VERSION 5.8 ;
BUSBITCHARS "[]" ;
DIVIDERCHAR "/" ;
UNITS
    DATABASE MICRONS 1000 ;
END UNITS

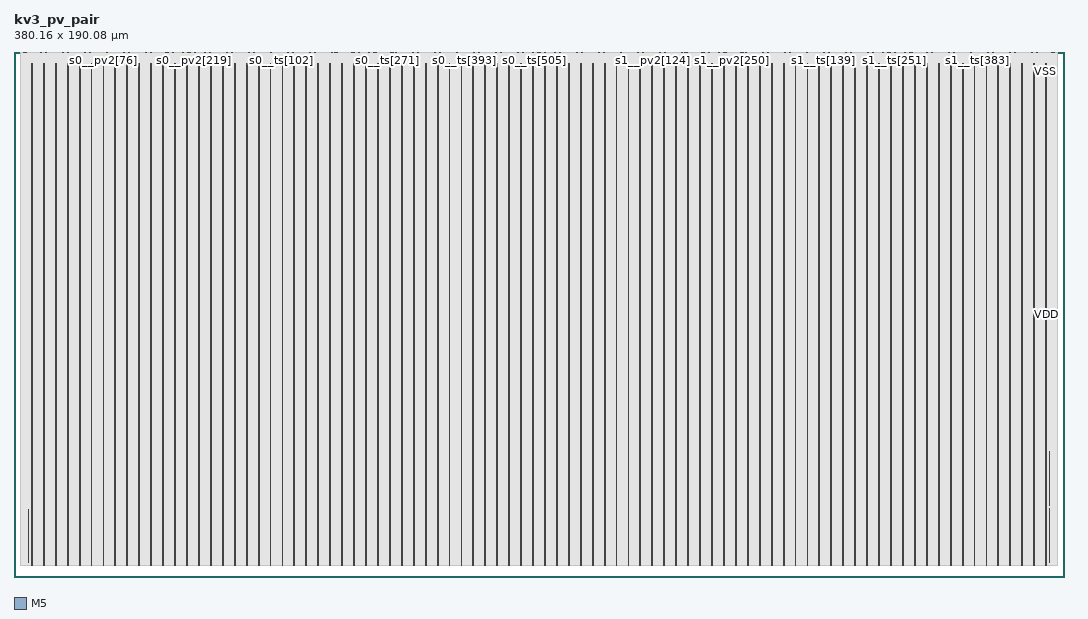
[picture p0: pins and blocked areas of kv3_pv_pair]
MACRO kv3_pv_pair
  FOREIGN kv3_pv_pair 0 0 ;
  CLASS BLOCK ;
  SIZE 380.16 BY 190.08 ;
  PIN s0__bc[0]
    DIRECTION INPUT ;
    USE SIGNAL ;
    PORT
      LAYER M5 ;
        RECT  2.268 189.888 2.292 190.08 ;
    END
  END s0__bc[0]
  PIN s0__bc[10]
    DIRECTION INPUT ;
    USE SIGNAL ;
    PORT
      LAYER M5 ;
        RECT  4.524 189.888 4.548 190.08 ;
    END
  END s0__bc[10]
  PIN s0__bc[11]
    DIRECTION INPUT ;
    USE SIGNAL ;
    PORT
      LAYER M5 ;
        RECT  4.764 189.888 4.788 190.08 ;
    END
  END s0__bc[11]
  PIN s0__bc[12]
    DIRECTION INPUT ;
    USE SIGNAL ;
    PORT
      LAYER M5 ;
        RECT  5.004 189.888 5.028 190.08 ;
    END
  END s0__bc[12]
  PIN s0__bc[13]
    DIRECTION INPUT ;
    USE SIGNAL ;
    PORT
      LAYER M5 ;
        RECT  5.196 189.888 5.22 190.08 ;
    END
  END s0__bc[13]
  PIN s0__bc[14]
    DIRECTION INPUT ;
    USE SIGNAL ;
    PORT
      LAYER M5 ;
        RECT  5.436 189.888 5.46 190.08 ;
    END
  END s0__bc[14]
  PIN s0__bc[15]
    DIRECTION INPUT ;
    USE SIGNAL ;
    PORT
      LAYER M5 ;
        RECT  5.676 189.888 5.7 190.08 ;
    END
  END s0__bc[15]
  PIN s0__bc[16]
    DIRECTION INPUT ;
    USE SIGNAL ;
    PORT
      LAYER M5 ;
        RECT  5.916 189.888 5.94 190.08 ;
    END
  END s0__bc[16]
  PIN s0__bc[17]
    DIRECTION INPUT ;
    USE SIGNAL ;
    PORT
      LAYER M5 ;
        RECT  6.108 189.888 6.132 190.08 ;
    END
  END s0__bc[17]
  PIN s0__bc[18]
    DIRECTION INPUT ;
    USE SIGNAL ;
    PORT
      LAYER M5 ;
        RECT  6.348 189.888 6.372 190.08 ;
    END
  END s0__bc[18]
  PIN s0__bc[19]
    DIRECTION INPUT ;
    USE SIGNAL ;
    PORT
      LAYER M5 ;
        RECT  6.588 189.888 6.612 190.08 ;
    END
  END s0__bc[19]
  PIN s0__bc[1]
    DIRECTION INPUT ;
    USE SIGNAL ;
    PORT
      LAYER M5 ;
        RECT  2.508 189.888 2.532 190.08 ;
    END
  END s0__bc[1]
  PIN s0__bc[20]
    DIRECTION INPUT ;
    USE SIGNAL ;
    PORT
      LAYER M5 ;
        RECT  6.828 189.888 6.852 190.08 ;
    END
  END s0__bc[20]
  PIN s0__bc[21]
    DIRECTION INPUT ;
    USE SIGNAL ;
    PORT
      LAYER M5 ;
        RECT  7.02 189.888 7.044 190.08 ;
    END
  END s0__bc[21]
  PIN s0__bc[22]
    DIRECTION INPUT ;
    USE SIGNAL ;
    PORT
      LAYER M5 ;
        RECT  7.26 189.888 7.284 190.08 ;
    END
  END s0__bc[22]
  PIN s0__bc[2]
    DIRECTION INPUT ;
    USE SIGNAL ;
    PORT
      LAYER M5 ;
        RECT  2.7 189.888 2.724 190.08 ;
    END
  END s0__bc[2]
  PIN s0__bc[3]
    DIRECTION INPUT ;
    USE SIGNAL ;
    PORT
      LAYER M5 ;
        RECT  2.94 189.888 2.964 190.08 ;
    END
  END s0__bc[3]
  PIN s0__bc[4]
    DIRECTION INPUT ;
    USE SIGNAL ;
    PORT
      LAYER M5 ;
        RECT  3.18 189.888 3.204 190.08 ;
    END
  END s0__bc[4]
  PIN s0__bc[5]
    DIRECTION INPUT ;
    USE SIGNAL ;
    PORT
      LAYER M5 ;
        RECT  3.42 189.888 3.444 190.08 ;
    END
  END s0__bc[5]
  PIN s0__bc[6]
    DIRECTION INPUT ;
    USE SIGNAL ;
    PORT
      LAYER M5 ;
        RECT  3.612 189.888 3.636 190.08 ;
    END
  END s0__bc[6]
  PIN s0__bc[7]
    DIRECTION INPUT ;
    USE SIGNAL ;
    PORT
      LAYER M5 ;
        RECT  3.852 189.888 3.876 190.08 ;
    END
  END s0__bc[7]
  PIN s0__bc[8]
    DIRECTION INPUT ;
    USE SIGNAL ;
    PORT
      LAYER M5 ;
        RECT  4.092 189.888 4.116 190.08 ;
    END
  END s0__bc[8]
  PIN s0__bc[9]
    DIRECTION INPUT ;
    USE SIGNAL ;
    PORT
      LAYER M5 ;
        RECT  4.332 189.888 4.356 190.08 ;
    END
  END s0__bc[9]
  PIN s0__clk[0]
    DIRECTION INPUT ;
    USE SIGNAL ;
    PORT
      LAYER M5 ;
        RECT  7.5 189.888 7.524 190.08 ;
    END
  END s0__clk[0]
  PIN s0__fault[0]
    DIRECTION OUTPUT ;
    USE SIGNAL ;
    PORT
      LAYER M5 ;
        RECT  7.74 189.888 7.764 190.08 ;
    END
  END s0__fault[0]
  PIN s0__pe2[0]
    DIRECTION INPUT ;
    USE SIGNAL ;
    PORT
      LAYER M5 ;
        RECT  7.932 189.888 7.956 190.08 ;
    END
  END s0__pe2[0]
  PIN s0__pe2[10]
    DIRECTION INPUT ;
    USE SIGNAL ;
    PORT
      LAYER M5 ;
        RECT  10.236 189.888 10.26 190.08 ;
    END
  END s0__pe2[10]
  PIN s0__pe2[11]
    DIRECTION INPUT ;
    USE SIGNAL ;
    PORT
      LAYER M5 ;
        RECT  10.428 189.888 10.452 190.08 ;
    END
  END s0__pe2[11]
  PIN s0__pe2[12]
    DIRECTION INPUT ;
    USE SIGNAL ;
    PORT
      LAYER M5 ;
        RECT  10.668 189.888 10.692 190.08 ;
    END
  END s0__pe2[12]
  PIN s0__pe2[13]
    DIRECTION INPUT ;
    USE SIGNAL ;
    PORT
      LAYER M5 ;
        RECT  10.908 189.888 10.932 190.08 ;
    END
  END s0__pe2[13]
  PIN s0__pe2[14]
    DIRECTION INPUT ;
    USE SIGNAL ;
    PORT
      LAYER M5 ;
        RECT  11.148 189.888 11.172 190.08 ;
    END
  END s0__pe2[14]
  PIN s0__pe2[15]
    DIRECTION INPUT ;
    USE SIGNAL ;
    PORT
      LAYER M5 ;
        RECT  11.34 189.888 11.364 190.08 ;
    END
  END s0__pe2[15]
  PIN s0__pe2[16]
    DIRECTION INPUT ;
    USE SIGNAL ;
    PORT
      LAYER M5 ;
        RECT  11.58 189.888 11.604 190.08 ;
    END
  END s0__pe2[16]
  PIN s0__pe2[17]
    DIRECTION INPUT ;
    USE SIGNAL ;
    PORT
      LAYER M5 ;
        RECT  11.82 189.888 11.844 190.08 ;
    END
  END s0__pe2[17]
  PIN s0__pe2[18]
    DIRECTION INPUT ;
    USE SIGNAL ;
    PORT
      LAYER M5 ;
        RECT  12.06 189.888 12.084 190.08 ;
    END
  END s0__pe2[18]
  PIN s0__pe2[19]
    DIRECTION INPUT ;
    USE SIGNAL ;
    PORT
      LAYER M5 ;
        RECT  12.252 189.888 12.276 190.08 ;
    END
  END s0__pe2[19]
  PIN s0__pe2[1]
    DIRECTION INPUT ;
    USE SIGNAL ;
    PORT
      LAYER M5 ;
        RECT  8.172 189.888 8.196 190.08 ;
    END
  END s0__pe2[1]
  PIN s0__pe2[20]
    DIRECTION INPUT ;
    USE SIGNAL ;
    PORT
      LAYER M5 ;
        RECT  12.492 189.888 12.516 190.08 ;
    END
  END s0__pe2[20]
  PIN s0__pe2[21]
    DIRECTION INPUT ;
    USE SIGNAL ;
    PORT
      LAYER M5 ;
        RECT  12.732 189.888 12.756 190.08 ;
    END
  END s0__pe2[21]
  PIN s0__pe2[22]
    DIRECTION INPUT ;
    USE SIGNAL ;
    PORT
      LAYER M5 ;
        RECT  12.972 189.888 12.996 190.08 ;
    END
  END s0__pe2[22]
  PIN s0__pe2[23]
    DIRECTION INPUT ;
    USE SIGNAL ;
    PORT
      LAYER M5 ;
        RECT  13.164 189.888 13.188 190.08 ;
    END
  END s0__pe2[23]
  PIN s0__pe2[24]
    DIRECTION INPUT ;
    USE SIGNAL ;
    PORT
      LAYER M5 ;
        RECT  13.404 189.888 13.428 190.08 ;
    END
  END s0__pe2[24]
  PIN s0__pe2[25]
    DIRECTION INPUT ;
    USE SIGNAL ;
    PORT
      LAYER M5 ;
        RECT  13.644 189.888 13.668 190.08 ;
    END
  END s0__pe2[25]
  PIN s0__pe2[26]
    DIRECTION INPUT ;
    USE SIGNAL ;
    PORT
      LAYER M5 ;
        RECT  13.884 189.888 13.908 190.08 ;
    END
  END s0__pe2[26]
  PIN s0__pe2[27]
    DIRECTION INPUT ;
    USE SIGNAL ;
    PORT
      LAYER M5 ;
        RECT  14.076 189.888 14.1 190.08 ;
    END
  END s0__pe2[27]
  PIN s0__pe2[28]
    DIRECTION INPUT ;
    USE SIGNAL ;
    PORT
      LAYER M5 ;
        RECT  14.316 189.888 14.34 190.08 ;
    END
  END s0__pe2[28]
  PIN s0__pe2[29]
    DIRECTION INPUT ;
    USE SIGNAL ;
    PORT
      LAYER M5 ;
        RECT  14.556 189.888 14.58 190.08 ;
    END
  END s0__pe2[29]
  PIN s0__pe2[2]
    DIRECTION INPUT ;
    USE SIGNAL ;
    PORT
      LAYER M5 ;
        RECT  8.412 189.888 8.436 190.08 ;
    END
  END s0__pe2[2]
  PIN s0__pe2[30]
    DIRECTION INPUT ;
    USE SIGNAL ;
    PORT
      LAYER M5 ;
        RECT  14.796 189.888 14.82 190.08 ;
    END
  END s0__pe2[30]
  PIN s0__pe2[31]
    DIRECTION INPUT ;
    USE SIGNAL ;
    PORT
      LAYER M5 ;
        RECT  14.988 189.888 15.012 190.08 ;
    END
  END s0__pe2[31]
  PIN s0__pe2[3]
    DIRECTION INPUT ;
    USE SIGNAL ;
    PORT
      LAYER M5 ;
        RECT  8.652 189.888 8.676 190.08 ;
    END
  END s0__pe2[3]
  PIN s0__pe2[4]
    DIRECTION INPUT ;
    USE SIGNAL ;
    PORT
      LAYER M5 ;
        RECT  8.844 189.888 8.868 190.08 ;
    END
  END s0__pe2[4]
  PIN s0__pe2[5]
    DIRECTION INPUT ;
    USE SIGNAL ;
    PORT
      LAYER M5 ;
        RECT  9.084 189.888 9.108 190.08 ;
    END
  END s0__pe2[5]
  PIN s0__pe2[6]
    DIRECTION INPUT ;
    USE SIGNAL ;
    PORT
      LAYER M5 ;
        RECT  9.324 189.888 9.348 190.08 ;
    END
  END s0__pe2[6]
  PIN s0__pe2[7]
    DIRECTION INPUT ;
    USE SIGNAL ;
    PORT
      LAYER M5 ;
        RECT  9.564 189.888 9.588 190.08 ;
    END
  END s0__pe2[7]
  PIN s0__pe2[8]
    DIRECTION INPUT ;
    USE SIGNAL ;
    PORT
      LAYER M5 ;
        RECT  9.756 189.888 9.78 190.08 ;
    END
  END s0__pe2[8]
  PIN s0__pe2[9]
    DIRECTION INPUT ;
    USE SIGNAL ;
    PORT
      LAYER M5 ;
        RECT  9.996 189.888 10.02 190.08 ;
    END
  END s0__pe2[9]
  PIN s0__pv2[0]
    DIRECTION INPUT ;
    USE SIGNAL ;
    PORT
      LAYER M5 ;
        RECT  15.228 189.888 15.252 190.08 ;
    END
  END s0__pv2[0]
  PIN s0__pv2[100]
    DIRECTION INPUT ;
    USE SIGNAL ;
    PORT
      LAYER M5 ;
        RECT  37.98 189.888 38.004 190.08 ;
    END
  END s0__pv2[100]
  PIN s0__pv2[101]
    DIRECTION INPUT ;
    USE SIGNAL ;
    PORT
      LAYER M5 ;
        RECT  38.22 189.888 38.244 190.08 ;
    END
  END s0__pv2[101]
  PIN s0__pv2[102]
    DIRECTION INPUT ;
    USE SIGNAL ;
    PORT
      LAYER M5 ;
        RECT  38.412 189.888 38.436 190.08 ;
    END
  END s0__pv2[102]
  PIN s0__pv2[103]
    DIRECTION INPUT ;
    USE SIGNAL ;
    PORT
      LAYER M5 ;
        RECT  38.652 189.888 38.676 190.08 ;
    END
  END s0__pv2[103]
  PIN s0__pv2[104]
    DIRECTION INPUT ;
    USE SIGNAL ;
    PORT
      LAYER M5 ;
        RECT  38.892 189.888 38.916 190.08 ;
    END
  END s0__pv2[104]
  PIN s0__pv2[105]
    DIRECTION INPUT ;
    USE SIGNAL ;
    PORT
      LAYER M5 ;
        RECT  39.132 189.888 39.156 190.08 ;
    END
  END s0__pv2[105]
  PIN s0__pv2[106]
    DIRECTION INPUT ;
    USE SIGNAL ;
    PORT
      LAYER M5 ;
        RECT  39.324 189.888 39.348 190.08 ;
    END
  END s0__pv2[106]
  PIN s0__pv2[107]
    DIRECTION INPUT ;
    USE SIGNAL ;
    PORT
      LAYER M5 ;
        RECT  39.564 189.888 39.588 190.08 ;
    END
  END s0__pv2[107]
  PIN s0__pv2[108]
    DIRECTION INPUT ;
    USE SIGNAL ;
    PORT
      LAYER M5 ;
        RECT  39.804 189.888 39.828 190.08 ;
    END
  END s0__pv2[108]
  PIN s0__pv2[109]
    DIRECTION INPUT ;
    USE SIGNAL ;
    PORT
      LAYER M5 ;
        RECT  40.044 189.888 40.068 190.08 ;
    END
  END s0__pv2[109]
  PIN s0__pv2[10]
    DIRECTION INPUT ;
    USE SIGNAL ;
    PORT
      LAYER M5 ;
        RECT  17.484 189.888 17.508 190.08 ;
    END
  END s0__pv2[10]
  PIN s0__pv2[110]
    DIRECTION INPUT ;
    USE SIGNAL ;
    PORT
      LAYER M5 ;
        RECT  40.236 189.888 40.26 190.08 ;
    END
  END s0__pv2[110]
  PIN s0__pv2[111]
    DIRECTION INPUT ;
    USE SIGNAL ;
    PORT
      LAYER M5 ;
        RECT  40.476 189.888 40.5 190.08 ;
    END
  END s0__pv2[111]
  PIN s0__pv2[112]
    DIRECTION INPUT ;
    USE SIGNAL ;
    PORT
      LAYER M5 ;
        RECT  40.716 189.888 40.74 190.08 ;
    END
  END s0__pv2[112]
  PIN s0__pv2[113]
    DIRECTION INPUT ;
    USE SIGNAL ;
    PORT
      LAYER M5 ;
        RECT  40.956 189.888 40.98 190.08 ;
    END
  END s0__pv2[113]
  PIN s0__pv2[114]
    DIRECTION INPUT ;
    USE SIGNAL ;
    PORT
      LAYER M5 ;
        RECT  41.148 189.888 41.172 190.08 ;
    END
  END s0__pv2[114]
  PIN s0__pv2[115]
    DIRECTION INPUT ;
    USE SIGNAL ;
    PORT
      LAYER M5 ;
        RECT  41.388 189.888 41.412 190.08 ;
    END
  END s0__pv2[115]
  PIN s0__pv2[116]
    DIRECTION INPUT ;
    USE SIGNAL ;
    PORT
      LAYER M5 ;
        RECT  41.628 189.888 41.652 190.08 ;
    END
  END s0__pv2[116]
  PIN s0__pv2[117]
    DIRECTION INPUT ;
    USE SIGNAL ;
    PORT
      LAYER M5 ;
        RECT  41.868 189.888 41.892 190.08 ;
    END
  END s0__pv2[117]
  PIN s0__pv2[118]
    DIRECTION INPUT ;
    USE SIGNAL ;
    PORT
      LAYER M5 ;
        RECT  42.06 189.888 42.084 190.08 ;
    END
  END s0__pv2[118]
  PIN s0__pv2[119]
    DIRECTION INPUT ;
    USE SIGNAL ;
    PORT
      LAYER M5 ;
        RECT  42.3 189.888 42.324 190.08 ;
    END
  END s0__pv2[119]
  PIN s0__pv2[11]
    DIRECTION INPUT ;
    USE SIGNAL ;
    PORT
      LAYER M5 ;
        RECT  17.724 189.888 17.748 190.08 ;
    END
  END s0__pv2[11]
  PIN s0__pv2[120]
    DIRECTION INPUT ;
    USE SIGNAL ;
    PORT
      LAYER M5 ;
        RECT  42.54 189.888 42.564 190.08 ;
    END
  END s0__pv2[120]
  PIN s0__pv2[121]
    DIRECTION INPUT ;
    USE SIGNAL ;
    PORT
      LAYER M5 ;
        RECT  42.78 189.888 42.804 190.08 ;
    END
  END s0__pv2[121]
  PIN s0__pv2[122]
    DIRECTION INPUT ;
    USE SIGNAL ;
    PORT
      LAYER M5 ;
        RECT  42.972 189.888 42.996 190.08 ;
    END
  END s0__pv2[122]
  PIN s0__pv2[123]
    DIRECTION INPUT ;
    USE SIGNAL ;
    PORT
      LAYER M5 ;
        RECT  43.212 189.888 43.236 190.08 ;
    END
  END s0__pv2[123]
  PIN s0__pv2[124]
    DIRECTION INPUT ;
    USE SIGNAL ;
    PORT
      LAYER M5 ;
        RECT  43.452 189.888 43.476 190.08 ;
    END
  END s0__pv2[124]
  PIN s0__pv2[125]
    DIRECTION INPUT ;
    USE SIGNAL ;
    PORT
      LAYER M5 ;
        RECT  43.644 189.888 43.668 190.08 ;
    END
  END s0__pv2[125]
  PIN s0__pv2[126]
    DIRECTION INPUT ;
    USE SIGNAL ;
    PORT
      LAYER M5 ;
        RECT  43.884 189.888 43.908 190.08 ;
    END
  END s0__pv2[126]
  PIN s0__pv2[127]
    DIRECTION INPUT ;
    USE SIGNAL ;
    PORT
      LAYER M5 ;
        RECT  44.124 189.888 44.148 190.08 ;
    END
  END s0__pv2[127]
  PIN s0__pv2[128]
    DIRECTION INPUT ;
    USE SIGNAL ;
    PORT
      LAYER M5 ;
        RECT  44.364 189.888 44.388 190.08 ;
    END
  END s0__pv2[128]
  PIN s0__pv2[129]
    DIRECTION INPUT ;
    USE SIGNAL ;
    PORT
      LAYER M5 ;
        RECT  44.556 189.888 44.58 190.08 ;
    END
  END s0__pv2[129]
  PIN s0__pv2[12]
    DIRECTION INPUT ;
    USE SIGNAL ;
    PORT
      LAYER M5 ;
        RECT  17.964 189.888 17.988 190.08 ;
    END
  END s0__pv2[12]
  PIN s0__pv2[130]
    DIRECTION INPUT ;
    USE SIGNAL ;
    PORT
      LAYER M5 ;
        RECT  44.796 189.888 44.82 190.08 ;
    END
  END s0__pv2[130]
  PIN s0__pv2[131]
    DIRECTION INPUT ;
    USE SIGNAL ;
    PORT
      LAYER M5 ;
        RECT  45.036 189.888 45.06 190.08 ;
    END
  END s0__pv2[131]
  PIN s0__pv2[132]
    DIRECTION INPUT ;
    USE SIGNAL ;
    PORT
      LAYER M5 ;
        RECT  45.276 189.888 45.3 190.08 ;
    END
  END s0__pv2[132]
  PIN s0__pv2[133]
    DIRECTION INPUT ;
    USE SIGNAL ;
    PORT
      LAYER M5 ;
        RECT  45.468 189.888 45.492 190.08 ;
    END
  END s0__pv2[133]
  PIN s0__pv2[134]
    DIRECTION INPUT ;
    USE SIGNAL ;
    PORT
      LAYER M5 ;
        RECT  45.708 189.888 45.732 190.08 ;
    END
  END s0__pv2[134]
  PIN s0__pv2[135]
    DIRECTION INPUT ;
    USE SIGNAL ;
    PORT
      LAYER M5 ;
        RECT  45.948 189.888 45.972 190.08 ;
    END
  END s0__pv2[135]
  PIN s0__pv2[136]
    DIRECTION INPUT ;
    USE SIGNAL ;
    PORT
      LAYER M5 ;
        RECT  46.188 189.888 46.212 190.08 ;
    END
  END s0__pv2[136]
  PIN s0__pv2[137]
    DIRECTION INPUT ;
    USE SIGNAL ;
    PORT
      LAYER M5 ;
        RECT  46.38 189.888 46.404 190.08 ;
    END
  END s0__pv2[137]
  PIN s0__pv2[138]
    DIRECTION INPUT ;
    USE SIGNAL ;
    PORT
      LAYER M5 ;
        RECT  46.62 189.888 46.644 190.08 ;
    END
  END s0__pv2[138]
  PIN s0__pv2[139]
    DIRECTION INPUT ;
    USE SIGNAL ;
    PORT
      LAYER M5 ;
        RECT  46.86 189.888 46.884 190.08 ;
    END
  END s0__pv2[139]
  PIN s0__pv2[13]
    DIRECTION INPUT ;
    USE SIGNAL ;
    PORT
      LAYER M5 ;
        RECT  18.204 189.888 18.228 190.08 ;
    END
  END s0__pv2[13]
  PIN s0__pv2[140]
    DIRECTION INPUT ;
    USE SIGNAL ;
    PORT
      LAYER M5 ;
        RECT  47.1 189.888 47.124 190.08 ;
    END
  END s0__pv2[140]
  PIN s0__pv2[141]
    DIRECTION INPUT ;
    USE SIGNAL ;
    PORT
      LAYER M5 ;
        RECT  47.292 189.888 47.316 190.08 ;
    END
  END s0__pv2[141]
  PIN s0__pv2[142]
    DIRECTION INPUT ;
    USE SIGNAL ;
    PORT
      LAYER M5 ;
        RECT  47.532 189.888 47.556 190.08 ;
    END
  END s0__pv2[142]
  PIN s0__pv2[143]
    DIRECTION INPUT ;
    USE SIGNAL ;
    PORT
      LAYER M5 ;
        RECT  47.772 189.888 47.796 190.08 ;
    END
  END s0__pv2[143]
  PIN s0__pv2[144]
    DIRECTION INPUT ;
    USE SIGNAL ;
    PORT
      LAYER M5 ;
        RECT  48.012 189.888 48.036 190.08 ;
    END
  END s0__pv2[144]
  PIN s0__pv2[145]
    DIRECTION INPUT ;
    USE SIGNAL ;
    PORT
      LAYER M5 ;
        RECT  48.204 189.888 48.228 190.08 ;
    END
  END s0__pv2[145]
  PIN s0__pv2[146]
    DIRECTION INPUT ;
    USE SIGNAL ;
    PORT
      LAYER M5 ;
        RECT  48.444 189.888 48.468 190.08 ;
    END
  END s0__pv2[146]
  PIN s0__pv2[147]
    DIRECTION INPUT ;
    USE SIGNAL ;
    PORT
      LAYER M5 ;
        RECT  48.684 189.888 48.708 190.08 ;
    END
  END s0__pv2[147]
  PIN s0__pv2[148]
    DIRECTION INPUT ;
    USE SIGNAL ;
    PORT
      LAYER M5 ;
        RECT  48.924 189.888 48.948 190.08 ;
    END
  END s0__pv2[148]
  PIN s0__pv2[149]
    DIRECTION INPUT ;
    USE SIGNAL ;
    PORT
      LAYER M5 ;
        RECT  49.116 189.888 49.14 190.08 ;
    END
  END s0__pv2[149]
  PIN s0__pv2[14]
    DIRECTION INPUT ;
    USE SIGNAL ;
    PORT
      LAYER M5 ;
        RECT  18.396 189.888 18.42 190.08 ;
    END
  END s0__pv2[14]
  PIN s0__pv2[150]
    DIRECTION INPUT ;
    USE SIGNAL ;
    PORT
      LAYER M5 ;
        RECT  49.356 189.888 49.38 190.08 ;
    END
  END s0__pv2[150]
  PIN s0__pv2[151]
    DIRECTION INPUT ;
    USE SIGNAL ;
    PORT
      LAYER M5 ;
        RECT  49.596 189.888 49.62 190.08 ;
    END
  END s0__pv2[151]
  PIN s0__pv2[152]
    DIRECTION INPUT ;
    USE SIGNAL ;
    PORT
      LAYER M5 ;
        RECT  49.788 189.888 49.812 190.08 ;
    END
  END s0__pv2[152]
  PIN s0__pv2[153]
    DIRECTION INPUT ;
    USE SIGNAL ;
    PORT
      LAYER M5 ;
        RECT  50.028 189.888 50.052 190.08 ;
    END
  END s0__pv2[153]
  PIN s0__pv2[154]
    DIRECTION INPUT ;
    USE SIGNAL ;
    PORT
      LAYER M5 ;
        RECT  50.268 189.888 50.292 190.08 ;
    END
  END s0__pv2[154]
  PIN s0__pv2[155]
    DIRECTION INPUT ;
    USE SIGNAL ;
    PORT
      LAYER M5 ;
        RECT  50.508 189.888 50.532 190.08 ;
    END
  END s0__pv2[155]
  PIN s0__pv2[156]
    DIRECTION INPUT ;
    USE SIGNAL ;
    PORT
      LAYER M5 ;
        RECT  50.7 189.888 50.724 190.08 ;
    END
  END s0__pv2[156]
  PIN s0__pv2[157]
    DIRECTION INPUT ;
    USE SIGNAL ;
    PORT
      LAYER M5 ;
        RECT  50.94 189.888 50.964 190.08 ;
    END
  END s0__pv2[157]
  PIN s0__pv2[158]
    DIRECTION INPUT ;
    USE SIGNAL ;
    PORT
      LAYER M5 ;
        RECT  51.18 189.888 51.204 190.08 ;
    END
  END s0__pv2[158]
  PIN s0__pv2[159]
    DIRECTION INPUT ;
    USE SIGNAL ;
    PORT
      LAYER M5 ;
        RECT  51.42 189.888 51.444 190.08 ;
    END
  END s0__pv2[159]
  PIN s0__pv2[15]
    DIRECTION INPUT ;
    USE SIGNAL ;
    PORT
      LAYER M5 ;
        RECT  18.636 189.888 18.66 190.08 ;
    END
  END s0__pv2[15]
  PIN s0__pv2[160]
    DIRECTION INPUT ;
    USE SIGNAL ;
    PORT
      LAYER M5 ;
        RECT  51.612 189.888 51.636 190.08 ;
    END
  END s0__pv2[160]
  PIN s0__pv2[161]
    DIRECTION INPUT ;
    USE SIGNAL ;
    PORT
      LAYER M5 ;
        RECT  51.852 189.888 51.876 190.08 ;
    END
  END s0__pv2[161]
  PIN s0__pv2[162]
    DIRECTION INPUT ;
    USE SIGNAL ;
    PORT
      LAYER M5 ;
        RECT  52.092 189.888 52.116 190.08 ;
    END
  END s0__pv2[162]
  PIN s0__pv2[163]
    DIRECTION INPUT ;
    USE SIGNAL ;
    PORT
      LAYER M5 ;
        RECT  52.332 189.888 52.356 190.08 ;
    END
  END s0__pv2[163]
  PIN s0__pv2[164]
    DIRECTION INPUT ;
    USE SIGNAL ;
    PORT
      LAYER M5 ;
        RECT  52.524 189.888 52.548 190.08 ;
    END
  END s0__pv2[164]
  PIN s0__pv2[165]
    DIRECTION INPUT ;
    USE SIGNAL ;
    PORT
      LAYER M5 ;
        RECT  52.764 189.888 52.788 190.08 ;
    END
  END s0__pv2[165]
  PIN s0__pv2[166]
    DIRECTION INPUT ;
    USE SIGNAL ;
    PORT
      LAYER M5 ;
        RECT  53.004 189.888 53.028 190.08 ;
    END
  END s0__pv2[166]
  PIN s0__pv2[167]
    DIRECTION INPUT ;
    USE SIGNAL ;
    PORT
      LAYER M5 ;
        RECT  53.244 189.888 53.268 190.08 ;
    END
  END s0__pv2[167]
  PIN s0__pv2[168]
    DIRECTION INPUT ;
    USE SIGNAL ;
    PORT
      LAYER M5 ;
        RECT  53.436 189.888 53.46 190.08 ;
    END
  END s0__pv2[168]
  PIN s0__pv2[169]
    DIRECTION INPUT ;
    USE SIGNAL ;
    PORT
      LAYER M5 ;
        RECT  53.676 189.888 53.7 190.08 ;
    END
  END s0__pv2[169]
  PIN s0__pv2[16]
    DIRECTION INPUT ;
    USE SIGNAL ;
    PORT
      LAYER M5 ;
        RECT  18.876 189.888 18.9 190.08 ;
    END
  END s0__pv2[16]
  PIN s0__pv2[170]
    DIRECTION INPUT ;
    USE SIGNAL ;
    PORT
      LAYER M5 ;
        RECT  53.916 189.888 53.94 190.08 ;
    END
  END s0__pv2[170]
  PIN s0__pv2[171]
    DIRECTION INPUT ;
    USE SIGNAL ;
    PORT
      LAYER M5 ;
        RECT  54.156 189.888 54.18 190.08 ;
    END
  END s0__pv2[171]
  PIN s0__pv2[172]
    DIRECTION INPUT ;
    USE SIGNAL ;
    PORT
      LAYER M5 ;
        RECT  54.348 189.888 54.372 190.08 ;
    END
  END s0__pv2[172]
  PIN s0__pv2[173]
    DIRECTION INPUT ;
    USE SIGNAL ;
    PORT
      LAYER M5 ;
        RECT  54.588 189.888 54.612 190.08 ;
    END
  END s0__pv2[173]
  PIN s0__pv2[174]
    DIRECTION INPUT ;
    USE SIGNAL ;
    PORT
      LAYER M5 ;
        RECT  54.828 189.888 54.852 190.08 ;
    END
  END s0__pv2[174]
  PIN s0__pv2[175]
    DIRECTION INPUT ;
    USE SIGNAL ;
    PORT
      LAYER M5 ;
        RECT  55.02 189.888 55.044 190.08 ;
    END
  END s0__pv2[175]
  PIN s0__pv2[176]
    DIRECTION INPUT ;
    USE SIGNAL ;
    PORT
      LAYER M5 ;
        RECT  55.26 189.888 55.284 190.08 ;
    END
  END s0__pv2[176]
  PIN s0__pv2[177]
    DIRECTION INPUT ;
    USE SIGNAL ;
    PORT
      LAYER M5 ;
        RECT  55.5 189.888 55.524 190.08 ;
    END
  END s0__pv2[177]
  PIN s0__pv2[178]
    DIRECTION INPUT ;
    USE SIGNAL ;
    PORT
      LAYER M5 ;
        RECT  55.74 189.888 55.764 190.08 ;
    END
  END s0__pv2[178]
  PIN s0__pv2[179]
    DIRECTION INPUT ;
    USE SIGNAL ;
    PORT
      LAYER M5 ;
        RECT  55.932 189.888 55.956 190.08 ;
    END
  END s0__pv2[179]
  PIN s0__pv2[17]
    DIRECTION INPUT ;
    USE SIGNAL ;
    PORT
      LAYER M5 ;
        RECT  19.116 189.888 19.14 190.08 ;
    END
  END s0__pv2[17]
  PIN s0__pv2[180]
    DIRECTION INPUT ;
    USE SIGNAL ;
    PORT
      LAYER M5 ;
        RECT  56.172 189.888 56.196 190.08 ;
    END
  END s0__pv2[180]
  PIN s0__pv2[181]
    DIRECTION INPUT ;
    USE SIGNAL ;
    PORT
      LAYER M5 ;
        RECT  56.412 189.888 56.436 190.08 ;
    END
  END s0__pv2[181]
  PIN s0__pv2[182]
    DIRECTION INPUT ;
    USE SIGNAL ;
    PORT
      LAYER M5 ;
        RECT  56.652 189.888 56.676 190.08 ;
    END
  END s0__pv2[182]
  PIN s0__pv2[183]
    DIRECTION INPUT ;
    USE SIGNAL ;
    PORT
      LAYER M5 ;
        RECT  56.844 189.888 56.868 190.08 ;
    END
  END s0__pv2[183]
  PIN s0__pv2[184]
    DIRECTION INPUT ;
    USE SIGNAL ;
    PORT
      LAYER M5 ;
        RECT  57.084 189.888 57.108 190.08 ;
    END
  END s0__pv2[184]
  PIN s0__pv2[185]
    DIRECTION INPUT ;
    USE SIGNAL ;
    PORT
      LAYER M5 ;
        RECT  57.324 189.888 57.348 190.08 ;
    END
  END s0__pv2[185]
  PIN s0__pv2[186]
    DIRECTION INPUT ;
    USE SIGNAL ;
    PORT
      LAYER M5 ;
        RECT  57.564 189.888 57.588 190.08 ;
    END
  END s0__pv2[186]
  PIN s0__pv2[187]
    DIRECTION INPUT ;
    USE SIGNAL ;
    PORT
      LAYER M5 ;
        RECT  57.756 189.888 57.78 190.08 ;
    END
  END s0__pv2[187]
  PIN s0__pv2[188]
    DIRECTION INPUT ;
    USE SIGNAL ;
    PORT
      LAYER M5 ;
        RECT  57.996 189.888 58.02 190.08 ;
    END
  END s0__pv2[188]
  PIN s0__pv2[189]
    DIRECTION INPUT ;
    USE SIGNAL ;
    PORT
      LAYER M5 ;
        RECT  58.236 189.888 58.26 190.08 ;
    END
  END s0__pv2[189]
  PIN s0__pv2[18]
    DIRECTION INPUT ;
    USE SIGNAL ;
    PORT
      LAYER M5 ;
        RECT  19.308 189.888 19.332 190.08 ;
    END
  END s0__pv2[18]
  PIN s0__pv2[190]
    DIRECTION INPUT ;
    USE SIGNAL ;
    PORT
      LAYER M5 ;
        RECT  58.476 189.888 58.5 190.08 ;
    END
  END s0__pv2[190]
  PIN s0__pv2[191]
    DIRECTION INPUT ;
    USE SIGNAL ;
    PORT
      LAYER M5 ;
        RECT  58.668 189.888 58.692 190.08 ;
    END
  END s0__pv2[191]
  PIN s0__pv2[192]
    DIRECTION INPUT ;
    USE SIGNAL ;
    PORT
      LAYER M5 ;
        RECT  58.908 189.888 58.932 190.08 ;
    END
  END s0__pv2[192]
  PIN s0__pv2[193]
    DIRECTION INPUT ;
    USE SIGNAL ;
    PORT
      LAYER M5 ;
        RECT  59.148 189.888 59.172 190.08 ;
    END
  END s0__pv2[193]
  PIN s0__pv2[194]
    DIRECTION INPUT ;
    USE SIGNAL ;
    PORT
      LAYER M5 ;
        RECT  59.388 189.888 59.412 190.08 ;
    END
  END s0__pv2[194]
  PIN s0__pv2[195]
    DIRECTION INPUT ;
    USE SIGNAL ;
    PORT
      LAYER M5 ;
        RECT  59.58 189.888 59.604 190.08 ;
    END
  END s0__pv2[195]
  PIN s0__pv2[196]
    DIRECTION INPUT ;
    USE SIGNAL ;
    PORT
      LAYER M5 ;
        RECT  59.82 189.888 59.844 190.08 ;
    END
  END s0__pv2[196]
  PIN s0__pv2[197]
    DIRECTION INPUT ;
    USE SIGNAL ;
    PORT
      LAYER M5 ;
        RECT  60.06 189.888 60.084 190.08 ;
    END
  END s0__pv2[197]
  PIN s0__pv2[198]
    DIRECTION INPUT ;
    USE SIGNAL ;
    PORT
      LAYER M5 ;
        RECT  60.252 189.888 60.276 190.08 ;
    END
  END s0__pv2[198]
  PIN s0__pv2[199]
    DIRECTION INPUT ;
    USE SIGNAL ;
    PORT
      LAYER M5 ;
        RECT  60.492 189.888 60.516 190.08 ;
    END
  END s0__pv2[199]
  PIN s0__pv2[19]
    DIRECTION INPUT ;
    USE SIGNAL ;
    PORT
      LAYER M5 ;
        RECT  19.548 189.888 19.572 190.08 ;
    END
  END s0__pv2[19]
  PIN s0__pv2[1]
    DIRECTION INPUT ;
    USE SIGNAL ;
    PORT
      LAYER M5 ;
        RECT  15.468 189.888 15.492 190.08 ;
    END
  END s0__pv2[1]
  PIN s0__pv2[200]
    DIRECTION INPUT ;
    USE SIGNAL ;
    PORT
      LAYER M5 ;
        RECT  60.732 189.888 60.756 190.08 ;
    END
  END s0__pv2[200]
  PIN s0__pv2[201]
    DIRECTION INPUT ;
    USE SIGNAL ;
    PORT
      LAYER M5 ;
        RECT  60.972 189.888 60.996 190.08 ;
    END
  END s0__pv2[201]
  PIN s0__pv2[202]
    DIRECTION INPUT ;
    USE SIGNAL ;
    PORT
      LAYER M5 ;
        RECT  61.164 189.888 61.188 190.08 ;
    END
  END s0__pv2[202]
  PIN s0__pv2[203]
    DIRECTION INPUT ;
    USE SIGNAL ;
    PORT
      LAYER M5 ;
        RECT  61.404 189.888 61.428 190.08 ;
    END
  END s0__pv2[203]
  PIN s0__pv2[204]
    DIRECTION INPUT ;
    USE SIGNAL ;
    PORT
      LAYER M5 ;
        RECT  61.644 189.888 61.668 190.08 ;
    END
  END s0__pv2[204]
  PIN s0__pv2[205]
    DIRECTION INPUT ;
    USE SIGNAL ;
    PORT
      LAYER M5 ;
        RECT  61.884 189.888 61.908 190.08 ;
    END
  END s0__pv2[205]
  PIN s0__pv2[206]
    DIRECTION INPUT ;
    USE SIGNAL ;
    PORT
      LAYER M5 ;
        RECT  62.076 189.888 62.1 190.08 ;
    END
  END s0__pv2[206]
  PIN s0__pv2[207]
    DIRECTION INPUT ;
    USE SIGNAL ;
    PORT
      LAYER M5 ;
        RECT  62.316 189.888 62.34 190.08 ;
    END
  END s0__pv2[207]
  PIN s0__pv2[208]
    DIRECTION INPUT ;
    USE SIGNAL ;
    PORT
      LAYER M5 ;
        RECT  62.556 189.888 62.58 190.08 ;
    END
  END s0__pv2[208]
  PIN s0__pv2[209]
    DIRECTION INPUT ;
    USE SIGNAL ;
    PORT
      LAYER M5 ;
        RECT  62.796 189.888 62.82 190.08 ;
    END
  END s0__pv2[209]
  PIN s0__pv2[20]
    DIRECTION INPUT ;
    USE SIGNAL ;
    PORT
      LAYER M5 ;
        RECT  19.788 189.888 19.812 190.08 ;
    END
  END s0__pv2[20]
  PIN s0__pv2[210]
    DIRECTION INPUT ;
    USE SIGNAL ;
    PORT
      LAYER M5 ;
        RECT  62.988 189.888 63.012 190.08 ;
    END
  END s0__pv2[210]
  PIN s0__pv2[211]
    DIRECTION INPUT ;
    USE SIGNAL ;
    PORT
      LAYER M5 ;
        RECT  63.228 189.888 63.252 190.08 ;
    END
  END s0__pv2[211]
  PIN s0__pv2[212]
    DIRECTION INPUT ;
    USE SIGNAL ;
    PORT
      LAYER M5 ;
        RECT  63.468 189.888 63.492 190.08 ;
    END
  END s0__pv2[212]
  PIN s0__pv2[213]
    DIRECTION INPUT ;
    USE SIGNAL ;
    PORT
      LAYER M5 ;
        RECT  63.708 189.888 63.732 190.08 ;
    END
  END s0__pv2[213]
  PIN s0__pv2[214]
    DIRECTION INPUT ;
    USE SIGNAL ;
    PORT
      LAYER M5 ;
        RECT  63.9 189.888 63.924 190.08 ;
    END
  END s0__pv2[214]
  PIN s0__pv2[215]
    DIRECTION INPUT ;
    USE SIGNAL ;
    PORT
      LAYER M5 ;
        RECT  64.14 189.888 64.164 190.08 ;
    END
  END s0__pv2[215]
  PIN s0__pv2[216]
    DIRECTION INPUT ;
    USE SIGNAL ;
    PORT
      LAYER M5 ;
        RECT  64.38 189.888 64.404 190.08 ;
    END
  END s0__pv2[216]
  PIN s0__pv2[217]
    DIRECTION INPUT ;
    USE SIGNAL ;
    PORT
      LAYER M5 ;
        RECT  64.62 189.888 64.644 190.08 ;
    END
  END s0__pv2[217]
  PIN s0__pv2[218]
    DIRECTION INPUT ;
    USE SIGNAL ;
    PORT
      LAYER M5 ;
        RECT  64.812 189.888 64.836 190.08 ;
    END
  END s0__pv2[218]
  PIN s0__pv2[219]
    DIRECTION INPUT ;
    USE SIGNAL ;
    PORT
      LAYER M5 ;
        RECT  65.052 189.888 65.076 190.08 ;
    END
  END s0__pv2[219]
  PIN s0__pv2[21]
    DIRECTION INPUT ;
    USE SIGNAL ;
    PORT
      LAYER M5 ;
        RECT  20.028 189.888 20.052 190.08 ;
    END
  END s0__pv2[21]
  PIN s0__pv2[220]
    DIRECTION INPUT ;
    USE SIGNAL ;
    PORT
      LAYER M5 ;
        RECT  65.292 189.888 65.316 190.08 ;
    END
  END s0__pv2[220]
  PIN s0__pv2[221]
    DIRECTION INPUT ;
    USE SIGNAL ;
    PORT
      LAYER M5 ;
        RECT  65.532 189.888 65.556 190.08 ;
    END
  END s0__pv2[221]
  PIN s0__pv2[222]
    DIRECTION INPUT ;
    USE SIGNAL ;
    PORT
      LAYER M5 ;
        RECT  65.724 189.888 65.748 190.08 ;
    END
  END s0__pv2[222]
  PIN s0__pv2[223]
    DIRECTION INPUT ;
    USE SIGNAL ;
    PORT
      LAYER M5 ;
        RECT  65.964 189.888 65.988 190.08 ;
    END
  END s0__pv2[223]
  PIN s0__pv2[224]
    DIRECTION INPUT ;
    USE SIGNAL ;
    PORT
      LAYER M5 ;
        RECT  66.204 189.888 66.228 190.08 ;
    END
  END s0__pv2[224]
  PIN s0__pv2[225]
    DIRECTION INPUT ;
    USE SIGNAL ;
    PORT
      LAYER M5 ;
        RECT  66.396 189.888 66.42 190.08 ;
    END
  END s0__pv2[225]
  PIN s0__pv2[226]
    DIRECTION INPUT ;
    USE SIGNAL ;
    PORT
      LAYER M5 ;
        RECT  66.636 189.888 66.66 190.08 ;
    END
  END s0__pv2[226]
  PIN s0__pv2[227]
    DIRECTION INPUT ;
    USE SIGNAL ;
    PORT
      LAYER M5 ;
        RECT  66.876 189.888 66.9 190.08 ;
    END
  END s0__pv2[227]
  PIN s0__pv2[228]
    DIRECTION INPUT ;
    USE SIGNAL ;
    PORT
      LAYER M5 ;
        RECT  67.116 189.888 67.14 190.08 ;
    END
  END s0__pv2[228]
  PIN s0__pv2[229]
    DIRECTION INPUT ;
    USE SIGNAL ;
    PORT
      LAYER M5 ;
        RECT  67.308 189.888 67.332 190.08 ;
    END
  END s0__pv2[229]
  PIN s0__pv2[22]
    DIRECTION INPUT ;
    USE SIGNAL ;
    PORT
      LAYER M5 ;
        RECT  20.22 189.888 20.244 190.08 ;
    END
  END s0__pv2[22]
  PIN s0__pv2[230]
    DIRECTION INPUT ;
    USE SIGNAL ;
    PORT
      LAYER M5 ;
        RECT  67.548 189.888 67.572 190.08 ;
    END
  END s0__pv2[230]
  PIN s0__pv2[231]
    DIRECTION INPUT ;
    USE SIGNAL ;
    PORT
      LAYER M5 ;
        RECT  67.788 189.888 67.812 190.08 ;
    END
  END s0__pv2[231]
  PIN s0__pv2[232]
    DIRECTION INPUT ;
    USE SIGNAL ;
    PORT
      LAYER M5 ;
        RECT  68.028 189.888 68.052 190.08 ;
    END
  END s0__pv2[232]
  PIN s0__pv2[233]
    DIRECTION INPUT ;
    USE SIGNAL ;
    PORT
      LAYER M5 ;
        RECT  68.22 189.888 68.244 190.08 ;
    END
  END s0__pv2[233]
  PIN s0__pv2[234]
    DIRECTION INPUT ;
    USE SIGNAL ;
    PORT
      LAYER M5 ;
        RECT  68.46 189.888 68.484 190.08 ;
    END
  END s0__pv2[234]
  PIN s0__pv2[235]
    DIRECTION INPUT ;
    USE SIGNAL ;
    PORT
      LAYER M5 ;
        RECT  68.7 189.888 68.724 190.08 ;
    END
  END s0__pv2[235]
  PIN s0__pv2[236]
    DIRECTION INPUT ;
    USE SIGNAL ;
    PORT
      LAYER M5 ;
        RECT  68.94 189.888 68.964 190.08 ;
    END
  END s0__pv2[236]
  PIN s0__pv2[237]
    DIRECTION INPUT ;
    USE SIGNAL ;
    PORT
      LAYER M5 ;
        RECT  69.132 189.888 69.156 190.08 ;
    END
  END s0__pv2[237]
  PIN s0__pv2[238]
    DIRECTION INPUT ;
    USE SIGNAL ;
    PORT
      LAYER M5 ;
        RECT  69.372 189.888 69.396 190.08 ;
    END
  END s0__pv2[238]
  PIN s0__pv2[239]
    DIRECTION INPUT ;
    USE SIGNAL ;
    PORT
      LAYER M5 ;
        RECT  69.612 189.888 69.636 190.08 ;
    END
  END s0__pv2[239]
  PIN s0__pv2[23]
    DIRECTION INPUT ;
    USE SIGNAL ;
    PORT
      LAYER M5 ;
        RECT  20.46 189.888 20.484 190.08 ;
    END
  END s0__pv2[23]
  PIN s0__pv2[240]
    DIRECTION INPUT ;
    USE SIGNAL ;
    PORT
      LAYER M5 ;
        RECT  69.852 189.888 69.876 190.08 ;
    END
  END s0__pv2[240]
  PIN s0__pv2[241]
    DIRECTION INPUT ;
    USE SIGNAL ;
    PORT
      LAYER M5 ;
        RECT  70.044 189.888 70.068 190.08 ;
    END
  END s0__pv2[241]
  PIN s0__pv2[242]
    DIRECTION INPUT ;
    USE SIGNAL ;
    PORT
      LAYER M5 ;
        RECT  70.284 189.888 70.308 190.08 ;
    END
  END s0__pv2[242]
  PIN s0__pv2[243]
    DIRECTION INPUT ;
    USE SIGNAL ;
    PORT
      LAYER M5 ;
        RECT  70.524 189.888 70.548 190.08 ;
    END
  END s0__pv2[243]
  PIN s0__pv2[244]
    DIRECTION INPUT ;
    USE SIGNAL ;
    PORT
      LAYER M5 ;
        RECT  70.764 189.888 70.788 190.08 ;
    END
  END s0__pv2[244]
  PIN s0__pv2[245]
    DIRECTION INPUT ;
    USE SIGNAL ;
    PORT
      LAYER M5 ;
        RECT  70.956 189.888 70.98 190.08 ;
    END
  END s0__pv2[245]
  PIN s0__pv2[246]
    DIRECTION INPUT ;
    USE SIGNAL ;
    PORT
      LAYER M5 ;
        RECT  71.196 189.888 71.22 190.08 ;
    END
  END s0__pv2[246]
  PIN s0__pv2[247]
    DIRECTION INPUT ;
    USE SIGNAL ;
    PORT
      LAYER M5 ;
        RECT  71.436 189.888 71.46 190.08 ;
    END
  END s0__pv2[247]
  PIN s0__pv2[248]
    DIRECTION INPUT ;
    USE SIGNAL ;
    PORT
      LAYER M5 ;
        RECT  71.628 189.888 71.652 190.08 ;
    END
  END s0__pv2[248]
  PIN s0__pv2[249]
    DIRECTION INPUT ;
    USE SIGNAL ;
    PORT
      LAYER M5 ;
        RECT  71.868 189.888 71.892 190.08 ;
    END
  END s0__pv2[249]
  PIN s0__pv2[24]
    DIRECTION INPUT ;
    USE SIGNAL ;
    PORT
      LAYER M5 ;
        RECT  20.7 189.888 20.724 190.08 ;
    END
  END s0__pv2[24]
  PIN s0__pv2[250]
    DIRECTION INPUT ;
    USE SIGNAL ;
    PORT
      LAYER M5 ;
        RECT  72.108 189.888 72.132 190.08 ;
    END
  END s0__pv2[250]
  PIN s0__pv2[251]
    DIRECTION INPUT ;
    USE SIGNAL ;
    PORT
      LAYER M5 ;
        RECT  72.348 189.888 72.372 190.08 ;
    END
  END s0__pv2[251]
  PIN s0__pv2[252]
    DIRECTION INPUT ;
    USE SIGNAL ;
    PORT
      LAYER M5 ;
        RECT  72.54 189.888 72.564 190.08 ;
    END
  END s0__pv2[252]
  PIN s0__pv2[253]
    DIRECTION INPUT ;
    USE SIGNAL ;
    PORT
      LAYER M5 ;
        RECT  72.78 189.888 72.804 190.08 ;
    END
  END s0__pv2[253]
  PIN s0__pv2[254]
    DIRECTION INPUT ;
    USE SIGNAL ;
    PORT
      LAYER M5 ;
        RECT  73.02 189.888 73.044 190.08 ;
    END
  END s0__pv2[254]
  PIN s0__pv2[255]
    DIRECTION INPUT ;
    USE SIGNAL ;
    PORT
      LAYER M5 ;
        RECT  73.26 189.888 73.284 190.08 ;
    END
  END s0__pv2[255]
  PIN s0__pv2[25]
    DIRECTION INPUT ;
    USE SIGNAL ;
    PORT
      LAYER M5 ;
        RECT  20.94 189.888 20.964 190.08 ;
    END
  END s0__pv2[25]
  PIN s0__pv2[26]
    DIRECTION INPUT ;
    USE SIGNAL ;
    PORT
      LAYER M5 ;
        RECT  21.132 189.888 21.156 190.08 ;
    END
  END s0__pv2[26]
  PIN s0__pv2[27]
    DIRECTION INPUT ;
    USE SIGNAL ;
    PORT
      LAYER M5 ;
        RECT  21.372 189.888 21.396 190.08 ;
    END
  END s0__pv2[27]
  PIN s0__pv2[28]
    DIRECTION INPUT ;
    USE SIGNAL ;
    PORT
      LAYER M5 ;
        RECT  21.612 189.888 21.636 190.08 ;
    END
  END s0__pv2[28]
  PIN s0__pv2[29]
    DIRECTION INPUT ;
    USE SIGNAL ;
    PORT
      LAYER M5 ;
        RECT  21.804 189.888 21.828 190.08 ;
    END
  END s0__pv2[29]
  PIN s0__pv2[2]
    DIRECTION INPUT ;
    USE SIGNAL ;
    PORT
      LAYER M5 ;
        RECT  15.708 189.888 15.732 190.08 ;
    END
  END s0__pv2[2]
  PIN s0__pv2[30]
    DIRECTION INPUT ;
    USE SIGNAL ;
    PORT
      LAYER M5 ;
        RECT  22.044 189.888 22.068 190.08 ;
    END
  END s0__pv2[30]
  PIN s0__pv2[31]
    DIRECTION INPUT ;
    USE SIGNAL ;
    PORT
      LAYER M5 ;
        RECT  22.284 189.888 22.308 190.08 ;
    END
  END s0__pv2[31]
  PIN s0__pv2[32]
    DIRECTION INPUT ;
    USE SIGNAL ;
    PORT
      LAYER M5 ;
        RECT  22.524 189.888 22.548 190.08 ;
    END
  END s0__pv2[32]
  PIN s0__pv2[33]
    DIRECTION INPUT ;
    USE SIGNAL ;
    PORT
      LAYER M5 ;
        RECT  22.716 189.888 22.74 190.08 ;
    END
  END s0__pv2[33]
  PIN s0__pv2[34]
    DIRECTION INPUT ;
    USE SIGNAL ;
    PORT
      LAYER M5 ;
        RECT  22.956 189.888 22.98 190.08 ;
    END
  END s0__pv2[34]
  PIN s0__pv2[35]
    DIRECTION INPUT ;
    USE SIGNAL ;
    PORT
      LAYER M5 ;
        RECT  23.196 189.888 23.22 190.08 ;
    END
  END s0__pv2[35]
  PIN s0__pv2[36]
    DIRECTION INPUT ;
    USE SIGNAL ;
    PORT
      LAYER M5 ;
        RECT  23.436 189.888 23.46 190.08 ;
    END
  END s0__pv2[36]
  PIN s0__pv2[37]
    DIRECTION INPUT ;
    USE SIGNAL ;
    PORT
      LAYER M5 ;
        RECT  23.628 189.888 23.652 190.08 ;
    END
  END s0__pv2[37]
  PIN s0__pv2[38]
    DIRECTION INPUT ;
    USE SIGNAL ;
    PORT
      LAYER M5 ;
        RECT  23.868 189.888 23.892 190.08 ;
    END
  END s0__pv2[38]
  PIN s0__pv2[39]
    DIRECTION INPUT ;
    USE SIGNAL ;
    PORT
      LAYER M5 ;
        RECT  24.108 189.888 24.132 190.08 ;
    END
  END s0__pv2[39]
  PIN s0__pv2[3]
    DIRECTION INPUT ;
    USE SIGNAL ;
    PORT
      LAYER M5 ;
        RECT  15.9 189.888 15.924 190.08 ;
    END
  END s0__pv2[3]
  PIN s0__pv2[40]
    DIRECTION INPUT ;
    USE SIGNAL ;
    PORT
      LAYER M5 ;
        RECT  24.348 189.888 24.372 190.08 ;
    END
  END s0__pv2[40]
  PIN s0__pv2[41]
    DIRECTION INPUT ;
    USE SIGNAL ;
    PORT
      LAYER M5 ;
        RECT  24.54 189.888 24.564 190.08 ;
    END
  END s0__pv2[41]
  PIN s0__pv2[42]
    DIRECTION INPUT ;
    USE SIGNAL ;
    PORT
      LAYER M5 ;
        RECT  24.78 189.888 24.804 190.08 ;
    END
  END s0__pv2[42]
  PIN s0__pv2[43]
    DIRECTION INPUT ;
    USE SIGNAL ;
    PORT
      LAYER M5 ;
        RECT  25.02 189.888 25.044 190.08 ;
    END
  END s0__pv2[43]
  PIN s0__pv2[44]
    DIRECTION INPUT ;
    USE SIGNAL ;
    PORT
      LAYER M5 ;
        RECT  25.26 189.888 25.284 190.08 ;
    END
  END s0__pv2[44]
  PIN s0__pv2[45]
    DIRECTION INPUT ;
    USE SIGNAL ;
    PORT
      LAYER M5 ;
        RECT  25.452 189.888 25.476 190.08 ;
    END
  END s0__pv2[45]
  PIN s0__pv2[46]
    DIRECTION INPUT ;
    USE SIGNAL ;
    PORT
      LAYER M5 ;
        RECT  25.692 189.888 25.716 190.08 ;
    END
  END s0__pv2[46]
  PIN s0__pv2[47]
    DIRECTION INPUT ;
    USE SIGNAL ;
    PORT
      LAYER M5 ;
        RECT  25.932 189.888 25.956 190.08 ;
    END
  END s0__pv2[47]
  PIN s0__pv2[48]
    DIRECTION INPUT ;
    USE SIGNAL ;
    PORT
      LAYER M5 ;
        RECT  26.172 189.888 26.196 190.08 ;
    END
  END s0__pv2[48]
  PIN s0__pv2[49]
    DIRECTION INPUT ;
    USE SIGNAL ;
    PORT
      LAYER M5 ;
        RECT  26.364 189.888 26.388 190.08 ;
    END
  END s0__pv2[49]
  PIN s0__pv2[4]
    DIRECTION INPUT ;
    USE SIGNAL ;
    PORT
      LAYER M5 ;
        RECT  16.14 189.888 16.164 190.08 ;
    END
  END s0__pv2[4]
  PIN s0__pv2[50]
    DIRECTION INPUT ;
    USE SIGNAL ;
    PORT
      LAYER M5 ;
        RECT  26.604 189.888 26.628 190.08 ;
    END
  END s0__pv2[50]
  PIN s0__pv2[51]
    DIRECTION INPUT ;
    USE SIGNAL ;
    PORT
      LAYER M5 ;
        RECT  26.844 189.888 26.868 190.08 ;
    END
  END s0__pv2[51]
  PIN s0__pv2[52]
    DIRECTION INPUT ;
    USE SIGNAL ;
    PORT
      LAYER M5 ;
        RECT  27.036 189.888 27.06 190.08 ;
    END
  END s0__pv2[52]
  PIN s0__pv2[53]
    DIRECTION INPUT ;
    USE SIGNAL ;
    PORT
      LAYER M5 ;
        RECT  27.276 189.888 27.3 190.08 ;
    END
  END s0__pv2[53]
  PIN s0__pv2[54]
    DIRECTION INPUT ;
    USE SIGNAL ;
    PORT
      LAYER M5 ;
        RECT  27.516 189.888 27.54 190.08 ;
    END
  END s0__pv2[54]
  PIN s0__pv2[55]
    DIRECTION INPUT ;
    USE SIGNAL ;
    PORT
      LAYER M5 ;
        RECT  27.756 189.888 27.78 190.08 ;
    END
  END s0__pv2[55]
  PIN s0__pv2[56]
    DIRECTION INPUT ;
    USE SIGNAL ;
    PORT
      LAYER M5 ;
        RECT  27.948 189.888 27.972 190.08 ;
    END
  END s0__pv2[56]
  PIN s0__pv2[57]
    DIRECTION INPUT ;
    USE SIGNAL ;
    PORT
      LAYER M5 ;
        RECT  28.188 189.888 28.212 190.08 ;
    END
  END s0__pv2[57]
  PIN s0__pv2[58]
    DIRECTION INPUT ;
    USE SIGNAL ;
    PORT
      LAYER M5 ;
        RECT  28.428 189.888 28.452 190.08 ;
    END
  END s0__pv2[58]
  PIN s0__pv2[59]
    DIRECTION INPUT ;
    USE SIGNAL ;
    PORT
      LAYER M5 ;
        RECT  28.668 189.888 28.692 190.08 ;
    END
  END s0__pv2[59]
  PIN s0__pv2[5]
    DIRECTION INPUT ;
    USE SIGNAL ;
    PORT
      LAYER M5 ;
        RECT  16.38 189.888 16.404 190.08 ;
    END
  END s0__pv2[5]
  PIN s0__pv2[60]
    DIRECTION INPUT ;
    USE SIGNAL ;
    PORT
      LAYER M5 ;
        RECT  28.86 189.888 28.884 190.08 ;
    END
  END s0__pv2[60]
  PIN s0__pv2[61]
    DIRECTION INPUT ;
    USE SIGNAL ;
    PORT
      LAYER M5 ;
        RECT  29.1 189.888 29.124 190.08 ;
    END
  END s0__pv2[61]
  PIN s0__pv2[62]
    DIRECTION INPUT ;
    USE SIGNAL ;
    PORT
      LAYER M5 ;
        RECT  29.34 189.888 29.364 190.08 ;
    END
  END s0__pv2[62]
  PIN s0__pv2[63]
    DIRECTION INPUT ;
    USE SIGNAL ;
    PORT
      LAYER M5 ;
        RECT  29.58 189.888 29.604 190.08 ;
    END
  END s0__pv2[63]
  PIN s0__pv2[64]
    DIRECTION INPUT ;
    USE SIGNAL ;
    PORT
      LAYER M5 ;
        RECT  29.772 189.888 29.796 190.08 ;
    END
  END s0__pv2[64]
  PIN s0__pv2[65]
    DIRECTION INPUT ;
    USE SIGNAL ;
    PORT
      LAYER M5 ;
        RECT  30.012 189.888 30.036 190.08 ;
    END
  END s0__pv2[65]
  PIN s0__pv2[66]
    DIRECTION INPUT ;
    USE SIGNAL ;
    PORT
      LAYER M5 ;
        RECT  30.252 189.888 30.276 190.08 ;
    END
  END s0__pv2[66]
  PIN s0__pv2[67]
    DIRECTION INPUT ;
    USE SIGNAL ;
    PORT
      LAYER M5 ;
        RECT  30.492 189.888 30.516 190.08 ;
    END
  END s0__pv2[67]
  PIN s0__pv2[68]
    DIRECTION INPUT ;
    USE SIGNAL ;
    PORT
      LAYER M5 ;
        RECT  30.684 189.888 30.708 190.08 ;
    END
  END s0__pv2[68]
  PIN s0__pv2[69]
    DIRECTION INPUT ;
    USE SIGNAL ;
    PORT
      LAYER M5 ;
        RECT  30.924 189.888 30.948 190.08 ;
    END
  END s0__pv2[69]
  PIN s0__pv2[6]
    DIRECTION INPUT ;
    USE SIGNAL ;
    PORT
      LAYER M5 ;
        RECT  16.572 189.888 16.596 190.08 ;
    END
  END s0__pv2[6]
  PIN s0__pv2[70]
    DIRECTION INPUT ;
    USE SIGNAL ;
    PORT
      LAYER M5 ;
        RECT  31.164 189.888 31.188 190.08 ;
    END
  END s0__pv2[70]
  PIN s0__pv2[71]
    DIRECTION INPUT ;
    USE SIGNAL ;
    PORT
      LAYER M5 ;
        RECT  31.404 189.888 31.428 190.08 ;
    END
  END s0__pv2[71]
  PIN s0__pv2[72]
    DIRECTION INPUT ;
    USE SIGNAL ;
    PORT
      LAYER M5 ;
        RECT  31.596 189.888 31.62 190.08 ;
    END
  END s0__pv2[72]
  PIN s0__pv2[73]
    DIRECTION INPUT ;
    USE SIGNAL ;
    PORT
      LAYER M5 ;
        RECT  31.836 189.888 31.86 190.08 ;
    END
  END s0__pv2[73]
  PIN s0__pv2[74]
    DIRECTION INPUT ;
    USE SIGNAL ;
    PORT
      LAYER M5 ;
        RECT  32.076 189.888 32.1 190.08 ;
    END
  END s0__pv2[74]
  PIN s0__pv2[75]
    DIRECTION INPUT ;
    USE SIGNAL ;
    PORT
      LAYER M5 ;
        RECT  32.316 189.888 32.34 190.08 ;
    END
  END s0__pv2[75]
  PIN s0__pv2[76]
    DIRECTION INPUT ;
    USE SIGNAL ;
    PORT
      LAYER M5 ;
        RECT  32.508 189.888 32.532 190.08 ;
    END
  END s0__pv2[76]
  PIN s0__pv2[77]
    DIRECTION INPUT ;
    USE SIGNAL ;
    PORT
      LAYER M5 ;
        RECT  32.748 189.888 32.772 190.08 ;
    END
  END s0__pv2[77]
  PIN s0__pv2[78]
    DIRECTION INPUT ;
    USE SIGNAL ;
    PORT
      LAYER M5 ;
        RECT  32.988 189.888 33.012 190.08 ;
    END
  END s0__pv2[78]
  PIN s0__pv2[79]
    DIRECTION INPUT ;
    USE SIGNAL ;
    PORT
      LAYER M5 ;
        RECT  33.18 189.888 33.204 190.08 ;
    END
  END s0__pv2[79]
  PIN s0__pv2[7]
    DIRECTION INPUT ;
    USE SIGNAL ;
    PORT
      LAYER M5 ;
        RECT  16.812 189.888 16.836 190.08 ;
    END
  END s0__pv2[7]
  PIN s0__pv2[80]
    DIRECTION INPUT ;
    USE SIGNAL ;
    PORT
      LAYER M5 ;
        RECT  33.42 189.888 33.444 190.08 ;
    END
  END s0__pv2[80]
  PIN s0__pv2[81]
    DIRECTION INPUT ;
    USE SIGNAL ;
    PORT
      LAYER M5 ;
        RECT  33.66 189.888 33.684 190.08 ;
    END
  END s0__pv2[81]
  PIN s0__pv2[82]
    DIRECTION INPUT ;
    USE SIGNAL ;
    PORT
      LAYER M5 ;
        RECT  33.9 189.888 33.924 190.08 ;
    END
  END s0__pv2[82]
  PIN s0__pv2[83]
    DIRECTION INPUT ;
    USE SIGNAL ;
    PORT
      LAYER M5 ;
        RECT  34.092 189.888 34.116 190.08 ;
    END
  END s0__pv2[83]
  PIN s0__pv2[84]
    DIRECTION INPUT ;
    USE SIGNAL ;
    PORT
      LAYER M5 ;
        RECT  34.332 189.888 34.356 190.08 ;
    END
  END s0__pv2[84]
  PIN s0__pv2[85]
    DIRECTION INPUT ;
    USE SIGNAL ;
    PORT
      LAYER M5 ;
        RECT  34.572 189.888 34.596 190.08 ;
    END
  END s0__pv2[85]
  PIN s0__pv2[86]
    DIRECTION INPUT ;
    USE SIGNAL ;
    PORT
      LAYER M5 ;
        RECT  34.812 189.888 34.836 190.08 ;
    END
  END s0__pv2[86]
  PIN s0__pv2[87]
    DIRECTION INPUT ;
    USE SIGNAL ;
    PORT
      LAYER M5 ;
        RECT  35.004 189.888 35.028 190.08 ;
    END
  END s0__pv2[87]
  PIN s0__pv2[88]
    DIRECTION INPUT ;
    USE SIGNAL ;
    PORT
      LAYER M5 ;
        RECT  35.244 189.888 35.268 190.08 ;
    END
  END s0__pv2[88]
  PIN s0__pv2[89]
    DIRECTION INPUT ;
    USE SIGNAL ;
    PORT
      LAYER M5 ;
        RECT  35.484 189.888 35.508 190.08 ;
    END
  END s0__pv2[89]
  PIN s0__pv2[8]
    DIRECTION INPUT ;
    USE SIGNAL ;
    PORT
      LAYER M5 ;
        RECT  17.052 189.888 17.076 190.08 ;
    END
  END s0__pv2[8]
  PIN s0__pv2[90]
    DIRECTION INPUT ;
    USE SIGNAL ;
    PORT
      LAYER M5 ;
        RECT  35.724 189.888 35.748 190.08 ;
    END
  END s0__pv2[90]
  PIN s0__pv2[91]
    DIRECTION INPUT ;
    USE SIGNAL ;
    PORT
      LAYER M5 ;
        RECT  35.916 189.888 35.94 190.08 ;
    END
  END s0__pv2[91]
  PIN s0__pv2[92]
    DIRECTION INPUT ;
    USE SIGNAL ;
    PORT
      LAYER M5 ;
        RECT  36.156 189.888 36.18 190.08 ;
    END
  END s0__pv2[92]
  PIN s0__pv2[93]
    DIRECTION INPUT ;
    USE SIGNAL ;
    PORT
      LAYER M5 ;
        RECT  36.396 189.888 36.42 190.08 ;
    END
  END s0__pv2[93]
  PIN s0__pv2[94]
    DIRECTION INPUT ;
    USE SIGNAL ;
    PORT
      LAYER M5 ;
        RECT  36.636 189.888 36.66 190.08 ;
    END
  END s0__pv2[94]
  PIN s0__pv2[95]
    DIRECTION INPUT ;
    USE SIGNAL ;
    PORT
      LAYER M5 ;
        RECT  36.828 189.888 36.852 190.08 ;
    END
  END s0__pv2[95]
  PIN s0__pv2[96]
    DIRECTION INPUT ;
    USE SIGNAL ;
    PORT
      LAYER M5 ;
        RECT  37.068 189.888 37.092 190.08 ;
    END
  END s0__pv2[96]
  PIN s0__pv2[97]
    DIRECTION INPUT ;
    USE SIGNAL ;
    PORT
      LAYER M5 ;
        RECT  37.308 189.888 37.332 190.08 ;
    END
  END s0__pv2[97]
  PIN s0__pv2[98]
    DIRECTION INPUT ;
    USE SIGNAL ;
    PORT
      LAYER M5 ;
        RECT  37.548 189.888 37.572 190.08 ;
    END
  END s0__pv2[98]
  PIN s0__pv2[99]
    DIRECTION INPUT ;
    USE SIGNAL ;
    PORT
      LAYER M5 ;
        RECT  37.74 189.888 37.764 190.08 ;
    END
  END s0__pv2[99]
  PIN s0__pv2[9]
    DIRECTION INPUT ;
    USE SIGNAL ;
    PORT
      LAYER M5 ;
        RECT  17.292 189.888 17.316 190.08 ;
    END
  END s0__pv2[9]
  PIN s0__rst_n[0]
    DIRECTION INPUT ;
    USE SIGNAL ;
    PORT
      LAYER M5 ;
        RECT  73.452 189.888 73.476 190.08 ;
    END
  END s0__rst_n[0]
  PIN s0__ts[0]
    DIRECTION OUTPUT ;
    USE SIGNAL ;
    PORT
      LAYER M5 ;
        RECT  73.692 189.888 73.716 190.08 ;
    END
  END s0__ts[0]
  PIN s0__ts[100]
    DIRECTION OUTPUT ;
    USE SIGNAL ;
    PORT
      LAYER M5 ;
        RECT  96.444 189.888 96.468 190.08 ;
    END
  END s0__ts[100]
  PIN s0__ts[101]
    DIRECTION OUTPUT ;
    USE SIGNAL ;
    PORT
      LAYER M5 ;
        RECT  96.684 189.888 96.708 190.08 ;
    END
  END s0__ts[101]
  PIN s0__ts[102]
    DIRECTION OUTPUT ;
    USE SIGNAL ;
    PORT
      LAYER M5 ;
        RECT  96.924 189.888 96.948 190.08 ;
    END
  END s0__ts[102]
  PIN s0__ts[103]
    DIRECTION OUTPUT ;
    USE SIGNAL ;
    PORT
      LAYER M5 ;
        RECT  97.116 189.888 97.14 190.08 ;
    END
  END s0__ts[103]
  PIN s0__ts[104]
    DIRECTION OUTPUT ;
    USE SIGNAL ;
    PORT
      LAYER M5 ;
        RECT  97.356 189.888 97.38 190.08 ;
    END
  END s0__ts[104]
  PIN s0__ts[105]
    DIRECTION OUTPUT ;
    USE SIGNAL ;
    PORT
      LAYER M5 ;
        RECT  97.596 189.888 97.62 190.08 ;
    END
  END s0__ts[105]
  PIN s0__ts[106]
    DIRECTION OUTPUT ;
    USE SIGNAL ;
    PORT
      LAYER M5 ;
        RECT  97.836 189.888 97.86 190.08 ;
    END
  END s0__ts[106]
  PIN s0__ts[107]
    DIRECTION OUTPUT ;
    USE SIGNAL ;
    PORT
      LAYER M5 ;
        RECT  98.028 189.888 98.052 190.08 ;
    END
  END s0__ts[107]
  PIN s0__ts[108]
    DIRECTION OUTPUT ;
    USE SIGNAL ;
    PORT
      LAYER M5 ;
        RECT  98.268 189.888 98.292 190.08 ;
    END
  END s0__ts[108]
  PIN s0__ts[109]
    DIRECTION OUTPUT ;
    USE SIGNAL ;
    PORT
      LAYER M5 ;
        RECT  98.508 189.888 98.532 190.08 ;
    END
  END s0__ts[109]
  PIN s0__ts[10]
    DIRECTION OUTPUT ;
    USE SIGNAL ;
    PORT
      LAYER M5 ;
        RECT  75.996 189.888 76.02 190.08 ;
    END
  END s0__ts[10]
  PIN s0__ts[110]
    DIRECTION OUTPUT ;
    USE SIGNAL ;
    PORT
      LAYER M5 ;
        RECT  98.748 189.888 98.772 190.08 ;
    END
  END s0__ts[110]
  PIN s0__ts[111]
    DIRECTION OUTPUT ;
    USE SIGNAL ;
    PORT
      LAYER M5 ;
        RECT  98.94 189.888 98.964 190.08 ;
    END
  END s0__ts[111]
  PIN s0__ts[112]
    DIRECTION OUTPUT ;
    USE SIGNAL ;
    PORT
      LAYER M5 ;
        RECT  99.18 189.888 99.204 190.08 ;
    END
  END s0__ts[112]
  PIN s0__ts[113]
    DIRECTION OUTPUT ;
    USE SIGNAL ;
    PORT
      LAYER M5 ;
        RECT  99.42 189.888 99.444 190.08 ;
    END
  END s0__ts[113]
  PIN s0__ts[114]
    DIRECTION OUTPUT ;
    USE SIGNAL ;
    PORT
      LAYER M5 ;
        RECT  99.612 189.888 99.636 190.08 ;
    END
  END s0__ts[114]
  PIN s0__ts[115]
    DIRECTION OUTPUT ;
    USE SIGNAL ;
    PORT
      LAYER M5 ;
        RECT  99.852 189.888 99.876 190.08 ;
    END
  END s0__ts[115]
  PIN s0__ts[116]
    DIRECTION OUTPUT ;
    USE SIGNAL ;
    PORT
      LAYER M5 ;
        RECT  100.092 189.888 100.116 190.08 ;
    END
  END s0__ts[116]
  PIN s0__ts[117]
    DIRECTION OUTPUT ;
    USE SIGNAL ;
    PORT
      LAYER M5 ;
        RECT  100.332 189.888 100.356 190.08 ;
    END
  END s0__ts[117]
  PIN s0__ts[118]
    DIRECTION OUTPUT ;
    USE SIGNAL ;
    PORT
      LAYER M5 ;
        RECT  100.524 189.888 100.548 190.08 ;
    END
  END s0__ts[118]
  PIN s0__ts[119]
    DIRECTION OUTPUT ;
    USE SIGNAL ;
    PORT
      LAYER M5 ;
        RECT  100.764 189.888 100.788 190.08 ;
    END
  END s0__ts[119]
  PIN s0__ts[11]
    DIRECTION OUTPUT ;
    USE SIGNAL ;
    PORT
      LAYER M5 ;
        RECT  76.188 189.888 76.212 190.08 ;
    END
  END s0__ts[11]
  PIN s0__ts[120]
    DIRECTION OUTPUT ;
    USE SIGNAL ;
    PORT
      LAYER M5 ;
        RECT  101.004 189.888 101.028 190.08 ;
    END
  END s0__ts[120]
  PIN s0__ts[121]
    DIRECTION OUTPUT ;
    USE SIGNAL ;
    PORT
      LAYER M5 ;
        RECT  101.244 189.888 101.268 190.08 ;
    END
  END s0__ts[121]
  PIN s0__ts[122]
    DIRECTION OUTPUT ;
    USE SIGNAL ;
    PORT
      LAYER M5 ;
        RECT  101.436 189.888 101.46 190.08 ;
    END
  END s0__ts[122]
  PIN s0__ts[123]
    DIRECTION OUTPUT ;
    USE SIGNAL ;
    PORT
      LAYER M5 ;
        RECT  101.676 189.888 101.7 190.08 ;
    END
  END s0__ts[123]
  PIN s0__ts[124]
    DIRECTION OUTPUT ;
    USE SIGNAL ;
    PORT
      LAYER M5 ;
        RECT  101.916 189.888 101.94 190.08 ;
    END
  END s0__ts[124]
  PIN s0__ts[125]
    DIRECTION OUTPUT ;
    USE SIGNAL ;
    PORT
      LAYER M5 ;
        RECT  102.156 189.888 102.18 190.08 ;
    END
  END s0__ts[125]
  PIN s0__ts[126]
    DIRECTION OUTPUT ;
    USE SIGNAL ;
    PORT
      LAYER M5 ;
        RECT  102.348 189.888 102.372 190.08 ;
    END
  END s0__ts[126]
  PIN s0__ts[127]
    DIRECTION OUTPUT ;
    USE SIGNAL ;
    PORT
      LAYER M5 ;
        RECT  102.588 189.888 102.612 190.08 ;
    END
  END s0__ts[127]
  PIN s0__ts[128]
    DIRECTION OUTPUT ;
    USE SIGNAL ;
    PORT
      LAYER M5 ;
        RECT  102.828 189.888 102.852 190.08 ;
    END
  END s0__ts[128]
  PIN s0__ts[129]
    DIRECTION OUTPUT ;
    USE SIGNAL ;
    PORT
      LAYER M5 ;
        RECT  103.068 189.888 103.092 190.08 ;
    END
  END s0__ts[129]
  PIN s0__ts[12]
    DIRECTION OUTPUT ;
    USE SIGNAL ;
    PORT
      LAYER M5 ;
        RECT  76.428 189.888 76.452 190.08 ;
    END
  END s0__ts[12]
  PIN s0__ts[130]
    DIRECTION OUTPUT ;
    USE SIGNAL ;
    PORT
      LAYER M5 ;
        RECT  103.26 189.888 103.284 190.08 ;
    END
  END s0__ts[130]
  PIN s0__ts[131]
    DIRECTION OUTPUT ;
    USE SIGNAL ;
    PORT
      LAYER M5 ;
        RECT  103.5 189.888 103.524 190.08 ;
    END
  END s0__ts[131]
  PIN s0__ts[132]
    DIRECTION OUTPUT ;
    USE SIGNAL ;
    PORT
      LAYER M5 ;
        RECT  103.74 189.888 103.764 190.08 ;
    END
  END s0__ts[132]
  PIN s0__ts[133]
    DIRECTION OUTPUT ;
    USE SIGNAL ;
    PORT
      LAYER M5 ;
        RECT  103.98 189.888 104.004 190.08 ;
    END
  END s0__ts[133]
  PIN s0__ts[134]
    DIRECTION OUTPUT ;
    USE SIGNAL ;
    PORT
      LAYER M5 ;
        RECT  104.172 189.888 104.196 190.08 ;
    END
  END s0__ts[134]
  PIN s0__ts[135]
    DIRECTION OUTPUT ;
    USE SIGNAL ;
    PORT
      LAYER M5 ;
        RECT  104.412 189.888 104.436 190.08 ;
    END
  END s0__ts[135]
  PIN s0__ts[136]
    DIRECTION OUTPUT ;
    USE SIGNAL ;
    PORT
      LAYER M5 ;
        RECT  104.652 189.888 104.676 190.08 ;
    END
  END s0__ts[136]
  PIN s0__ts[137]
    DIRECTION OUTPUT ;
    USE SIGNAL ;
    PORT
      LAYER M5 ;
        RECT  104.844 189.888 104.868 190.08 ;
    END
  END s0__ts[137]
  PIN s0__ts[138]
    DIRECTION OUTPUT ;
    USE SIGNAL ;
    PORT
      LAYER M5 ;
        RECT  105.084 189.888 105.108 190.08 ;
    END
  END s0__ts[138]
  PIN s0__ts[139]
    DIRECTION OUTPUT ;
    USE SIGNAL ;
    PORT
      LAYER M5 ;
        RECT  105.324 189.888 105.348 190.08 ;
    END
  END s0__ts[139]
  PIN s0__ts[13]
    DIRECTION OUTPUT ;
    USE SIGNAL ;
    PORT
      LAYER M5 ;
        RECT  76.668 189.888 76.692 190.08 ;
    END
  END s0__ts[13]
  PIN s0__ts[140]
    DIRECTION OUTPUT ;
    USE SIGNAL ;
    PORT
      LAYER M5 ;
        RECT  105.564 189.888 105.588 190.08 ;
    END
  END s0__ts[140]
  PIN s0__ts[141]
    DIRECTION OUTPUT ;
    USE SIGNAL ;
    PORT
      LAYER M5 ;
        RECT  105.756 189.888 105.78 190.08 ;
    END
  END s0__ts[141]
  PIN s0__ts[142]
    DIRECTION OUTPUT ;
    USE SIGNAL ;
    PORT
      LAYER M5 ;
        RECT  105.996 189.888 106.02 190.08 ;
    END
  END s0__ts[142]
  PIN s0__ts[143]
    DIRECTION OUTPUT ;
    USE SIGNAL ;
    PORT
      LAYER M5 ;
        RECT  106.236 189.888 106.26 190.08 ;
    END
  END s0__ts[143]
  PIN s0__ts[144]
    DIRECTION OUTPUT ;
    USE SIGNAL ;
    PORT
      LAYER M5 ;
        RECT  106.476 189.888 106.5 190.08 ;
    END
  END s0__ts[144]
  PIN s0__ts[145]
    DIRECTION OUTPUT ;
    USE SIGNAL ;
    PORT
      LAYER M5 ;
        RECT  106.668 189.888 106.692 190.08 ;
    END
  END s0__ts[145]
  PIN s0__ts[146]
    DIRECTION OUTPUT ;
    USE SIGNAL ;
    PORT
      LAYER M5 ;
        RECT  106.908 189.888 106.932 190.08 ;
    END
  END s0__ts[146]
  PIN s0__ts[147]
    DIRECTION OUTPUT ;
    USE SIGNAL ;
    PORT
      LAYER M5 ;
        RECT  107.148 189.888 107.172 190.08 ;
    END
  END s0__ts[147]
  PIN s0__ts[148]
    DIRECTION OUTPUT ;
    USE SIGNAL ;
    PORT
      LAYER M5 ;
        RECT  107.388 189.888 107.412 190.08 ;
    END
  END s0__ts[148]
  PIN s0__ts[149]
    DIRECTION OUTPUT ;
    USE SIGNAL ;
    PORT
      LAYER M5 ;
        RECT  107.58 189.888 107.604 190.08 ;
    END
  END s0__ts[149]
  PIN s0__ts[14]
    DIRECTION OUTPUT ;
    USE SIGNAL ;
    PORT
      LAYER M5 ;
        RECT  76.86 189.888 76.884 190.08 ;
    END
  END s0__ts[14]
  PIN s0__ts[150]
    DIRECTION OUTPUT ;
    USE SIGNAL ;
    PORT
      LAYER M5 ;
        RECT  107.82 189.888 107.844 190.08 ;
    END
  END s0__ts[150]
  PIN s0__ts[151]
    DIRECTION OUTPUT ;
    USE SIGNAL ;
    PORT
      LAYER M5 ;
        RECT  108.06 189.888 108.084 190.08 ;
    END
  END s0__ts[151]
  PIN s0__ts[152]
    DIRECTION OUTPUT ;
    USE SIGNAL ;
    PORT
      LAYER M5 ;
        RECT  108.3 189.888 108.324 190.08 ;
    END
  END s0__ts[152]
  PIN s0__ts[153]
    DIRECTION OUTPUT ;
    USE SIGNAL ;
    PORT
      LAYER M5 ;
        RECT  108.492 189.888 108.516 190.08 ;
    END
  END s0__ts[153]
  PIN s0__ts[154]
    DIRECTION OUTPUT ;
    USE SIGNAL ;
    PORT
      LAYER M5 ;
        RECT  108.732 189.888 108.756 190.08 ;
    END
  END s0__ts[154]
  PIN s0__ts[155]
    DIRECTION OUTPUT ;
    USE SIGNAL ;
    PORT
      LAYER M5 ;
        RECT  108.972 189.888 108.996 190.08 ;
    END
  END s0__ts[155]
  PIN s0__ts[156]
    DIRECTION OUTPUT ;
    USE SIGNAL ;
    PORT
      LAYER M5 ;
        RECT  109.212 189.888 109.236 190.08 ;
    END
  END s0__ts[156]
  PIN s0__ts[157]
    DIRECTION OUTPUT ;
    USE SIGNAL ;
    PORT
      LAYER M5 ;
        RECT  109.404 189.888 109.428 190.08 ;
    END
  END s0__ts[157]
  PIN s0__ts[158]
    DIRECTION OUTPUT ;
    USE SIGNAL ;
    PORT
      LAYER M5 ;
        RECT  109.644 189.888 109.668 190.08 ;
    END
  END s0__ts[158]
  PIN s0__ts[159]
    DIRECTION OUTPUT ;
    USE SIGNAL ;
    PORT
      LAYER M5 ;
        RECT  109.884 189.888 109.908 190.08 ;
    END
  END s0__ts[159]
  PIN s0__ts[15]
    DIRECTION OUTPUT ;
    USE SIGNAL ;
    PORT
      LAYER M5 ;
        RECT  77.1 189.888 77.124 190.08 ;
    END
  END s0__ts[15]
  PIN s0__ts[160]
    DIRECTION OUTPUT ;
    USE SIGNAL ;
    PORT
      LAYER M5 ;
        RECT  110.076 189.888 110.1 190.08 ;
    END
  END s0__ts[160]
  PIN s0__ts[161]
    DIRECTION OUTPUT ;
    USE SIGNAL ;
    PORT
      LAYER M5 ;
        RECT  110.316 189.888 110.34 190.08 ;
    END
  END s0__ts[161]
  PIN s0__ts[162]
    DIRECTION OUTPUT ;
    USE SIGNAL ;
    PORT
      LAYER M5 ;
        RECT  110.556 189.888 110.58 190.08 ;
    END
  END s0__ts[162]
  PIN s0__ts[163]
    DIRECTION OUTPUT ;
    USE SIGNAL ;
    PORT
      LAYER M5 ;
        RECT  110.796 189.888 110.82 190.08 ;
    END
  END s0__ts[163]
  PIN s0__ts[164]
    DIRECTION OUTPUT ;
    USE SIGNAL ;
    PORT
      LAYER M5 ;
        RECT  110.988 189.888 111.012 190.08 ;
    END
  END s0__ts[164]
  PIN s0__ts[165]
    DIRECTION OUTPUT ;
    USE SIGNAL ;
    PORT
      LAYER M5 ;
        RECT  111.228 189.888 111.252 190.08 ;
    END
  END s0__ts[165]
  PIN s0__ts[166]
    DIRECTION OUTPUT ;
    USE SIGNAL ;
    PORT
      LAYER M5 ;
        RECT  111.468 189.888 111.492 190.08 ;
    END
  END s0__ts[166]
  PIN s0__ts[167]
    DIRECTION OUTPUT ;
    USE SIGNAL ;
    PORT
      LAYER M5 ;
        RECT  111.708 189.888 111.732 190.08 ;
    END
  END s0__ts[167]
  PIN s0__ts[168]
    DIRECTION OUTPUT ;
    USE SIGNAL ;
    PORT
      LAYER M5 ;
        RECT  111.9 189.888 111.924 190.08 ;
    END
  END s0__ts[168]
  PIN s0__ts[169]
    DIRECTION OUTPUT ;
    USE SIGNAL ;
    PORT
      LAYER M5 ;
        RECT  112.14 189.888 112.164 190.08 ;
    END
  END s0__ts[169]
  PIN s0__ts[16]
    DIRECTION OUTPUT ;
    USE SIGNAL ;
    PORT
      LAYER M5 ;
        RECT  77.34 189.888 77.364 190.08 ;
    END
  END s0__ts[16]
  PIN s0__ts[170]
    DIRECTION OUTPUT ;
    USE SIGNAL ;
    PORT
      LAYER M5 ;
        RECT  112.38 189.888 112.404 190.08 ;
    END
  END s0__ts[170]
  PIN s0__ts[171]
    DIRECTION OUTPUT ;
    USE SIGNAL ;
    PORT
      LAYER M5 ;
        RECT  112.62 189.888 112.644 190.08 ;
    END
  END s0__ts[171]
  PIN s0__ts[172]
    DIRECTION OUTPUT ;
    USE SIGNAL ;
    PORT
      LAYER M5 ;
        RECT  112.812 189.888 112.836 190.08 ;
    END
  END s0__ts[172]
  PIN s0__ts[173]
    DIRECTION OUTPUT ;
    USE SIGNAL ;
    PORT
      LAYER M5 ;
        RECT  113.052 189.888 113.076 190.08 ;
    END
  END s0__ts[173]
  PIN s0__ts[174]
    DIRECTION OUTPUT ;
    USE SIGNAL ;
    PORT
      LAYER M5 ;
        RECT  113.292 189.888 113.316 190.08 ;
    END
  END s0__ts[174]
  PIN s0__ts[175]
    DIRECTION OUTPUT ;
    USE SIGNAL ;
    PORT
      LAYER M5 ;
        RECT  113.532 189.888 113.556 190.08 ;
    END
  END s0__ts[175]
  PIN s0__ts[176]
    DIRECTION OUTPUT ;
    USE SIGNAL ;
    PORT
      LAYER M5 ;
        RECT  113.724 189.888 113.748 190.08 ;
    END
  END s0__ts[176]
  PIN s0__ts[177]
    DIRECTION OUTPUT ;
    USE SIGNAL ;
    PORT
      LAYER M5 ;
        RECT  113.964 189.888 113.988 190.08 ;
    END
  END s0__ts[177]
  PIN s0__ts[178]
    DIRECTION OUTPUT ;
    USE SIGNAL ;
    PORT
      LAYER M5 ;
        RECT  114.204 189.888 114.228 190.08 ;
    END
  END s0__ts[178]
  PIN s0__ts[179]
    DIRECTION OUTPUT ;
    USE SIGNAL ;
    PORT
      LAYER M5 ;
        RECT  114.444 189.888 114.468 190.08 ;
    END
  END s0__ts[179]
  PIN s0__ts[17]
    DIRECTION OUTPUT ;
    USE SIGNAL ;
    PORT
      LAYER M5 ;
        RECT  77.58 189.888 77.604 190.08 ;
    END
  END s0__ts[17]
  PIN s0__ts[180]
    DIRECTION OUTPUT ;
    USE SIGNAL ;
    PORT
      LAYER M5 ;
        RECT  114.636 189.888 114.66 190.08 ;
    END
  END s0__ts[180]
  PIN s0__ts[181]
    DIRECTION OUTPUT ;
    USE SIGNAL ;
    PORT
      LAYER M5 ;
        RECT  114.876 189.888 114.9 190.08 ;
    END
  END s0__ts[181]
  PIN s0__ts[182]
    DIRECTION OUTPUT ;
    USE SIGNAL ;
    PORT
      LAYER M5 ;
        RECT  115.116 189.888 115.14 190.08 ;
    END
  END s0__ts[182]
  PIN s0__ts[183]
    DIRECTION OUTPUT ;
    USE SIGNAL ;
    PORT
      LAYER M5 ;
        RECT  115.356 189.888 115.38 190.08 ;
    END
  END s0__ts[183]
  PIN s0__ts[184]
    DIRECTION OUTPUT ;
    USE SIGNAL ;
    PORT
      LAYER M5 ;
        RECT  115.548 189.888 115.572 190.08 ;
    END
  END s0__ts[184]
  PIN s0__ts[185]
    DIRECTION OUTPUT ;
    USE SIGNAL ;
    PORT
      LAYER M5 ;
        RECT  115.788 189.888 115.812 190.08 ;
    END
  END s0__ts[185]
  PIN s0__ts[186]
    DIRECTION OUTPUT ;
    USE SIGNAL ;
    PORT
      LAYER M5 ;
        RECT  116.028 189.888 116.052 190.08 ;
    END
  END s0__ts[186]
  PIN s0__ts[187]
    DIRECTION OUTPUT ;
    USE SIGNAL ;
    PORT
      LAYER M5 ;
        RECT  116.22 189.888 116.244 190.08 ;
    END
  END s0__ts[187]
  PIN s0__ts[188]
    DIRECTION OUTPUT ;
    USE SIGNAL ;
    PORT
      LAYER M5 ;
        RECT  116.46 189.888 116.484 190.08 ;
    END
  END s0__ts[188]
  PIN s0__ts[189]
    DIRECTION OUTPUT ;
    USE SIGNAL ;
    PORT
      LAYER M5 ;
        RECT  116.7 189.888 116.724 190.08 ;
    END
  END s0__ts[189]
  PIN s0__ts[18]
    DIRECTION OUTPUT ;
    USE SIGNAL ;
    PORT
      LAYER M5 ;
        RECT  77.772 189.888 77.796 190.08 ;
    END
  END s0__ts[18]
  PIN s0__ts[190]
    DIRECTION OUTPUT ;
    USE SIGNAL ;
    PORT
      LAYER M5 ;
        RECT  116.94 189.888 116.964 190.08 ;
    END
  END s0__ts[190]
  PIN s0__ts[191]
    DIRECTION OUTPUT ;
    USE SIGNAL ;
    PORT
      LAYER M5 ;
        RECT  117.132 189.888 117.156 190.08 ;
    END
  END s0__ts[191]
  PIN s0__ts[192]
    DIRECTION OUTPUT ;
    USE SIGNAL ;
    PORT
      LAYER M5 ;
        RECT  117.372 189.888 117.396 190.08 ;
    END
  END s0__ts[192]
  PIN s0__ts[193]
    DIRECTION OUTPUT ;
    USE SIGNAL ;
    PORT
      LAYER M5 ;
        RECT  117.612 189.888 117.636 190.08 ;
    END
  END s0__ts[193]
  PIN s0__ts[194]
    DIRECTION OUTPUT ;
    USE SIGNAL ;
    PORT
      LAYER M5 ;
        RECT  117.852 189.888 117.876 190.08 ;
    END
  END s0__ts[194]
  PIN s0__ts[195]
    DIRECTION OUTPUT ;
    USE SIGNAL ;
    PORT
      LAYER M5 ;
        RECT  118.044 189.888 118.068 190.08 ;
    END
  END s0__ts[195]
  PIN s0__ts[196]
    DIRECTION OUTPUT ;
    USE SIGNAL ;
    PORT
      LAYER M5 ;
        RECT  118.284 189.888 118.308 190.08 ;
    END
  END s0__ts[196]
  PIN s0__ts[197]
    DIRECTION OUTPUT ;
    USE SIGNAL ;
    PORT
      LAYER M5 ;
        RECT  118.524 189.888 118.548 190.08 ;
    END
  END s0__ts[197]
  PIN s0__ts[198]
    DIRECTION OUTPUT ;
    USE SIGNAL ;
    PORT
      LAYER M5 ;
        RECT  118.764 189.888 118.788 190.08 ;
    END
  END s0__ts[198]
  PIN s0__ts[199]
    DIRECTION OUTPUT ;
    USE SIGNAL ;
    PORT
      LAYER M5 ;
        RECT  118.956 189.888 118.98 190.08 ;
    END
  END s0__ts[199]
  PIN s0__ts[19]
    DIRECTION OUTPUT ;
    USE SIGNAL ;
    PORT
      LAYER M5 ;
        RECT  78.012 189.888 78.036 190.08 ;
    END
  END s0__ts[19]
  PIN s0__ts[1]
    DIRECTION OUTPUT ;
    USE SIGNAL ;
    PORT
      LAYER M5 ;
        RECT  73.932 189.888 73.956 190.08 ;
    END
  END s0__ts[1]
  PIN s0__ts[200]
    DIRECTION OUTPUT ;
    USE SIGNAL ;
    PORT
      LAYER M5 ;
        RECT  119.196 189.888 119.22 190.08 ;
    END
  END s0__ts[200]
  PIN s0__ts[201]
    DIRECTION OUTPUT ;
    USE SIGNAL ;
    PORT
      LAYER M5 ;
        RECT  119.436 189.888 119.46 190.08 ;
    END
  END s0__ts[201]
  PIN s0__ts[202]
    DIRECTION OUTPUT ;
    USE SIGNAL ;
    PORT
      LAYER M5 ;
        RECT  119.676 189.888 119.7 190.08 ;
    END
  END s0__ts[202]
  PIN s0__ts[203]
    DIRECTION OUTPUT ;
    USE SIGNAL ;
    PORT
      LAYER M5 ;
        RECT  119.868 189.888 119.892 190.08 ;
    END
  END s0__ts[203]
  PIN s0__ts[204]
    DIRECTION OUTPUT ;
    USE SIGNAL ;
    PORT
      LAYER M5 ;
        RECT  120.108 189.888 120.132 190.08 ;
    END
  END s0__ts[204]
  PIN s0__ts[205]
    DIRECTION OUTPUT ;
    USE SIGNAL ;
    PORT
      LAYER M5 ;
        RECT  120.348 189.888 120.372 190.08 ;
    END
  END s0__ts[205]
  PIN s0__ts[206]
    DIRECTION OUTPUT ;
    USE SIGNAL ;
    PORT
      LAYER M5 ;
        RECT  120.588 189.888 120.612 190.08 ;
    END
  END s0__ts[206]
  PIN s0__ts[207]
    DIRECTION OUTPUT ;
    USE SIGNAL ;
    PORT
      LAYER M5 ;
        RECT  120.78 189.888 120.804 190.08 ;
    END
  END s0__ts[207]
  PIN s0__ts[208]
    DIRECTION OUTPUT ;
    USE SIGNAL ;
    PORT
      LAYER M5 ;
        RECT  121.02 189.888 121.044 190.08 ;
    END
  END s0__ts[208]
  PIN s0__ts[209]
    DIRECTION OUTPUT ;
    USE SIGNAL ;
    PORT
      LAYER M5 ;
        RECT  121.26 189.888 121.284 190.08 ;
    END
  END s0__ts[209]
  PIN s0__ts[20]
    DIRECTION OUTPUT ;
    USE SIGNAL ;
    PORT
      LAYER M5 ;
        RECT  78.252 189.888 78.276 190.08 ;
    END
  END s0__ts[20]
  PIN s0__ts[210]
    DIRECTION OUTPUT ;
    USE SIGNAL ;
    PORT
      LAYER M5 ;
        RECT  121.452 189.888 121.476 190.08 ;
    END
  END s0__ts[210]
  PIN s0__ts[211]
    DIRECTION OUTPUT ;
    USE SIGNAL ;
    PORT
      LAYER M5 ;
        RECT  121.692 189.888 121.716 190.08 ;
    END
  END s0__ts[211]
  PIN s0__ts[212]
    DIRECTION OUTPUT ;
    USE SIGNAL ;
    PORT
      LAYER M5 ;
        RECT  121.932 189.888 121.956 190.08 ;
    END
  END s0__ts[212]
  PIN s0__ts[213]
    DIRECTION OUTPUT ;
    USE SIGNAL ;
    PORT
      LAYER M5 ;
        RECT  122.172 189.888 122.196 190.08 ;
    END
  END s0__ts[213]
  PIN s0__ts[214]
    DIRECTION OUTPUT ;
    USE SIGNAL ;
    PORT
      LAYER M5 ;
        RECT  122.364 189.888 122.388 190.08 ;
    END
  END s0__ts[214]
  PIN s0__ts[215]
    DIRECTION OUTPUT ;
    USE SIGNAL ;
    PORT
      LAYER M5 ;
        RECT  122.604 189.888 122.628 190.08 ;
    END
  END s0__ts[215]
  PIN s0__ts[216]
    DIRECTION OUTPUT ;
    USE SIGNAL ;
    PORT
      LAYER M5 ;
        RECT  122.844 189.888 122.868 190.08 ;
    END
  END s0__ts[216]
  PIN s0__ts[217]
    DIRECTION OUTPUT ;
    USE SIGNAL ;
    PORT
      LAYER M5 ;
        RECT  123.084 189.888 123.108 190.08 ;
    END
  END s0__ts[217]
  PIN s0__ts[218]
    DIRECTION OUTPUT ;
    USE SIGNAL ;
    PORT
      LAYER M5 ;
        RECT  123.276 189.888 123.3 190.08 ;
    END
  END s0__ts[218]
  PIN s0__ts[219]
    DIRECTION OUTPUT ;
    USE SIGNAL ;
    PORT
      LAYER M5 ;
        RECT  123.516 189.888 123.54 190.08 ;
    END
  END s0__ts[219]
  PIN s0__ts[21]
    DIRECTION OUTPUT ;
    USE SIGNAL ;
    PORT
      LAYER M5 ;
        RECT  78.492 189.888 78.516 190.08 ;
    END
  END s0__ts[21]
  PIN s0__ts[220]
    DIRECTION OUTPUT ;
    USE SIGNAL ;
    PORT
      LAYER M5 ;
        RECT  123.756 189.888 123.78 190.08 ;
    END
  END s0__ts[220]
  PIN s0__ts[221]
    DIRECTION OUTPUT ;
    USE SIGNAL ;
    PORT
      LAYER M5 ;
        RECT  123.996 189.888 124.02 190.08 ;
    END
  END s0__ts[221]
  PIN s0__ts[222]
    DIRECTION OUTPUT ;
    USE SIGNAL ;
    PORT
      LAYER M5 ;
        RECT  124.188 189.888 124.212 190.08 ;
    END
  END s0__ts[222]
  PIN s0__ts[223]
    DIRECTION OUTPUT ;
    USE SIGNAL ;
    PORT
      LAYER M5 ;
        RECT  124.428 189.888 124.452 190.08 ;
    END
  END s0__ts[223]
  PIN s0__ts[224]
    DIRECTION OUTPUT ;
    USE SIGNAL ;
    PORT
      LAYER M5 ;
        RECT  124.668 189.888 124.692 190.08 ;
    END
  END s0__ts[224]
  PIN s0__ts[225]
    DIRECTION OUTPUT ;
    USE SIGNAL ;
    PORT
      LAYER M5 ;
        RECT  124.908 189.888 124.932 190.08 ;
    END
  END s0__ts[225]
  PIN s0__ts[226]
    DIRECTION OUTPUT ;
    USE SIGNAL ;
    PORT
      LAYER M5 ;
        RECT  125.1 189.888 125.124 190.08 ;
    END
  END s0__ts[226]
  PIN s0__ts[227]
    DIRECTION OUTPUT ;
    USE SIGNAL ;
    PORT
      LAYER M5 ;
        RECT  125.34 189.888 125.364 190.08 ;
    END
  END s0__ts[227]
  PIN s0__ts[228]
    DIRECTION OUTPUT ;
    USE SIGNAL ;
    PORT
      LAYER M5 ;
        RECT  125.58 189.888 125.604 190.08 ;
    END
  END s0__ts[228]
  PIN s0__ts[229]
    DIRECTION OUTPUT ;
    USE SIGNAL ;
    PORT
      LAYER M5 ;
        RECT  125.82 189.888 125.844 190.08 ;
    END
  END s0__ts[229]
  PIN s0__ts[22]
    DIRECTION OUTPUT ;
    USE SIGNAL ;
    PORT
      LAYER M5 ;
        RECT  78.684 189.888 78.708 190.08 ;
    END
  END s0__ts[22]
  PIN s0__ts[230]
    DIRECTION OUTPUT ;
    USE SIGNAL ;
    PORT
      LAYER M5 ;
        RECT  126.012 189.888 126.036 190.08 ;
    END
  END s0__ts[230]
  PIN s0__ts[231]
    DIRECTION OUTPUT ;
    USE SIGNAL ;
    PORT
      LAYER M5 ;
        RECT  126.252 189.888 126.276 190.08 ;
    END
  END s0__ts[231]
  PIN s0__ts[232]
    DIRECTION OUTPUT ;
    USE SIGNAL ;
    PORT
      LAYER M5 ;
        RECT  126.492 189.888 126.516 190.08 ;
    END
  END s0__ts[232]
  PIN s0__ts[233]
    DIRECTION OUTPUT ;
    USE SIGNAL ;
    PORT
      LAYER M5 ;
        RECT  126.684 189.888 126.708 190.08 ;
    END
  END s0__ts[233]
  PIN s0__ts[234]
    DIRECTION OUTPUT ;
    USE SIGNAL ;
    PORT
      LAYER M5 ;
        RECT  126.924 189.888 126.948 190.08 ;
    END
  END s0__ts[234]
  PIN s0__ts[235]
    DIRECTION OUTPUT ;
    USE SIGNAL ;
    PORT
      LAYER M5 ;
        RECT  127.164 189.888 127.188 190.08 ;
    END
  END s0__ts[235]
  PIN s0__ts[236]
    DIRECTION OUTPUT ;
    USE SIGNAL ;
    PORT
      LAYER M5 ;
        RECT  127.404 189.888 127.428 190.08 ;
    END
  END s0__ts[236]
  PIN s0__ts[237]
    DIRECTION OUTPUT ;
    USE SIGNAL ;
    PORT
      LAYER M5 ;
        RECT  127.596 189.888 127.62 190.08 ;
    END
  END s0__ts[237]
  PIN s0__ts[238]
    DIRECTION OUTPUT ;
    USE SIGNAL ;
    PORT
      LAYER M5 ;
        RECT  127.836 189.888 127.86 190.08 ;
    END
  END s0__ts[238]
  PIN s0__ts[239]
    DIRECTION OUTPUT ;
    USE SIGNAL ;
    PORT
      LAYER M5 ;
        RECT  128.076 189.888 128.1 190.08 ;
    END
  END s0__ts[239]
  PIN s0__ts[23]
    DIRECTION OUTPUT ;
    USE SIGNAL ;
    PORT
      LAYER M5 ;
        RECT  78.924 189.888 78.948 190.08 ;
    END
  END s0__ts[23]
  PIN s0__ts[240]
    DIRECTION OUTPUT ;
    USE SIGNAL ;
    PORT
      LAYER M5 ;
        RECT  128.316 189.888 128.34 190.08 ;
    END
  END s0__ts[240]
  PIN s0__ts[241]
    DIRECTION OUTPUT ;
    USE SIGNAL ;
    PORT
      LAYER M5 ;
        RECT  128.508 189.888 128.532 190.08 ;
    END
  END s0__ts[241]
  PIN s0__ts[242]
    DIRECTION OUTPUT ;
    USE SIGNAL ;
    PORT
      LAYER M5 ;
        RECT  128.748 189.888 128.772 190.08 ;
    END
  END s0__ts[242]
  PIN s0__ts[243]
    DIRECTION OUTPUT ;
    USE SIGNAL ;
    PORT
      LAYER M5 ;
        RECT  128.988 189.888 129.012 190.08 ;
    END
  END s0__ts[243]
  PIN s0__ts[244]
    DIRECTION OUTPUT ;
    USE SIGNAL ;
    PORT
      LAYER M5 ;
        RECT  129.228 189.888 129.252 190.08 ;
    END
  END s0__ts[244]
  PIN s0__ts[245]
    DIRECTION OUTPUT ;
    USE SIGNAL ;
    PORT
      LAYER M5 ;
        RECT  129.42 189.888 129.444 190.08 ;
    END
  END s0__ts[245]
  PIN s0__ts[246]
    DIRECTION OUTPUT ;
    USE SIGNAL ;
    PORT
      LAYER M5 ;
        RECT  129.66 189.888 129.684 190.08 ;
    END
  END s0__ts[246]
  PIN s0__ts[247]
    DIRECTION OUTPUT ;
    USE SIGNAL ;
    PORT
      LAYER M5 ;
        RECT  129.9 189.888 129.924 190.08 ;
    END
  END s0__ts[247]
  PIN s0__ts[248]
    DIRECTION OUTPUT ;
    USE SIGNAL ;
    PORT
      LAYER M5 ;
        RECT  130.14 189.888 130.164 190.08 ;
    END
  END s0__ts[248]
  PIN s0__ts[249]
    DIRECTION OUTPUT ;
    USE SIGNAL ;
    PORT
      LAYER M5 ;
        RECT  130.332 189.888 130.356 190.08 ;
    END
  END s0__ts[249]
  PIN s0__ts[24]
    DIRECTION OUTPUT ;
    USE SIGNAL ;
    PORT
      LAYER M5 ;
        RECT  79.164 189.888 79.188 190.08 ;
    END
  END s0__ts[24]
  PIN s0__ts[250]
    DIRECTION OUTPUT ;
    USE SIGNAL ;
    PORT
      LAYER M5 ;
        RECT  130.572 189.888 130.596 190.08 ;
    END
  END s0__ts[250]
  PIN s0__ts[251]
    DIRECTION OUTPUT ;
    USE SIGNAL ;
    PORT
      LAYER M5 ;
        RECT  130.812 189.888 130.836 190.08 ;
    END
  END s0__ts[251]
  PIN s0__ts[252]
    DIRECTION OUTPUT ;
    USE SIGNAL ;
    PORT
      LAYER M5 ;
        RECT  131.052 189.888 131.076 190.08 ;
    END
  END s0__ts[252]
  PIN s0__ts[253]
    DIRECTION OUTPUT ;
    USE SIGNAL ;
    PORT
      LAYER M5 ;
        RECT  131.244 189.888 131.268 190.08 ;
    END
  END s0__ts[253]
  PIN s0__ts[254]
    DIRECTION OUTPUT ;
    USE SIGNAL ;
    PORT
      LAYER M5 ;
        RECT  131.484 189.888 131.508 190.08 ;
    END
  END s0__ts[254]
  PIN s0__ts[255]
    DIRECTION OUTPUT ;
    USE SIGNAL ;
    PORT
      LAYER M5 ;
        RECT  131.724 189.888 131.748 190.08 ;
    END
  END s0__ts[255]
  PIN s0__ts[256]
    DIRECTION OUTPUT ;
    USE SIGNAL ;
    PORT
      LAYER M5 ;
        RECT  131.964 189.888 131.988 190.08 ;
    END
  END s0__ts[256]
  PIN s0__ts[257]
    DIRECTION OUTPUT ;
    USE SIGNAL ;
    PORT
      LAYER M5 ;
        RECT  132.156 189.888 132.18 190.08 ;
    END
  END s0__ts[257]
  PIN s0__ts[258]
    DIRECTION OUTPUT ;
    USE SIGNAL ;
    PORT
      LAYER M5 ;
        RECT  132.396 189.888 132.42 190.08 ;
    END
  END s0__ts[258]
  PIN s0__ts[259]
    DIRECTION OUTPUT ;
    USE SIGNAL ;
    PORT
      LAYER M5 ;
        RECT  132.636 189.888 132.66 190.08 ;
    END
  END s0__ts[259]
  PIN s0__ts[25]
    DIRECTION OUTPUT ;
    USE SIGNAL ;
    PORT
      LAYER M5 ;
        RECT  79.404 189.888 79.428 190.08 ;
    END
  END s0__ts[25]
  PIN s0__ts[260]
    DIRECTION OUTPUT ;
    USE SIGNAL ;
    PORT
      LAYER M5 ;
        RECT  132.828 189.888 132.852 190.08 ;
    END
  END s0__ts[260]
  PIN s0__ts[261]
    DIRECTION OUTPUT ;
    USE SIGNAL ;
    PORT
      LAYER M5 ;
        RECT  133.068 189.888 133.092 190.08 ;
    END
  END s0__ts[261]
  PIN s0__ts[262]
    DIRECTION OUTPUT ;
    USE SIGNAL ;
    PORT
      LAYER M5 ;
        RECT  133.308 189.888 133.332 190.08 ;
    END
  END s0__ts[262]
  PIN s0__ts[263]
    DIRECTION OUTPUT ;
    USE SIGNAL ;
    PORT
      LAYER M5 ;
        RECT  133.548 189.888 133.572 190.08 ;
    END
  END s0__ts[263]
  PIN s0__ts[264]
    DIRECTION OUTPUT ;
    USE SIGNAL ;
    PORT
      LAYER M5 ;
        RECT  133.74 189.888 133.764 190.08 ;
    END
  END s0__ts[264]
  PIN s0__ts[265]
    DIRECTION OUTPUT ;
    USE SIGNAL ;
    PORT
      LAYER M5 ;
        RECT  133.98 189.888 134.004 190.08 ;
    END
  END s0__ts[265]
  PIN s0__ts[266]
    DIRECTION OUTPUT ;
    USE SIGNAL ;
    PORT
      LAYER M5 ;
        RECT  134.22 189.888 134.244 190.08 ;
    END
  END s0__ts[266]
  PIN s0__ts[267]
    DIRECTION OUTPUT ;
    USE SIGNAL ;
    PORT
      LAYER M5 ;
        RECT  134.46 189.888 134.484 190.08 ;
    END
  END s0__ts[267]
  PIN s0__ts[268]
    DIRECTION OUTPUT ;
    USE SIGNAL ;
    PORT
      LAYER M5 ;
        RECT  134.652 189.888 134.676 190.08 ;
    END
  END s0__ts[268]
  PIN s0__ts[269]
    DIRECTION OUTPUT ;
    USE SIGNAL ;
    PORT
      LAYER M5 ;
        RECT  134.892 189.888 134.916 190.08 ;
    END
  END s0__ts[269]
  PIN s0__ts[26]
    DIRECTION OUTPUT ;
    USE SIGNAL ;
    PORT
      LAYER M5 ;
        RECT  79.596 189.888 79.62 190.08 ;
    END
  END s0__ts[26]
  PIN s0__ts[270]
    DIRECTION OUTPUT ;
    USE SIGNAL ;
    PORT
      LAYER M5 ;
        RECT  135.132 189.888 135.156 190.08 ;
    END
  END s0__ts[270]
  PIN s0__ts[271]
    DIRECTION OUTPUT ;
    USE SIGNAL ;
    PORT
      LAYER M5 ;
        RECT  135.372 189.888 135.396 190.08 ;
    END
  END s0__ts[271]
  PIN s0__ts[272]
    DIRECTION OUTPUT ;
    USE SIGNAL ;
    PORT
      LAYER M5 ;
        RECT  135.564 189.888 135.588 190.08 ;
    END
  END s0__ts[272]
  PIN s0__ts[273]
    DIRECTION OUTPUT ;
    USE SIGNAL ;
    PORT
      LAYER M5 ;
        RECT  135.804 189.888 135.828 190.08 ;
    END
  END s0__ts[273]
  PIN s0__ts[274]
    DIRECTION OUTPUT ;
    USE SIGNAL ;
    PORT
      LAYER M5 ;
        RECT  136.044 189.888 136.068 190.08 ;
    END
  END s0__ts[274]
  PIN s0__ts[275]
    DIRECTION OUTPUT ;
    USE SIGNAL ;
    PORT
      LAYER M5 ;
        RECT  136.284 189.888 136.308 190.08 ;
    END
  END s0__ts[275]
  PIN s0__ts[276]
    DIRECTION OUTPUT ;
    USE SIGNAL ;
    PORT
      LAYER M5 ;
        RECT  136.476 189.888 136.5 190.08 ;
    END
  END s0__ts[276]
  PIN s0__ts[277]
    DIRECTION OUTPUT ;
    USE SIGNAL ;
    PORT
      LAYER M5 ;
        RECT  136.716 189.888 136.74 190.08 ;
    END
  END s0__ts[277]
  PIN s0__ts[278]
    DIRECTION OUTPUT ;
    USE SIGNAL ;
    PORT
      LAYER M5 ;
        RECT  136.956 189.888 136.98 190.08 ;
    END
  END s0__ts[278]
  PIN s0__ts[279]
    DIRECTION OUTPUT ;
    USE SIGNAL ;
    PORT
      LAYER M5 ;
        RECT  137.196 189.888 137.22 190.08 ;
    END
  END s0__ts[279]
  PIN s0__ts[27]
    DIRECTION OUTPUT ;
    USE SIGNAL ;
    PORT
      LAYER M5 ;
        RECT  79.836 189.888 79.86 190.08 ;
    END
  END s0__ts[27]
  PIN s0__ts[280]
    DIRECTION OUTPUT ;
    USE SIGNAL ;
    PORT
      LAYER M5 ;
        RECT  137.388 189.888 137.412 190.08 ;
    END
  END s0__ts[280]
  PIN s0__ts[281]
    DIRECTION OUTPUT ;
    USE SIGNAL ;
    PORT
      LAYER M5 ;
        RECT  137.628 189.888 137.652 190.08 ;
    END
  END s0__ts[281]
  PIN s0__ts[282]
    DIRECTION OUTPUT ;
    USE SIGNAL ;
    PORT
      LAYER M5 ;
        RECT  137.868 189.888 137.892 190.08 ;
    END
  END s0__ts[282]
  PIN s0__ts[283]
    DIRECTION OUTPUT ;
    USE SIGNAL ;
    PORT
      LAYER M5 ;
        RECT  138.06 189.888 138.084 190.08 ;
    END
  END s0__ts[283]
  PIN s0__ts[284]
    DIRECTION OUTPUT ;
    USE SIGNAL ;
    PORT
      LAYER M5 ;
        RECT  138.3 189.888 138.324 190.08 ;
    END
  END s0__ts[284]
  PIN s0__ts[285]
    DIRECTION OUTPUT ;
    USE SIGNAL ;
    PORT
      LAYER M5 ;
        RECT  138.54 189.888 138.564 190.08 ;
    END
  END s0__ts[285]
  PIN s0__ts[286]
    DIRECTION OUTPUT ;
    USE SIGNAL ;
    PORT
      LAYER M5 ;
        RECT  138.78 189.888 138.804 190.08 ;
    END
  END s0__ts[286]
  PIN s0__ts[287]
    DIRECTION OUTPUT ;
    USE SIGNAL ;
    PORT
      LAYER M5 ;
        RECT  138.972 189.888 138.996 190.08 ;
    END
  END s0__ts[287]
  PIN s0__ts[288]
    DIRECTION OUTPUT ;
    USE SIGNAL ;
    PORT
      LAYER M5 ;
        RECT  139.212 189.888 139.236 190.08 ;
    END
  END s0__ts[288]
  PIN s0__ts[289]
    DIRECTION OUTPUT ;
    USE SIGNAL ;
    PORT
      LAYER M5 ;
        RECT  139.452 189.888 139.476 190.08 ;
    END
  END s0__ts[289]
  PIN s0__ts[28]
    DIRECTION OUTPUT ;
    USE SIGNAL ;
    PORT
      LAYER M5 ;
        RECT  80.076 189.888 80.1 190.08 ;
    END
  END s0__ts[28]
  PIN s0__ts[290]
    DIRECTION OUTPUT ;
    USE SIGNAL ;
    PORT
      LAYER M5 ;
        RECT  139.692 189.888 139.716 190.08 ;
    END
  END s0__ts[290]
  PIN s0__ts[291]
    DIRECTION OUTPUT ;
    USE SIGNAL ;
    PORT
      LAYER M5 ;
        RECT  139.884 189.888 139.908 190.08 ;
    END
  END s0__ts[291]
  PIN s0__ts[292]
    DIRECTION OUTPUT ;
    USE SIGNAL ;
    PORT
      LAYER M5 ;
        RECT  140.124 189.888 140.148 190.08 ;
    END
  END s0__ts[292]
  PIN s0__ts[293]
    DIRECTION OUTPUT ;
    USE SIGNAL ;
    PORT
      LAYER M5 ;
        RECT  140.364 189.888 140.388 190.08 ;
    END
  END s0__ts[293]
  PIN s0__ts[294]
    DIRECTION OUTPUT ;
    USE SIGNAL ;
    PORT
      LAYER M5 ;
        RECT  140.604 189.888 140.628 190.08 ;
    END
  END s0__ts[294]
  PIN s0__ts[295]
    DIRECTION OUTPUT ;
    USE SIGNAL ;
    PORT
      LAYER M5 ;
        RECT  140.796 189.888 140.82 190.08 ;
    END
  END s0__ts[295]
  PIN s0__ts[296]
    DIRECTION OUTPUT ;
    USE SIGNAL ;
    PORT
      LAYER M5 ;
        RECT  141.036 189.888 141.06 190.08 ;
    END
  END s0__ts[296]
  PIN s0__ts[297]
    DIRECTION OUTPUT ;
    USE SIGNAL ;
    PORT
      LAYER M5 ;
        RECT  141.276 189.888 141.3 190.08 ;
    END
  END s0__ts[297]
  PIN s0__ts[298]
    DIRECTION OUTPUT ;
    USE SIGNAL ;
    PORT
      LAYER M5 ;
        RECT  141.516 189.888 141.54 190.08 ;
    END
  END s0__ts[298]
  PIN s0__ts[299]
    DIRECTION OUTPUT ;
    USE SIGNAL ;
    PORT
      LAYER M5 ;
        RECT  141.708 189.888 141.732 190.08 ;
    END
  END s0__ts[299]
  PIN s0__ts[29]
    DIRECTION OUTPUT ;
    USE SIGNAL ;
    PORT
      LAYER M5 ;
        RECT  80.316 189.888 80.34 190.08 ;
    END
  END s0__ts[29]
  PIN s0__ts[2]
    DIRECTION OUTPUT ;
    USE SIGNAL ;
    PORT
      LAYER M5 ;
        RECT  74.172 189.888 74.196 190.08 ;
    END
  END s0__ts[2]
  PIN s0__ts[300]
    DIRECTION OUTPUT ;
    USE SIGNAL ;
    PORT
      LAYER M5 ;
        RECT  141.948 189.888 141.972 190.08 ;
    END
  END s0__ts[300]
  PIN s0__ts[301]
    DIRECTION OUTPUT ;
    USE SIGNAL ;
    PORT
      LAYER M5 ;
        RECT  142.188 189.888 142.212 190.08 ;
    END
  END s0__ts[301]
  PIN s0__ts[302]
    DIRECTION OUTPUT ;
    USE SIGNAL ;
    PORT
      LAYER M5 ;
        RECT  142.428 189.888 142.452 190.08 ;
    END
  END s0__ts[302]
  PIN s0__ts[303]
    DIRECTION OUTPUT ;
    USE SIGNAL ;
    PORT
      LAYER M5 ;
        RECT  142.62 189.888 142.644 190.08 ;
    END
  END s0__ts[303]
  PIN s0__ts[304]
    DIRECTION OUTPUT ;
    USE SIGNAL ;
    PORT
      LAYER M5 ;
        RECT  142.86 189.888 142.884 190.08 ;
    END
  END s0__ts[304]
  PIN s0__ts[305]
    DIRECTION OUTPUT ;
    USE SIGNAL ;
    PORT
      LAYER M5 ;
        RECT  143.1 189.888 143.124 190.08 ;
    END
  END s0__ts[305]
  PIN s0__ts[306]
    DIRECTION OUTPUT ;
    USE SIGNAL ;
    PORT
      LAYER M5 ;
        RECT  143.292 189.888 143.316 190.08 ;
    END
  END s0__ts[306]
  PIN s0__ts[307]
    DIRECTION OUTPUT ;
    USE SIGNAL ;
    PORT
      LAYER M5 ;
        RECT  143.532 189.888 143.556 190.08 ;
    END
  END s0__ts[307]
  PIN s0__ts[308]
    DIRECTION OUTPUT ;
    USE SIGNAL ;
    PORT
      LAYER M5 ;
        RECT  143.772 189.888 143.796 190.08 ;
    END
  END s0__ts[308]
  PIN s0__ts[309]
    DIRECTION OUTPUT ;
    USE SIGNAL ;
    PORT
      LAYER M5 ;
        RECT  144.012 189.888 144.036 190.08 ;
    END
  END s0__ts[309]
  PIN s0__ts[30]
    DIRECTION OUTPUT ;
    USE SIGNAL ;
    PORT
      LAYER M5 ;
        RECT  80.508 189.888 80.532 190.08 ;
    END
  END s0__ts[30]
  PIN s0__ts[310]
    DIRECTION OUTPUT ;
    USE SIGNAL ;
    PORT
      LAYER M5 ;
        RECT  144.204 189.888 144.228 190.08 ;
    END
  END s0__ts[310]
  PIN s0__ts[311]
    DIRECTION OUTPUT ;
    USE SIGNAL ;
    PORT
      LAYER M5 ;
        RECT  144.444 189.888 144.468 190.08 ;
    END
  END s0__ts[311]
  PIN s0__ts[312]
    DIRECTION OUTPUT ;
    USE SIGNAL ;
    PORT
      LAYER M5 ;
        RECT  144.684 189.888 144.708 190.08 ;
    END
  END s0__ts[312]
  PIN s0__ts[313]
    DIRECTION OUTPUT ;
    USE SIGNAL ;
    PORT
      LAYER M5 ;
        RECT  144.924 189.888 144.948 190.08 ;
    END
  END s0__ts[313]
  PIN s0__ts[314]
    DIRECTION OUTPUT ;
    USE SIGNAL ;
    PORT
      LAYER M5 ;
        RECT  145.116 189.888 145.14 190.08 ;
    END
  END s0__ts[314]
  PIN s0__ts[315]
    DIRECTION OUTPUT ;
    USE SIGNAL ;
    PORT
      LAYER M5 ;
        RECT  145.356 189.888 145.38 190.08 ;
    END
  END s0__ts[315]
  PIN s0__ts[316]
    DIRECTION OUTPUT ;
    USE SIGNAL ;
    PORT
      LAYER M5 ;
        RECT  145.596 189.888 145.62 190.08 ;
    END
  END s0__ts[316]
  PIN s0__ts[317]
    DIRECTION OUTPUT ;
    USE SIGNAL ;
    PORT
      LAYER M5 ;
        RECT  145.836 189.888 145.86 190.08 ;
    END
  END s0__ts[317]
  PIN s0__ts[318]
    DIRECTION OUTPUT ;
    USE SIGNAL ;
    PORT
      LAYER M5 ;
        RECT  146.028 189.888 146.052 190.08 ;
    END
  END s0__ts[318]
  PIN s0__ts[319]
    DIRECTION OUTPUT ;
    USE SIGNAL ;
    PORT
      LAYER M5 ;
        RECT  146.268 189.888 146.292 190.08 ;
    END
  END s0__ts[319]
  PIN s0__ts[31]
    DIRECTION OUTPUT ;
    USE SIGNAL ;
    PORT
      LAYER M5 ;
        RECT  80.748 189.888 80.772 190.08 ;
    END
  END s0__ts[31]
  PIN s0__ts[320]
    DIRECTION OUTPUT ;
    USE SIGNAL ;
    PORT
      LAYER M5 ;
        RECT  146.508 189.888 146.532 190.08 ;
    END
  END s0__ts[320]
  PIN s0__ts[321]
    DIRECTION OUTPUT ;
    USE SIGNAL ;
    PORT
      LAYER M5 ;
        RECT  146.748 189.888 146.772 190.08 ;
    END
  END s0__ts[321]
  PIN s0__ts[322]
    DIRECTION OUTPUT ;
    USE SIGNAL ;
    PORT
      LAYER M5 ;
        RECT  146.94 189.888 146.964 190.08 ;
    END
  END s0__ts[322]
  PIN s0__ts[323]
    DIRECTION OUTPUT ;
    USE SIGNAL ;
    PORT
      LAYER M5 ;
        RECT  147.18 189.888 147.204 190.08 ;
    END
  END s0__ts[323]
  PIN s0__ts[324]
    DIRECTION OUTPUT ;
    USE SIGNAL ;
    PORT
      LAYER M5 ;
        RECT  147.42 189.888 147.444 190.08 ;
    END
  END s0__ts[324]
  PIN s0__ts[325]
    DIRECTION OUTPUT ;
    USE SIGNAL ;
    PORT
      LAYER M5 ;
        RECT  147.66 189.888 147.684 190.08 ;
    END
  END s0__ts[325]
  PIN s0__ts[326]
    DIRECTION OUTPUT ;
    USE SIGNAL ;
    PORT
      LAYER M5 ;
        RECT  147.852 189.888 147.876 190.08 ;
    END
  END s0__ts[326]
  PIN s0__ts[327]
    DIRECTION OUTPUT ;
    USE SIGNAL ;
    PORT
      LAYER M5 ;
        RECT  148.092 189.888 148.116 190.08 ;
    END
  END s0__ts[327]
  PIN s0__ts[328]
    DIRECTION OUTPUT ;
    USE SIGNAL ;
    PORT
      LAYER M5 ;
        RECT  148.332 189.888 148.356 190.08 ;
    END
  END s0__ts[328]
  PIN s0__ts[329]
    DIRECTION OUTPUT ;
    USE SIGNAL ;
    PORT
      LAYER M5 ;
        RECT  148.572 189.888 148.596 190.08 ;
    END
  END s0__ts[329]
  PIN s0__ts[32]
    DIRECTION OUTPUT ;
    USE SIGNAL ;
    PORT
      LAYER M5 ;
        RECT  80.988 189.888 81.012 190.08 ;
    END
  END s0__ts[32]
  PIN s0__ts[330]
    DIRECTION OUTPUT ;
    USE SIGNAL ;
    PORT
      LAYER M5 ;
        RECT  148.764 189.888 148.788 190.08 ;
    END
  END s0__ts[330]
  PIN s0__ts[331]
    DIRECTION OUTPUT ;
    USE SIGNAL ;
    PORT
      LAYER M5 ;
        RECT  149.004 189.888 149.028 190.08 ;
    END
  END s0__ts[331]
  PIN s0__ts[332]
    DIRECTION OUTPUT ;
    USE SIGNAL ;
    PORT
      LAYER M5 ;
        RECT  149.244 189.888 149.268 190.08 ;
    END
  END s0__ts[332]
  PIN s0__ts[333]
    DIRECTION OUTPUT ;
    USE SIGNAL ;
    PORT
      LAYER M5 ;
        RECT  149.436 189.888 149.46 190.08 ;
    END
  END s0__ts[333]
  PIN s0__ts[334]
    DIRECTION OUTPUT ;
    USE SIGNAL ;
    PORT
      LAYER M5 ;
        RECT  149.676 189.888 149.7 190.08 ;
    END
  END s0__ts[334]
  PIN s0__ts[335]
    DIRECTION OUTPUT ;
    USE SIGNAL ;
    PORT
      LAYER M5 ;
        RECT  149.916 189.888 149.94 190.08 ;
    END
  END s0__ts[335]
  PIN s0__ts[336]
    DIRECTION OUTPUT ;
    USE SIGNAL ;
    PORT
      LAYER M5 ;
        RECT  150.156 189.888 150.18 190.08 ;
    END
  END s0__ts[336]
  PIN s0__ts[337]
    DIRECTION OUTPUT ;
    USE SIGNAL ;
    PORT
      LAYER M5 ;
        RECT  150.348 189.888 150.372 190.08 ;
    END
  END s0__ts[337]
  PIN s0__ts[338]
    DIRECTION OUTPUT ;
    USE SIGNAL ;
    PORT
      LAYER M5 ;
        RECT  150.588 189.888 150.612 190.08 ;
    END
  END s0__ts[338]
  PIN s0__ts[339]
    DIRECTION OUTPUT ;
    USE SIGNAL ;
    PORT
      LAYER M5 ;
        RECT  150.828 189.888 150.852 190.08 ;
    END
  END s0__ts[339]
  PIN s0__ts[33]
    DIRECTION OUTPUT ;
    USE SIGNAL ;
    PORT
      LAYER M5 ;
        RECT  81.228 189.888 81.252 190.08 ;
    END
  END s0__ts[33]
  PIN s0__ts[340]
    DIRECTION OUTPUT ;
    USE SIGNAL ;
    PORT
      LAYER M5 ;
        RECT  151.068 189.888 151.092 190.08 ;
    END
  END s0__ts[340]
  PIN s0__ts[341]
    DIRECTION OUTPUT ;
    USE SIGNAL ;
    PORT
      LAYER M5 ;
        RECT  151.26 189.888 151.284 190.08 ;
    END
  END s0__ts[341]
  PIN s0__ts[342]
    DIRECTION OUTPUT ;
    USE SIGNAL ;
    PORT
      LAYER M5 ;
        RECT  151.5 189.888 151.524 190.08 ;
    END
  END s0__ts[342]
  PIN s0__ts[343]
    DIRECTION OUTPUT ;
    USE SIGNAL ;
    PORT
      LAYER M5 ;
        RECT  151.74 189.888 151.764 190.08 ;
    END
  END s0__ts[343]
  PIN s0__ts[344]
    DIRECTION OUTPUT ;
    USE SIGNAL ;
    PORT
      LAYER M5 ;
        RECT  151.98 189.888 152.004 190.08 ;
    END
  END s0__ts[344]
  PIN s0__ts[345]
    DIRECTION OUTPUT ;
    USE SIGNAL ;
    PORT
      LAYER M5 ;
        RECT  152.172 189.888 152.196 190.08 ;
    END
  END s0__ts[345]
  PIN s0__ts[346]
    DIRECTION OUTPUT ;
    USE SIGNAL ;
    PORT
      LAYER M5 ;
        RECT  152.412 189.888 152.436 190.08 ;
    END
  END s0__ts[346]
  PIN s0__ts[347]
    DIRECTION OUTPUT ;
    USE SIGNAL ;
    PORT
      LAYER M5 ;
        RECT  152.652 189.888 152.676 190.08 ;
    END
  END s0__ts[347]
  PIN s0__ts[348]
    DIRECTION OUTPUT ;
    USE SIGNAL ;
    PORT
      LAYER M5 ;
        RECT  152.892 189.888 152.916 190.08 ;
    END
  END s0__ts[348]
  PIN s0__ts[349]
    DIRECTION OUTPUT ;
    USE SIGNAL ;
    PORT
      LAYER M5 ;
        RECT  153.084 189.888 153.108 190.08 ;
    END
  END s0__ts[349]
  PIN s0__ts[34]
    DIRECTION OUTPUT ;
    USE SIGNAL ;
    PORT
      LAYER M5 ;
        RECT  81.42 189.888 81.444 190.08 ;
    END
  END s0__ts[34]
  PIN s0__ts[350]
    DIRECTION OUTPUT ;
    USE SIGNAL ;
    PORT
      LAYER M5 ;
        RECT  153.324 189.888 153.348 190.08 ;
    END
  END s0__ts[350]
  PIN s0__ts[351]
    DIRECTION OUTPUT ;
    USE SIGNAL ;
    PORT
      LAYER M5 ;
        RECT  153.564 189.888 153.588 190.08 ;
    END
  END s0__ts[351]
  PIN s0__ts[352]
    DIRECTION OUTPUT ;
    USE SIGNAL ;
    PORT
      LAYER M5 ;
        RECT  153.804 189.888 153.828 190.08 ;
    END
  END s0__ts[352]
  PIN s0__ts[353]
    DIRECTION OUTPUT ;
    USE SIGNAL ;
    PORT
      LAYER M5 ;
        RECT  153.996 189.888 154.02 190.08 ;
    END
  END s0__ts[353]
  PIN s0__ts[354]
    DIRECTION OUTPUT ;
    USE SIGNAL ;
    PORT
      LAYER M5 ;
        RECT  154.236 189.888 154.26 190.08 ;
    END
  END s0__ts[354]
  PIN s0__ts[355]
    DIRECTION OUTPUT ;
    USE SIGNAL ;
    PORT
      LAYER M5 ;
        RECT  154.476 189.888 154.5 190.08 ;
    END
  END s0__ts[355]
  PIN s0__ts[356]
    DIRECTION OUTPUT ;
    USE SIGNAL ;
    PORT
      LAYER M5 ;
        RECT  154.668 189.888 154.692 190.08 ;
    END
  END s0__ts[356]
  PIN s0__ts[357]
    DIRECTION OUTPUT ;
    USE SIGNAL ;
    PORT
      LAYER M5 ;
        RECT  154.908 189.888 154.932 190.08 ;
    END
  END s0__ts[357]
  PIN s0__ts[358]
    DIRECTION OUTPUT ;
    USE SIGNAL ;
    PORT
      LAYER M5 ;
        RECT  155.148 189.888 155.172 190.08 ;
    END
  END s0__ts[358]
  PIN s0__ts[359]
    DIRECTION OUTPUT ;
    USE SIGNAL ;
    PORT
      LAYER M5 ;
        RECT  155.388 189.888 155.412 190.08 ;
    END
  END s0__ts[359]
  PIN s0__ts[35]
    DIRECTION OUTPUT ;
    USE SIGNAL ;
    PORT
      LAYER M5 ;
        RECT  81.66 189.888 81.684 190.08 ;
    END
  END s0__ts[35]
  PIN s0__ts[360]
    DIRECTION OUTPUT ;
    USE SIGNAL ;
    PORT
      LAYER M5 ;
        RECT  155.58 189.888 155.604 190.08 ;
    END
  END s0__ts[360]
  PIN s0__ts[361]
    DIRECTION OUTPUT ;
    USE SIGNAL ;
    PORT
      LAYER M5 ;
        RECT  155.82 189.888 155.844 190.08 ;
    END
  END s0__ts[361]
  PIN s0__ts[362]
    DIRECTION OUTPUT ;
    USE SIGNAL ;
    PORT
      LAYER M5 ;
        RECT  156.06 189.888 156.084 190.08 ;
    END
  END s0__ts[362]
  PIN s0__ts[363]
    DIRECTION OUTPUT ;
    USE SIGNAL ;
    PORT
      LAYER M5 ;
        RECT  156.3 189.888 156.324 190.08 ;
    END
  END s0__ts[363]
  PIN s0__ts[364]
    DIRECTION OUTPUT ;
    USE SIGNAL ;
    PORT
      LAYER M5 ;
        RECT  156.492 189.888 156.516 190.08 ;
    END
  END s0__ts[364]
  PIN s0__ts[365]
    DIRECTION OUTPUT ;
    USE SIGNAL ;
    PORT
      LAYER M5 ;
        RECT  156.732 189.888 156.756 190.08 ;
    END
  END s0__ts[365]
  PIN s0__ts[366]
    DIRECTION OUTPUT ;
    USE SIGNAL ;
    PORT
      LAYER M5 ;
        RECT  156.972 189.888 156.996 190.08 ;
    END
  END s0__ts[366]
  PIN s0__ts[367]
    DIRECTION OUTPUT ;
    USE SIGNAL ;
    PORT
      LAYER M5 ;
        RECT  157.212 189.888 157.236 190.08 ;
    END
  END s0__ts[367]
  PIN s0__ts[368]
    DIRECTION OUTPUT ;
    USE SIGNAL ;
    PORT
      LAYER M5 ;
        RECT  157.404 189.888 157.428 190.08 ;
    END
  END s0__ts[368]
  PIN s0__ts[369]
    DIRECTION OUTPUT ;
    USE SIGNAL ;
    PORT
      LAYER M5 ;
        RECT  157.644 189.888 157.668 190.08 ;
    END
  END s0__ts[369]
  PIN s0__ts[36]
    DIRECTION OUTPUT ;
    USE SIGNAL ;
    PORT
      LAYER M5 ;
        RECT  81.9 189.888 81.924 190.08 ;
    END
  END s0__ts[36]
  PIN s0__ts[370]
    DIRECTION OUTPUT ;
    USE SIGNAL ;
    PORT
      LAYER M5 ;
        RECT  157.884 189.888 157.908 190.08 ;
    END
  END s0__ts[370]
  PIN s0__ts[371]
    DIRECTION OUTPUT ;
    USE SIGNAL ;
    PORT
      LAYER M5 ;
        RECT  158.124 189.888 158.148 190.08 ;
    END
  END s0__ts[371]
  PIN s0__ts[372]
    DIRECTION OUTPUT ;
    USE SIGNAL ;
    PORT
      LAYER M5 ;
        RECT  158.316 189.888 158.34 190.08 ;
    END
  END s0__ts[372]
  PIN s0__ts[373]
    DIRECTION OUTPUT ;
    USE SIGNAL ;
    PORT
      LAYER M5 ;
        RECT  158.556 189.888 158.58 190.08 ;
    END
  END s0__ts[373]
  PIN s0__ts[374]
    DIRECTION OUTPUT ;
    USE SIGNAL ;
    PORT
      LAYER M5 ;
        RECT  158.796 189.888 158.82 190.08 ;
    END
  END s0__ts[374]
  PIN s0__ts[375]
    DIRECTION OUTPUT ;
    USE SIGNAL ;
    PORT
      LAYER M5 ;
        RECT  159.036 189.888 159.06 190.08 ;
    END
  END s0__ts[375]
  PIN s0__ts[376]
    DIRECTION OUTPUT ;
    USE SIGNAL ;
    PORT
      LAYER M5 ;
        RECT  159.228 189.888 159.252 190.08 ;
    END
  END s0__ts[376]
  PIN s0__ts[377]
    DIRECTION OUTPUT ;
    USE SIGNAL ;
    PORT
      LAYER M5 ;
        RECT  159.468 189.888 159.492 190.08 ;
    END
  END s0__ts[377]
  PIN s0__ts[378]
    DIRECTION OUTPUT ;
    USE SIGNAL ;
    PORT
      LAYER M5 ;
        RECT  159.708 189.888 159.732 190.08 ;
    END
  END s0__ts[378]
  PIN s0__ts[379]
    DIRECTION OUTPUT ;
    USE SIGNAL ;
    PORT
      LAYER M5 ;
        RECT  159.9 189.888 159.924 190.08 ;
    END
  END s0__ts[379]
  PIN s0__ts[37]
    DIRECTION OUTPUT ;
    USE SIGNAL ;
    PORT
      LAYER M5 ;
        RECT  82.14 189.888 82.164 190.08 ;
    END
  END s0__ts[37]
  PIN s0__ts[380]
    DIRECTION OUTPUT ;
    USE SIGNAL ;
    PORT
      LAYER M5 ;
        RECT  160.14 189.888 160.164 190.08 ;
    END
  END s0__ts[380]
  PIN s0__ts[381]
    DIRECTION OUTPUT ;
    USE SIGNAL ;
    PORT
      LAYER M5 ;
        RECT  160.38 189.888 160.404 190.08 ;
    END
  END s0__ts[381]
  PIN s0__ts[382]
    DIRECTION OUTPUT ;
    USE SIGNAL ;
    PORT
      LAYER M5 ;
        RECT  160.62 189.888 160.644 190.08 ;
    END
  END s0__ts[382]
  PIN s0__ts[383]
    DIRECTION OUTPUT ;
    USE SIGNAL ;
    PORT
      LAYER M5 ;
        RECT  160.812 189.888 160.836 190.08 ;
    END
  END s0__ts[383]
  PIN s0__ts[384]
    DIRECTION OUTPUT ;
    USE SIGNAL ;
    PORT
      LAYER M5 ;
        RECT  161.052 189.888 161.076 190.08 ;
    END
  END s0__ts[384]
  PIN s0__ts[385]
    DIRECTION OUTPUT ;
    USE SIGNAL ;
    PORT
      LAYER M5 ;
        RECT  161.292 189.888 161.316 190.08 ;
    END
  END s0__ts[385]
  PIN s0__ts[386]
    DIRECTION OUTPUT ;
    USE SIGNAL ;
    PORT
      LAYER M5 ;
        RECT  161.532 189.888 161.556 190.08 ;
    END
  END s0__ts[386]
  PIN s0__ts[387]
    DIRECTION OUTPUT ;
    USE SIGNAL ;
    PORT
      LAYER M5 ;
        RECT  161.724 189.888 161.748 190.08 ;
    END
  END s0__ts[387]
  PIN s0__ts[388]
    DIRECTION OUTPUT ;
    USE SIGNAL ;
    PORT
      LAYER M5 ;
        RECT  161.964 189.888 161.988 190.08 ;
    END
  END s0__ts[388]
  PIN s0__ts[389]
    DIRECTION OUTPUT ;
    USE SIGNAL ;
    PORT
      LAYER M5 ;
        RECT  162.204 189.888 162.228 190.08 ;
    END
  END s0__ts[389]
  PIN s0__ts[38]
    DIRECTION OUTPUT ;
    USE SIGNAL ;
    PORT
      LAYER M5 ;
        RECT  82.332 189.888 82.356 190.08 ;
    END
  END s0__ts[38]
  PIN s0__ts[390]
    DIRECTION OUTPUT ;
    USE SIGNAL ;
    PORT
      LAYER M5 ;
        RECT  162.444 189.888 162.468 190.08 ;
    END
  END s0__ts[390]
  PIN s0__ts[391]
    DIRECTION OUTPUT ;
    USE SIGNAL ;
    PORT
      LAYER M5 ;
        RECT  162.636 189.888 162.66 190.08 ;
    END
  END s0__ts[391]
  PIN s0__ts[392]
    DIRECTION OUTPUT ;
    USE SIGNAL ;
    PORT
      LAYER M5 ;
        RECT  162.876 189.888 162.9 190.08 ;
    END
  END s0__ts[392]
  PIN s0__ts[393]
    DIRECTION OUTPUT ;
    USE SIGNAL ;
    PORT
      LAYER M5 ;
        RECT  163.116 189.888 163.14 190.08 ;
    END
  END s0__ts[393]
  PIN s0__ts[394]
    DIRECTION OUTPUT ;
    USE SIGNAL ;
    PORT
      LAYER M5 ;
        RECT  163.356 189.888 163.38 190.08 ;
    END
  END s0__ts[394]
  PIN s0__ts[395]
    DIRECTION OUTPUT ;
    USE SIGNAL ;
    PORT
      LAYER M5 ;
        RECT  163.548 189.888 163.572 190.08 ;
    END
  END s0__ts[395]
  PIN s0__ts[396]
    DIRECTION OUTPUT ;
    USE SIGNAL ;
    PORT
      LAYER M5 ;
        RECT  163.788 189.888 163.812 190.08 ;
    END
  END s0__ts[396]
  PIN s0__ts[397]
    DIRECTION OUTPUT ;
    USE SIGNAL ;
    PORT
      LAYER M5 ;
        RECT  164.028 189.888 164.052 190.08 ;
    END
  END s0__ts[397]
  PIN s0__ts[398]
    DIRECTION OUTPUT ;
    USE SIGNAL ;
    PORT
      LAYER M5 ;
        RECT  164.268 189.888 164.292 190.08 ;
    END
  END s0__ts[398]
  PIN s0__ts[399]
    DIRECTION OUTPUT ;
    USE SIGNAL ;
    PORT
      LAYER M5 ;
        RECT  164.46 189.888 164.484 190.08 ;
    END
  END s0__ts[399]
  PIN s0__ts[39]
    DIRECTION OUTPUT ;
    USE SIGNAL ;
    PORT
      LAYER M5 ;
        RECT  82.572 189.888 82.596 190.08 ;
    END
  END s0__ts[39]
  PIN s0__ts[3]
    DIRECTION OUTPUT ;
    USE SIGNAL ;
    PORT
      LAYER M5 ;
        RECT  74.364 189.888 74.388 190.08 ;
    END
  END s0__ts[3]
  PIN s0__ts[400]
    DIRECTION OUTPUT ;
    USE SIGNAL ;
    PORT
      LAYER M5 ;
        RECT  164.7 189.888 164.724 190.08 ;
    END
  END s0__ts[400]
  PIN s0__ts[401]
    DIRECTION OUTPUT ;
    USE SIGNAL ;
    PORT
      LAYER M5 ;
        RECT  164.94 189.888 164.964 190.08 ;
    END
  END s0__ts[401]
  PIN s0__ts[402]
    DIRECTION OUTPUT ;
    USE SIGNAL ;
    PORT
      LAYER M5 ;
        RECT  165.18 189.888 165.204 190.08 ;
    END
  END s0__ts[402]
  PIN s0__ts[403]
    DIRECTION OUTPUT ;
    USE SIGNAL ;
    PORT
      LAYER M5 ;
        RECT  165.372 189.888 165.396 190.08 ;
    END
  END s0__ts[403]
  PIN s0__ts[404]
    DIRECTION OUTPUT ;
    USE SIGNAL ;
    PORT
      LAYER M5 ;
        RECT  165.612 189.888 165.636 190.08 ;
    END
  END s0__ts[404]
  PIN s0__ts[405]
    DIRECTION OUTPUT ;
    USE SIGNAL ;
    PORT
      LAYER M5 ;
        RECT  165.852 189.888 165.876 190.08 ;
    END
  END s0__ts[405]
  PIN s0__ts[406]
    DIRECTION OUTPUT ;
    USE SIGNAL ;
    PORT
      LAYER M5 ;
        RECT  166.044 189.888 166.068 190.08 ;
    END
  END s0__ts[406]
  PIN s0__ts[407]
    DIRECTION OUTPUT ;
    USE SIGNAL ;
    PORT
      LAYER M5 ;
        RECT  166.284 189.888 166.308 190.08 ;
    END
  END s0__ts[407]
  PIN s0__ts[408]
    DIRECTION OUTPUT ;
    USE SIGNAL ;
    PORT
      LAYER M5 ;
        RECT  166.524 189.888 166.548 190.08 ;
    END
  END s0__ts[408]
  PIN s0__ts[409]
    DIRECTION OUTPUT ;
    USE SIGNAL ;
    PORT
      LAYER M5 ;
        RECT  166.764 189.888 166.788 190.08 ;
    END
  END s0__ts[409]
  PIN s0__ts[40]
    DIRECTION OUTPUT ;
    USE SIGNAL ;
    PORT
      LAYER M5 ;
        RECT  82.812 189.888 82.836 190.08 ;
    END
  END s0__ts[40]
  PIN s0__ts[410]
    DIRECTION OUTPUT ;
    USE SIGNAL ;
    PORT
      LAYER M5 ;
        RECT  166.956 189.888 166.98 190.08 ;
    END
  END s0__ts[410]
  PIN s0__ts[411]
    DIRECTION OUTPUT ;
    USE SIGNAL ;
    PORT
      LAYER M5 ;
        RECT  167.196 189.888 167.22 190.08 ;
    END
  END s0__ts[411]
  PIN s0__ts[412]
    DIRECTION OUTPUT ;
    USE SIGNAL ;
    PORT
      LAYER M5 ;
        RECT  167.436 189.888 167.46 190.08 ;
    END
  END s0__ts[412]
  PIN s0__ts[413]
    DIRECTION OUTPUT ;
    USE SIGNAL ;
    PORT
      LAYER M5 ;
        RECT  167.676 189.888 167.7 190.08 ;
    END
  END s0__ts[413]
  PIN s0__ts[414]
    DIRECTION OUTPUT ;
    USE SIGNAL ;
    PORT
      LAYER M5 ;
        RECT  167.868 189.888 167.892 190.08 ;
    END
  END s0__ts[414]
  PIN s0__ts[415]
    DIRECTION OUTPUT ;
    USE SIGNAL ;
    PORT
      LAYER M5 ;
        RECT  168.108 189.888 168.132 190.08 ;
    END
  END s0__ts[415]
  PIN s0__ts[416]
    DIRECTION OUTPUT ;
    USE SIGNAL ;
    PORT
      LAYER M5 ;
        RECT  168.348 189.888 168.372 190.08 ;
    END
  END s0__ts[416]
  PIN s0__ts[417]
    DIRECTION OUTPUT ;
    USE SIGNAL ;
    PORT
      LAYER M5 ;
        RECT  168.588 189.888 168.612 190.08 ;
    END
  END s0__ts[417]
  PIN s0__ts[418]
    DIRECTION OUTPUT ;
    USE SIGNAL ;
    PORT
      LAYER M5 ;
        RECT  168.78 189.888 168.804 190.08 ;
    END
  END s0__ts[418]
  PIN s0__ts[419]
    DIRECTION OUTPUT ;
    USE SIGNAL ;
    PORT
      LAYER M5 ;
        RECT  169.02 189.888 169.044 190.08 ;
    END
  END s0__ts[419]
  PIN s0__ts[41]
    DIRECTION OUTPUT ;
    USE SIGNAL ;
    PORT
      LAYER M5 ;
        RECT  83.004 189.888 83.028 190.08 ;
    END
  END s0__ts[41]
  PIN s0__ts[420]
    DIRECTION OUTPUT ;
    USE SIGNAL ;
    PORT
      LAYER M5 ;
        RECT  169.26 189.888 169.284 190.08 ;
    END
  END s0__ts[420]
  PIN s0__ts[421]
    DIRECTION OUTPUT ;
    USE SIGNAL ;
    PORT
      LAYER M5 ;
        RECT  169.5 189.888 169.524 190.08 ;
    END
  END s0__ts[421]
  PIN s0__ts[422]
    DIRECTION OUTPUT ;
    USE SIGNAL ;
    PORT
      LAYER M5 ;
        RECT  169.692 189.888 169.716 190.08 ;
    END
  END s0__ts[422]
  PIN s0__ts[423]
    DIRECTION OUTPUT ;
    USE SIGNAL ;
    PORT
      LAYER M5 ;
        RECT  169.932 189.888 169.956 190.08 ;
    END
  END s0__ts[423]
  PIN s0__ts[424]
    DIRECTION OUTPUT ;
    USE SIGNAL ;
    PORT
      LAYER M5 ;
        RECT  170.172 189.888 170.196 190.08 ;
    END
  END s0__ts[424]
  PIN s0__ts[425]
    DIRECTION OUTPUT ;
    USE SIGNAL ;
    PORT
      LAYER M5 ;
        RECT  170.412 189.888 170.436 190.08 ;
    END
  END s0__ts[425]
  PIN s0__ts[426]
    DIRECTION OUTPUT ;
    USE SIGNAL ;
    PORT
      LAYER M5 ;
        RECT  170.604 189.888 170.628 190.08 ;
    END
  END s0__ts[426]
  PIN s0__ts[427]
    DIRECTION OUTPUT ;
    USE SIGNAL ;
    PORT
      LAYER M5 ;
        RECT  170.844 189.888 170.868 190.08 ;
    END
  END s0__ts[427]
  PIN s0__ts[428]
    DIRECTION OUTPUT ;
    USE SIGNAL ;
    PORT
      LAYER M5 ;
        RECT  171.084 189.888 171.108 190.08 ;
    END
  END s0__ts[428]
  PIN s0__ts[429]
    DIRECTION OUTPUT ;
    USE SIGNAL ;
    PORT
      LAYER M5 ;
        RECT  171.276 189.888 171.3 190.08 ;
    END
  END s0__ts[429]
  PIN s0__ts[42]
    DIRECTION OUTPUT ;
    USE SIGNAL ;
    PORT
      LAYER M5 ;
        RECT  83.244 189.888 83.268 190.08 ;
    END
  END s0__ts[42]
  PIN s0__ts[430]
    DIRECTION OUTPUT ;
    USE SIGNAL ;
    PORT
      LAYER M5 ;
        RECT  171.516 189.888 171.54 190.08 ;
    END
  END s0__ts[430]
  PIN s0__ts[431]
    DIRECTION OUTPUT ;
    USE SIGNAL ;
    PORT
      LAYER M5 ;
        RECT  171.756 189.888 171.78 190.08 ;
    END
  END s0__ts[431]
  PIN s0__ts[432]
    DIRECTION OUTPUT ;
    USE SIGNAL ;
    PORT
      LAYER M5 ;
        RECT  171.996 189.888 172.02 190.08 ;
    END
  END s0__ts[432]
  PIN s0__ts[433]
    DIRECTION OUTPUT ;
    USE SIGNAL ;
    PORT
      LAYER M5 ;
        RECT  172.188 189.888 172.212 190.08 ;
    END
  END s0__ts[433]
  PIN s0__ts[434]
    DIRECTION OUTPUT ;
    USE SIGNAL ;
    PORT
      LAYER M5 ;
        RECT  172.428 189.888 172.452 190.08 ;
    END
  END s0__ts[434]
  PIN s0__ts[435]
    DIRECTION OUTPUT ;
    USE SIGNAL ;
    PORT
      LAYER M5 ;
        RECT  172.668 189.888 172.692 190.08 ;
    END
  END s0__ts[435]
  PIN s0__ts[436]
    DIRECTION OUTPUT ;
    USE SIGNAL ;
    PORT
      LAYER M5 ;
        RECT  172.908 189.888 172.932 190.08 ;
    END
  END s0__ts[436]
  PIN s0__ts[437]
    DIRECTION OUTPUT ;
    USE SIGNAL ;
    PORT
      LAYER M5 ;
        RECT  173.1 189.888 173.124 190.08 ;
    END
  END s0__ts[437]
  PIN s0__ts[438]
    DIRECTION OUTPUT ;
    USE SIGNAL ;
    PORT
      LAYER M5 ;
        RECT  173.34 189.888 173.364 190.08 ;
    END
  END s0__ts[438]
  PIN s0__ts[439]
    DIRECTION OUTPUT ;
    USE SIGNAL ;
    PORT
      LAYER M5 ;
        RECT  173.58 189.888 173.604 190.08 ;
    END
  END s0__ts[439]
  PIN s0__ts[43]
    DIRECTION OUTPUT ;
    USE SIGNAL ;
    PORT
      LAYER M5 ;
        RECT  83.484 189.888 83.508 190.08 ;
    END
  END s0__ts[43]
  PIN s0__ts[440]
    DIRECTION OUTPUT ;
    USE SIGNAL ;
    PORT
      LAYER M5 ;
        RECT  173.82 189.888 173.844 190.08 ;
    END
  END s0__ts[440]
  PIN s0__ts[441]
    DIRECTION OUTPUT ;
    USE SIGNAL ;
    PORT
      LAYER M5 ;
        RECT  174.012 189.888 174.036 190.08 ;
    END
  END s0__ts[441]
  PIN s0__ts[442]
    DIRECTION OUTPUT ;
    USE SIGNAL ;
    PORT
      LAYER M5 ;
        RECT  174.252 189.888 174.276 190.08 ;
    END
  END s0__ts[442]
  PIN s0__ts[443]
    DIRECTION OUTPUT ;
    USE SIGNAL ;
    PORT
      LAYER M5 ;
        RECT  174.492 189.888 174.516 190.08 ;
    END
  END s0__ts[443]
  PIN s0__ts[444]
    DIRECTION OUTPUT ;
    USE SIGNAL ;
    PORT
      LAYER M5 ;
        RECT  174.732 189.888 174.756 190.08 ;
    END
  END s0__ts[444]
  PIN s0__ts[445]
    DIRECTION OUTPUT ;
    USE SIGNAL ;
    PORT
      LAYER M5 ;
        RECT  174.924 189.888 174.948 190.08 ;
    END
  END s0__ts[445]
  PIN s0__ts[446]
    DIRECTION OUTPUT ;
    USE SIGNAL ;
    PORT
      LAYER M5 ;
        RECT  175.164 189.888 175.188 190.08 ;
    END
  END s0__ts[446]
  PIN s0__ts[447]
    DIRECTION OUTPUT ;
    USE SIGNAL ;
    PORT
      LAYER M5 ;
        RECT  175.404 189.888 175.428 190.08 ;
    END
  END s0__ts[447]
  PIN s0__ts[448]
    DIRECTION OUTPUT ;
    USE SIGNAL ;
    PORT
      LAYER M5 ;
        RECT  175.644 189.888 175.668 190.08 ;
    END
  END s0__ts[448]
  PIN s0__ts[449]
    DIRECTION OUTPUT ;
    USE SIGNAL ;
    PORT
      LAYER M5 ;
        RECT  175.836 189.888 175.86 190.08 ;
    END
  END s0__ts[449]
  PIN s0__ts[44]
    DIRECTION OUTPUT ;
    USE SIGNAL ;
    PORT
      LAYER M5 ;
        RECT  83.724 189.888 83.748 190.08 ;
    END
  END s0__ts[44]
  PIN s0__ts[450]
    DIRECTION OUTPUT ;
    USE SIGNAL ;
    PORT
      LAYER M5 ;
        RECT  176.076 189.888 176.1 190.08 ;
    END
  END s0__ts[450]
  PIN s0__ts[451]
    DIRECTION OUTPUT ;
    USE SIGNAL ;
    PORT
      LAYER M5 ;
        RECT  176.316 189.888 176.34 190.08 ;
    END
  END s0__ts[451]
  PIN s0__ts[452]
    DIRECTION OUTPUT ;
    USE SIGNAL ;
    PORT
      LAYER M5 ;
        RECT  176.508 189.888 176.532 190.08 ;
    END
  END s0__ts[452]
  PIN s0__ts[453]
    DIRECTION OUTPUT ;
    USE SIGNAL ;
    PORT
      LAYER M5 ;
        RECT  176.748 189.888 176.772 190.08 ;
    END
  END s0__ts[453]
  PIN s0__ts[454]
    DIRECTION OUTPUT ;
    USE SIGNAL ;
    PORT
      LAYER M5 ;
        RECT  176.988 189.888 177.012 190.08 ;
    END
  END s0__ts[454]
  PIN s0__ts[455]
    DIRECTION OUTPUT ;
    USE SIGNAL ;
    PORT
      LAYER M5 ;
        RECT  177.228 189.888 177.252 190.08 ;
    END
  END s0__ts[455]
  PIN s0__ts[456]
    DIRECTION OUTPUT ;
    USE SIGNAL ;
    PORT
      LAYER M5 ;
        RECT  177.42 189.888 177.444 190.08 ;
    END
  END s0__ts[456]
  PIN s0__ts[457]
    DIRECTION OUTPUT ;
    USE SIGNAL ;
    PORT
      LAYER M5 ;
        RECT  177.66 189.888 177.684 190.08 ;
    END
  END s0__ts[457]
  PIN s0__ts[458]
    DIRECTION OUTPUT ;
    USE SIGNAL ;
    PORT
      LAYER M5 ;
        RECT  177.9 189.888 177.924 190.08 ;
    END
  END s0__ts[458]
  PIN s0__ts[459]
    DIRECTION OUTPUT ;
    USE SIGNAL ;
    PORT
      LAYER M5 ;
        RECT  178.14 189.888 178.164 190.08 ;
    END
  END s0__ts[459]
  PIN s0__ts[45]
    DIRECTION OUTPUT ;
    USE SIGNAL ;
    PORT
      LAYER M5 ;
        RECT  83.916 189.888 83.94 190.08 ;
    END
  END s0__ts[45]
  PIN s0__ts[460]
    DIRECTION OUTPUT ;
    USE SIGNAL ;
    PORT
      LAYER M5 ;
        RECT  178.332 189.888 178.356 190.08 ;
    END
  END s0__ts[460]
  PIN s0__ts[461]
    DIRECTION OUTPUT ;
    USE SIGNAL ;
    PORT
      LAYER M5 ;
        RECT  178.572 189.888 178.596 190.08 ;
    END
  END s0__ts[461]
  PIN s0__ts[462]
    DIRECTION OUTPUT ;
    USE SIGNAL ;
    PORT
      LAYER M5 ;
        RECT  178.812 189.888 178.836 190.08 ;
    END
  END s0__ts[462]
  PIN s0__ts[463]
    DIRECTION OUTPUT ;
    USE SIGNAL ;
    PORT
      LAYER M5 ;
        RECT  179.052 189.888 179.076 190.08 ;
    END
  END s0__ts[463]
  PIN s0__ts[464]
    DIRECTION OUTPUT ;
    USE SIGNAL ;
    PORT
      LAYER M5 ;
        RECT  179.244 189.888 179.268 190.08 ;
    END
  END s0__ts[464]
  PIN s0__ts[465]
    DIRECTION OUTPUT ;
    USE SIGNAL ;
    PORT
      LAYER M5 ;
        RECT  179.484 189.888 179.508 190.08 ;
    END
  END s0__ts[465]
  PIN s0__ts[466]
    DIRECTION OUTPUT ;
    USE SIGNAL ;
    PORT
      LAYER M5 ;
        RECT  179.724 189.888 179.748 190.08 ;
    END
  END s0__ts[466]
  PIN s0__ts[467]
    DIRECTION OUTPUT ;
    USE SIGNAL ;
    PORT
      LAYER M5 ;
        RECT  179.964 189.888 179.988 190.08 ;
    END
  END s0__ts[467]
  PIN s0__ts[468]
    DIRECTION OUTPUT ;
    USE SIGNAL ;
    PORT
      LAYER M5 ;
        RECT  180.156 189.888 180.18 190.08 ;
    END
  END s0__ts[468]
  PIN s0__ts[469]
    DIRECTION OUTPUT ;
    USE SIGNAL ;
    PORT
      LAYER M5 ;
        RECT  180.396 189.888 180.42 190.08 ;
    END
  END s0__ts[469]
  PIN s0__ts[46]
    DIRECTION OUTPUT ;
    USE SIGNAL ;
    PORT
      LAYER M5 ;
        RECT  84.156 189.888 84.18 190.08 ;
    END
  END s0__ts[46]
  PIN s0__ts[470]
    DIRECTION OUTPUT ;
    USE SIGNAL ;
    PORT
      LAYER M5 ;
        RECT  180.636 189.888 180.66 190.08 ;
    END
  END s0__ts[470]
  PIN s0__ts[471]
    DIRECTION OUTPUT ;
    USE SIGNAL ;
    PORT
      LAYER M5 ;
        RECT  180.876 189.888 180.9 190.08 ;
    END
  END s0__ts[471]
  PIN s0__ts[472]
    DIRECTION OUTPUT ;
    USE SIGNAL ;
    PORT
      LAYER M5 ;
        RECT  181.068 189.888 181.092 190.08 ;
    END
  END s0__ts[472]
  PIN s0__ts[473]
    DIRECTION OUTPUT ;
    USE SIGNAL ;
    PORT
      LAYER M5 ;
        RECT  181.308 189.888 181.332 190.08 ;
    END
  END s0__ts[473]
  PIN s0__ts[474]
    DIRECTION OUTPUT ;
    USE SIGNAL ;
    PORT
      LAYER M5 ;
        RECT  181.548 189.888 181.572 190.08 ;
    END
  END s0__ts[474]
  PIN s0__ts[475]
    DIRECTION OUTPUT ;
    USE SIGNAL ;
    PORT
      LAYER M5 ;
        RECT  181.788 189.888 181.812 190.08 ;
    END
  END s0__ts[475]
  PIN s0__ts[476]
    DIRECTION OUTPUT ;
    USE SIGNAL ;
    PORT
      LAYER M5 ;
        RECT  181.98 189.888 182.004 190.08 ;
    END
  END s0__ts[476]
  PIN s0__ts[477]
    DIRECTION OUTPUT ;
    USE SIGNAL ;
    PORT
      LAYER M5 ;
        RECT  182.22 189.888 182.244 190.08 ;
    END
  END s0__ts[477]
  PIN s0__ts[478]
    DIRECTION OUTPUT ;
    USE SIGNAL ;
    PORT
      LAYER M5 ;
        RECT  182.46 189.888 182.484 190.08 ;
    END
  END s0__ts[478]
  PIN s0__ts[479]
    DIRECTION OUTPUT ;
    USE SIGNAL ;
    PORT
      LAYER M5 ;
        RECT  182.652 189.888 182.676 190.08 ;
    END
  END s0__ts[479]
  PIN s0__ts[47]
    DIRECTION OUTPUT ;
    USE SIGNAL ;
    PORT
      LAYER M5 ;
        RECT  84.396 189.888 84.42 190.08 ;
    END
  END s0__ts[47]
  PIN s0__ts[480]
    DIRECTION OUTPUT ;
    USE SIGNAL ;
    PORT
      LAYER M5 ;
        RECT  182.892 189.888 182.916 190.08 ;
    END
  END s0__ts[480]
  PIN s0__ts[481]
    DIRECTION OUTPUT ;
    USE SIGNAL ;
    PORT
      LAYER M5 ;
        RECT  183.132 189.888 183.156 190.08 ;
    END
  END s0__ts[481]
  PIN s0__ts[482]
    DIRECTION OUTPUT ;
    USE SIGNAL ;
    PORT
      LAYER M5 ;
        RECT  183.372 189.888 183.396 190.08 ;
    END
  END s0__ts[482]
  PIN s0__ts[483]
    DIRECTION OUTPUT ;
    USE SIGNAL ;
    PORT
      LAYER M5 ;
        RECT  183.564 189.888 183.588 190.08 ;
    END
  END s0__ts[483]
  PIN s0__ts[484]
    DIRECTION OUTPUT ;
    USE SIGNAL ;
    PORT
      LAYER M5 ;
        RECT  183.804 189.888 183.828 190.08 ;
    END
  END s0__ts[484]
  PIN s0__ts[485]
    DIRECTION OUTPUT ;
    USE SIGNAL ;
    PORT
      LAYER M5 ;
        RECT  184.044 189.888 184.068 190.08 ;
    END
  END s0__ts[485]
  PIN s0__ts[486]
    DIRECTION OUTPUT ;
    USE SIGNAL ;
    PORT
      LAYER M5 ;
        RECT  184.284 189.888 184.308 190.08 ;
    END
  END s0__ts[486]
  PIN s0__ts[487]
    DIRECTION OUTPUT ;
    USE SIGNAL ;
    PORT
      LAYER M5 ;
        RECT  184.476 189.888 184.5 190.08 ;
    END
  END s0__ts[487]
  PIN s0__ts[488]
    DIRECTION OUTPUT ;
    USE SIGNAL ;
    PORT
      LAYER M5 ;
        RECT  184.716 189.888 184.74 190.08 ;
    END
  END s0__ts[488]
  PIN s0__ts[489]
    DIRECTION OUTPUT ;
    USE SIGNAL ;
    PORT
      LAYER M5 ;
        RECT  184.956 189.888 184.98 190.08 ;
    END
  END s0__ts[489]
  PIN s0__ts[48]
    DIRECTION OUTPUT ;
    USE SIGNAL ;
    PORT
      LAYER M5 ;
        RECT  84.636 189.888 84.66 190.08 ;
    END
  END s0__ts[48]
  PIN s0__ts[490]
    DIRECTION OUTPUT ;
    USE SIGNAL ;
    PORT
      LAYER M5 ;
        RECT  185.196 189.888 185.22 190.08 ;
    END
  END s0__ts[490]
  PIN s0__ts[491]
    DIRECTION OUTPUT ;
    USE SIGNAL ;
    PORT
      LAYER M5 ;
        RECT  185.388 189.888 185.412 190.08 ;
    END
  END s0__ts[491]
  PIN s0__ts[492]
    DIRECTION OUTPUT ;
    USE SIGNAL ;
    PORT
      LAYER M5 ;
        RECT  185.628 189.888 185.652 190.08 ;
    END
  END s0__ts[492]
  PIN s0__ts[493]
    DIRECTION OUTPUT ;
    USE SIGNAL ;
    PORT
      LAYER M5 ;
        RECT  185.868 189.888 185.892 190.08 ;
    END
  END s0__ts[493]
  PIN s0__ts[494]
    DIRECTION OUTPUT ;
    USE SIGNAL ;
    PORT
      LAYER M5 ;
        RECT  186.108 189.888 186.132 190.08 ;
    END
  END s0__ts[494]
  PIN s0__ts[495]
    DIRECTION OUTPUT ;
    USE SIGNAL ;
    PORT
      LAYER M5 ;
        RECT  186.3 189.888 186.324 190.08 ;
    END
  END s0__ts[495]
  PIN s0__ts[496]
    DIRECTION OUTPUT ;
    USE SIGNAL ;
    PORT
      LAYER M5 ;
        RECT  186.54 189.888 186.564 190.08 ;
    END
  END s0__ts[496]
  PIN s0__ts[497]
    DIRECTION OUTPUT ;
    USE SIGNAL ;
    PORT
      LAYER M5 ;
        RECT  186.78 189.888 186.804 190.08 ;
    END
  END s0__ts[497]
  PIN s0__ts[498]
    DIRECTION OUTPUT ;
    USE SIGNAL ;
    PORT
      LAYER M5 ;
        RECT  187.02 189.888 187.044 190.08 ;
    END
  END s0__ts[498]
  PIN s0__ts[499]
    DIRECTION OUTPUT ;
    USE SIGNAL ;
    PORT
      LAYER M5 ;
        RECT  187.212 189.888 187.236 190.08 ;
    END
  END s0__ts[499]
  PIN s0__ts[49]
    DIRECTION OUTPUT ;
    USE SIGNAL ;
    PORT
      LAYER M5 ;
        RECT  84.828 189.888 84.852 190.08 ;
    END
  END s0__ts[49]
  PIN s0__ts[4]
    DIRECTION OUTPUT ;
    USE SIGNAL ;
    PORT
      LAYER M5 ;
        RECT  74.604 189.888 74.628 190.08 ;
    END
  END s0__ts[4]
  PIN s0__ts[500]
    DIRECTION OUTPUT ;
    USE SIGNAL ;
    PORT
      LAYER M5 ;
        RECT  187.452 189.888 187.476 190.08 ;
    END
  END s0__ts[500]
  PIN s0__ts[501]
    DIRECTION OUTPUT ;
    USE SIGNAL ;
    PORT
      LAYER M5 ;
        RECT  187.692 189.888 187.716 190.08 ;
    END
  END s0__ts[501]
  PIN s0__ts[502]
    DIRECTION OUTPUT ;
    USE SIGNAL ;
    PORT
      LAYER M5 ;
        RECT  187.884 189.888 187.908 190.08 ;
    END
  END s0__ts[502]
  PIN s0__ts[503]
    DIRECTION OUTPUT ;
    USE SIGNAL ;
    PORT
      LAYER M5 ;
        RECT  188.124 189.888 188.148 190.08 ;
    END
  END s0__ts[503]
  PIN s0__ts[504]
    DIRECTION OUTPUT ;
    USE SIGNAL ;
    PORT
      LAYER M5 ;
        RECT  188.364 189.888 188.388 190.08 ;
    END
  END s0__ts[504]
  PIN s0__ts[505]
    DIRECTION OUTPUT ;
    USE SIGNAL ;
    PORT
      LAYER M5 ;
        RECT  188.604 189.888 188.628 190.08 ;
    END
  END s0__ts[505]
  PIN s0__ts[506]
    DIRECTION OUTPUT ;
    USE SIGNAL ;
    PORT
      LAYER M5 ;
        RECT  188.796 189.888 188.82 190.08 ;
    END
  END s0__ts[506]
  PIN s0__ts[507]
    DIRECTION OUTPUT ;
    USE SIGNAL ;
    PORT
      LAYER M5 ;
        RECT  189.036 189.888 189.06 190.08 ;
    END
  END s0__ts[507]
  PIN s0__ts[508]
    DIRECTION OUTPUT ;
    USE SIGNAL ;
    PORT
      LAYER M5 ;
        RECT  189.276 189.888 189.3 190.08 ;
    END
  END s0__ts[508]
  PIN s0__ts[509]
    DIRECTION OUTPUT ;
    USE SIGNAL ;
    PORT
      LAYER M5 ;
        RECT  189.516 189.888 189.54 190.08 ;
    END
  END s0__ts[509]
  PIN s0__ts[50]
    DIRECTION OUTPUT ;
    USE SIGNAL ;
    PORT
      LAYER M5 ;
        RECT  85.068 189.888 85.092 190.08 ;
    END
  END s0__ts[50]
  PIN s0__ts[510]
    DIRECTION OUTPUT ;
    USE SIGNAL ;
    PORT
      LAYER M5 ;
        RECT  189.708 189.888 189.732 190.08 ;
    END
  END s0__ts[510]
  PIN s0__ts[511]
    DIRECTION OUTPUT ;
    USE SIGNAL ;
    PORT
      LAYER M5 ;
        RECT  189.948 189.888 189.972 190.08 ;
    END
  END s0__ts[511]
  PIN s0__ts[51]
    DIRECTION OUTPUT ;
    USE SIGNAL ;
    PORT
      LAYER M5 ;
        RECT  85.308 189.888 85.332 190.08 ;
    END
  END s0__ts[51]
  PIN s0__ts[52]
    DIRECTION OUTPUT ;
    USE SIGNAL ;
    PORT
      LAYER M5 ;
        RECT  85.548 189.888 85.572 190.08 ;
    END
  END s0__ts[52]
  PIN s0__ts[53]
    DIRECTION OUTPUT ;
    USE SIGNAL ;
    PORT
      LAYER M5 ;
        RECT  85.74 189.888 85.764 190.08 ;
    END
  END s0__ts[53]
  PIN s0__ts[54]
    DIRECTION OUTPUT ;
    USE SIGNAL ;
    PORT
      LAYER M5 ;
        RECT  85.98 189.888 86.004 190.08 ;
    END
  END s0__ts[54]
  PIN s0__ts[55]
    DIRECTION OUTPUT ;
    USE SIGNAL ;
    PORT
      LAYER M5 ;
        RECT  86.22 189.888 86.244 190.08 ;
    END
  END s0__ts[55]
  PIN s0__ts[56]
    DIRECTION OUTPUT ;
    USE SIGNAL ;
    PORT
      LAYER M5 ;
        RECT  86.46 189.888 86.484 190.08 ;
    END
  END s0__ts[56]
  PIN s0__ts[57]
    DIRECTION OUTPUT ;
    USE SIGNAL ;
    PORT
      LAYER M5 ;
        RECT  86.652 189.888 86.676 190.08 ;
    END
  END s0__ts[57]
  PIN s0__ts[58]
    DIRECTION OUTPUT ;
    USE SIGNAL ;
    PORT
      LAYER M5 ;
        RECT  86.892 189.888 86.916 190.08 ;
    END
  END s0__ts[58]
  PIN s0__ts[59]
    DIRECTION OUTPUT ;
    USE SIGNAL ;
    PORT
      LAYER M5 ;
        RECT  87.132 189.888 87.156 190.08 ;
    END
  END s0__ts[59]
  PIN s0__ts[5]
    DIRECTION OUTPUT ;
    USE SIGNAL ;
    PORT
      LAYER M5 ;
        RECT  74.844 189.888 74.868 190.08 ;
    END
  END s0__ts[5]
  PIN s0__ts[60]
    DIRECTION OUTPUT ;
    USE SIGNAL ;
    PORT
      LAYER M5 ;
        RECT  87.372 189.888 87.396 190.08 ;
    END
  END s0__ts[60]
  PIN s0__ts[61]
    DIRECTION OUTPUT ;
    USE SIGNAL ;
    PORT
      LAYER M5 ;
        RECT  87.564 189.888 87.588 190.08 ;
    END
  END s0__ts[61]
  PIN s0__ts[62]
    DIRECTION OUTPUT ;
    USE SIGNAL ;
    PORT
      LAYER M5 ;
        RECT  87.804 189.888 87.828 190.08 ;
    END
  END s0__ts[62]
  PIN s0__ts[63]
    DIRECTION OUTPUT ;
    USE SIGNAL ;
    PORT
      LAYER M5 ;
        RECT  88.044 189.888 88.068 190.08 ;
    END
  END s0__ts[63]
  PIN s0__ts[64]
    DIRECTION OUTPUT ;
    USE SIGNAL ;
    PORT
      LAYER M5 ;
        RECT  88.236 189.888 88.26 190.08 ;
    END
  END s0__ts[64]
  PIN s0__ts[65]
    DIRECTION OUTPUT ;
    USE SIGNAL ;
    PORT
      LAYER M5 ;
        RECT  88.476 189.888 88.5 190.08 ;
    END
  END s0__ts[65]
  PIN s0__ts[66]
    DIRECTION OUTPUT ;
    USE SIGNAL ;
    PORT
      LAYER M5 ;
        RECT  88.716 189.888 88.74 190.08 ;
    END
  END s0__ts[66]
  PIN s0__ts[67]
    DIRECTION OUTPUT ;
    USE SIGNAL ;
    PORT
      LAYER M5 ;
        RECT  88.956 189.888 88.98 190.08 ;
    END
  END s0__ts[67]
  PIN s0__ts[68]
    DIRECTION OUTPUT ;
    USE SIGNAL ;
    PORT
      LAYER M5 ;
        RECT  89.148 189.888 89.172 190.08 ;
    END
  END s0__ts[68]
  PIN s0__ts[69]
    DIRECTION OUTPUT ;
    USE SIGNAL ;
    PORT
      LAYER M5 ;
        RECT  89.388 189.888 89.412 190.08 ;
    END
  END s0__ts[69]
  PIN s0__ts[6]
    DIRECTION OUTPUT ;
    USE SIGNAL ;
    PORT
      LAYER M5 ;
        RECT  75.084 189.888 75.108 190.08 ;
    END
  END s0__ts[6]
  PIN s0__ts[70]
    DIRECTION OUTPUT ;
    USE SIGNAL ;
    PORT
      LAYER M5 ;
        RECT  89.628 189.888 89.652 190.08 ;
    END
  END s0__ts[70]
  PIN s0__ts[71]
    DIRECTION OUTPUT ;
    USE SIGNAL ;
    PORT
      LAYER M5 ;
        RECT  89.868 189.888 89.892 190.08 ;
    END
  END s0__ts[71]
  PIN s0__ts[72]
    DIRECTION OUTPUT ;
    USE SIGNAL ;
    PORT
      LAYER M5 ;
        RECT  90.06 189.888 90.084 190.08 ;
    END
  END s0__ts[72]
  PIN s0__ts[73]
    DIRECTION OUTPUT ;
    USE SIGNAL ;
    PORT
      LAYER M5 ;
        RECT  90.3 189.888 90.324 190.08 ;
    END
  END s0__ts[73]
  PIN s0__ts[74]
    DIRECTION OUTPUT ;
    USE SIGNAL ;
    PORT
      LAYER M5 ;
        RECT  90.54 189.888 90.564 190.08 ;
    END
  END s0__ts[74]
  PIN s0__ts[75]
    DIRECTION OUTPUT ;
    USE SIGNAL ;
    PORT
      LAYER M5 ;
        RECT  90.78 189.888 90.804 190.08 ;
    END
  END s0__ts[75]
  PIN s0__ts[76]
    DIRECTION OUTPUT ;
    USE SIGNAL ;
    PORT
      LAYER M5 ;
        RECT  90.972 189.888 90.996 190.08 ;
    END
  END s0__ts[76]
  PIN s0__ts[77]
    DIRECTION OUTPUT ;
    USE SIGNAL ;
    PORT
      LAYER M5 ;
        RECT  91.212 189.888 91.236 190.08 ;
    END
  END s0__ts[77]
  PIN s0__ts[78]
    DIRECTION OUTPUT ;
    USE SIGNAL ;
    PORT
      LAYER M5 ;
        RECT  91.452 189.888 91.476 190.08 ;
    END
  END s0__ts[78]
  PIN s0__ts[79]
    DIRECTION OUTPUT ;
    USE SIGNAL ;
    PORT
      LAYER M5 ;
        RECT  91.692 189.888 91.716 190.08 ;
    END
  END s0__ts[79]
  PIN s0__ts[7]
    DIRECTION OUTPUT ;
    USE SIGNAL ;
    PORT
      LAYER M5 ;
        RECT  75.276 189.888 75.3 190.08 ;
    END
  END s0__ts[7]
  PIN s0__ts[80]
    DIRECTION OUTPUT ;
    USE SIGNAL ;
    PORT
      LAYER M5 ;
        RECT  91.884 189.888 91.908 190.08 ;
    END
  END s0__ts[80]
  PIN s0__ts[81]
    DIRECTION OUTPUT ;
    USE SIGNAL ;
    PORT
      LAYER M5 ;
        RECT  92.124 189.888 92.148 190.08 ;
    END
  END s0__ts[81]
  PIN s0__ts[82]
    DIRECTION OUTPUT ;
    USE SIGNAL ;
    PORT
      LAYER M5 ;
        RECT  92.364 189.888 92.388 190.08 ;
    END
  END s0__ts[82]
  PIN s0__ts[83]
    DIRECTION OUTPUT ;
    USE SIGNAL ;
    PORT
      LAYER M5 ;
        RECT  92.604 189.888 92.628 190.08 ;
    END
  END s0__ts[83]
  PIN s0__ts[84]
    DIRECTION OUTPUT ;
    USE SIGNAL ;
    PORT
      LAYER M5 ;
        RECT  92.796 189.888 92.82 190.08 ;
    END
  END s0__ts[84]
  PIN s0__ts[85]
    DIRECTION OUTPUT ;
    USE SIGNAL ;
    PORT
      LAYER M5 ;
        RECT  93.036 189.888 93.06 190.08 ;
    END
  END s0__ts[85]
  PIN s0__ts[86]
    DIRECTION OUTPUT ;
    USE SIGNAL ;
    PORT
      LAYER M5 ;
        RECT  93.276 189.888 93.3 190.08 ;
    END
  END s0__ts[86]
  PIN s0__ts[87]
    DIRECTION OUTPUT ;
    USE SIGNAL ;
    PORT
      LAYER M5 ;
        RECT  93.468 189.888 93.492 190.08 ;
    END
  END s0__ts[87]
  PIN s0__ts[88]
    DIRECTION OUTPUT ;
    USE SIGNAL ;
    PORT
      LAYER M5 ;
        RECT  93.708 189.888 93.732 190.08 ;
    END
  END s0__ts[88]
  PIN s0__ts[89]
    DIRECTION OUTPUT ;
    USE SIGNAL ;
    PORT
      LAYER M5 ;
        RECT  93.948 189.888 93.972 190.08 ;
    END
  END s0__ts[89]
  PIN s0__ts[8]
    DIRECTION OUTPUT ;
    USE SIGNAL ;
    PORT
      LAYER M5 ;
        RECT  75.516 189.888 75.54 190.08 ;
    END
  END s0__ts[8]
  PIN s0__ts[90]
    DIRECTION OUTPUT ;
    USE SIGNAL ;
    PORT
      LAYER M5 ;
        RECT  94.188 189.888 94.212 190.08 ;
    END
  END s0__ts[90]
  PIN s0__ts[91]
    DIRECTION OUTPUT ;
    USE SIGNAL ;
    PORT
      LAYER M5 ;
        RECT  94.38 189.888 94.404 190.08 ;
    END
  END s0__ts[91]
  PIN s0__ts[92]
    DIRECTION OUTPUT ;
    USE SIGNAL ;
    PORT
      LAYER M5 ;
        RECT  94.62 189.888 94.644 190.08 ;
    END
  END s0__ts[92]
  PIN s0__ts[93]
    DIRECTION OUTPUT ;
    USE SIGNAL ;
    PORT
      LAYER M5 ;
        RECT  94.86 189.888 94.884 190.08 ;
    END
  END s0__ts[93]
  PIN s0__ts[94]
    DIRECTION OUTPUT ;
    USE SIGNAL ;
    PORT
      LAYER M5 ;
        RECT  95.1 189.888 95.124 190.08 ;
    END
  END s0__ts[94]
  PIN s0__ts[95]
    DIRECTION OUTPUT ;
    USE SIGNAL ;
    PORT
      LAYER M5 ;
        RECT  95.292 189.888 95.316 190.08 ;
    END
  END s0__ts[95]
  PIN s0__ts[96]
    DIRECTION OUTPUT ;
    USE SIGNAL ;
    PORT
      LAYER M5 ;
        RECT  95.532 189.888 95.556 190.08 ;
    END
  END s0__ts[96]
  PIN s0__ts[97]
    DIRECTION OUTPUT ;
    USE SIGNAL ;
    PORT
      LAYER M5 ;
        RECT  95.772 189.888 95.796 190.08 ;
    END
  END s0__ts[97]
  PIN s0__ts[98]
    DIRECTION OUTPUT ;
    USE SIGNAL ;
    PORT
      LAYER M5 ;
        RECT  96.012 189.888 96.036 190.08 ;
    END
  END s0__ts[98]
  PIN s0__ts[99]
    DIRECTION OUTPUT ;
    USE SIGNAL ;
    PORT
      LAYER M5 ;
        RECT  96.204 189.888 96.228 190.08 ;
    END
  END s0__ts[99]
  PIN s0__ts[9]
    DIRECTION OUTPUT ;
    USE SIGNAL ;
    PORT
      LAYER M5 ;
        RECT  75.756 189.888 75.78 190.08 ;
    END
  END s0__ts[9]
  PIN s1__bc[0]
    DIRECTION INPUT ;
    USE SIGNAL ;
    PORT
      LAYER M5 ;
        RECT  190.188 189.888 190.212 190.08 ;
    END
  END s1__bc[0]
  PIN s1__bc[10]
    DIRECTION INPUT ;
    USE SIGNAL ;
    PORT
      LAYER M5 ;
        RECT  192.444 189.888 192.468 190.08 ;
    END
  END s1__bc[10]
  PIN s1__bc[11]
    DIRECTION INPUT ;
    USE SIGNAL ;
    PORT
      LAYER M5 ;
        RECT  192.684 189.888 192.708 190.08 ;
    END
  END s1__bc[11]
  PIN s1__bc[12]
    DIRECTION INPUT ;
    USE SIGNAL ;
    PORT
      LAYER M5 ;
        RECT  192.924 189.888 192.948 190.08 ;
    END
  END s1__bc[12]
  PIN s1__bc[13]
    DIRECTION INPUT ;
    USE SIGNAL ;
    PORT
      LAYER M5 ;
        RECT  193.116 189.888 193.14 190.08 ;
    END
  END s1__bc[13]
  PIN s1__bc[14]
    DIRECTION INPUT ;
    USE SIGNAL ;
    PORT
      LAYER M5 ;
        RECT  193.356 189.888 193.38 190.08 ;
    END
  END s1__bc[14]
  PIN s1__bc[15]
    DIRECTION INPUT ;
    USE SIGNAL ;
    PORT
      LAYER M5 ;
        RECT  193.596 189.888 193.62 190.08 ;
    END
  END s1__bc[15]
  PIN s1__bc[16]
    DIRECTION INPUT ;
    USE SIGNAL ;
    PORT
      LAYER M5 ;
        RECT  193.836 189.888 193.86 190.08 ;
    END
  END s1__bc[16]
  PIN s1__bc[17]
    DIRECTION INPUT ;
    USE SIGNAL ;
    PORT
      LAYER M5 ;
        RECT  194.028 189.888 194.052 190.08 ;
    END
  END s1__bc[17]
  PIN s1__bc[18]
    DIRECTION INPUT ;
    USE SIGNAL ;
    PORT
      LAYER M5 ;
        RECT  194.268 189.888 194.292 190.08 ;
    END
  END s1__bc[18]
  PIN s1__bc[19]
    DIRECTION INPUT ;
    USE SIGNAL ;
    PORT
      LAYER M5 ;
        RECT  194.508 189.888 194.532 190.08 ;
    END
  END s1__bc[19]
  PIN s1__bc[1]
    DIRECTION INPUT ;
    USE SIGNAL ;
    PORT
      LAYER M5 ;
        RECT  190.428 189.888 190.452 190.08 ;
    END
  END s1__bc[1]
  PIN s1__bc[20]
    DIRECTION INPUT ;
    USE SIGNAL ;
    PORT
      LAYER M5 ;
        RECT  194.748 189.888 194.772 190.08 ;
    END
  END s1__bc[20]
  PIN s1__bc[21]
    DIRECTION INPUT ;
    USE SIGNAL ;
    PORT
      LAYER M5 ;
        RECT  194.94 189.888 194.964 190.08 ;
    END
  END s1__bc[21]
  PIN s1__bc[22]
    DIRECTION INPUT ;
    USE SIGNAL ;
    PORT
      LAYER M5 ;
        RECT  195.18 189.888 195.204 190.08 ;
    END
  END s1__bc[22]
  PIN s1__bc[2]
    DIRECTION INPUT ;
    USE SIGNAL ;
    PORT
      LAYER M5 ;
        RECT  190.62 189.888 190.644 190.08 ;
    END
  END s1__bc[2]
  PIN s1__bc[3]
    DIRECTION INPUT ;
    USE SIGNAL ;
    PORT
      LAYER M5 ;
        RECT  190.86 189.888 190.884 190.08 ;
    END
  END s1__bc[3]
  PIN s1__bc[4]
    DIRECTION INPUT ;
    USE SIGNAL ;
    PORT
      LAYER M5 ;
        RECT  191.1 189.888 191.124 190.08 ;
    END
  END s1__bc[4]
  PIN s1__bc[5]
    DIRECTION INPUT ;
    USE SIGNAL ;
    PORT
      LAYER M5 ;
        RECT  191.34 189.888 191.364 190.08 ;
    END
  END s1__bc[5]
  PIN s1__bc[6]
    DIRECTION INPUT ;
    USE SIGNAL ;
    PORT
      LAYER M5 ;
        RECT  191.532 189.888 191.556 190.08 ;
    END
  END s1__bc[6]
  PIN s1__bc[7]
    DIRECTION INPUT ;
    USE SIGNAL ;
    PORT
      LAYER M5 ;
        RECT  191.772 189.888 191.796 190.08 ;
    END
  END s1__bc[7]
  PIN s1__bc[8]
    DIRECTION INPUT ;
    USE SIGNAL ;
    PORT
      LAYER M5 ;
        RECT  192.012 189.888 192.036 190.08 ;
    END
  END s1__bc[8]
  PIN s1__bc[9]
    DIRECTION INPUT ;
    USE SIGNAL ;
    PORT
      LAYER M5 ;
        RECT  192.252 189.888 192.276 190.08 ;
    END
  END s1__bc[9]
  PIN s1__clk[0]
    DIRECTION INPUT ;
    USE SIGNAL ;
    PORT
      LAYER M5 ;
        RECT  195.42 189.888 195.444 190.08 ;
    END
  END s1__clk[0]
  PIN s1__fault[0]
    DIRECTION OUTPUT ;
    USE SIGNAL ;
    PORT
      LAYER M5 ;
        RECT  195.66 189.888 195.684 190.08 ;
    END
  END s1__fault[0]
  PIN s1__pe2[0]
    DIRECTION INPUT ;
    USE SIGNAL ;
    PORT
      LAYER M5 ;
        RECT  195.852 189.888 195.876 190.08 ;
    END
  END s1__pe2[0]
  PIN s1__pe2[10]
    DIRECTION INPUT ;
    USE SIGNAL ;
    PORT
      LAYER M5 ;
        RECT  198.156 189.888 198.18 190.08 ;
    END
  END s1__pe2[10]
  PIN s1__pe2[11]
    DIRECTION INPUT ;
    USE SIGNAL ;
    PORT
      LAYER M5 ;
        RECT  198.348 189.888 198.372 190.08 ;
    END
  END s1__pe2[11]
  PIN s1__pe2[12]
    DIRECTION INPUT ;
    USE SIGNAL ;
    PORT
      LAYER M5 ;
        RECT  198.588 189.888 198.612 190.08 ;
    END
  END s1__pe2[12]
  PIN s1__pe2[13]
    DIRECTION INPUT ;
    USE SIGNAL ;
    PORT
      LAYER M5 ;
        RECT  198.828 189.888 198.852 190.08 ;
    END
  END s1__pe2[13]
  PIN s1__pe2[14]
    DIRECTION INPUT ;
    USE SIGNAL ;
    PORT
      LAYER M5 ;
        RECT  199.068 189.888 199.092 190.08 ;
    END
  END s1__pe2[14]
  PIN s1__pe2[15]
    DIRECTION INPUT ;
    USE SIGNAL ;
    PORT
      LAYER M5 ;
        RECT  199.26 189.888 199.284 190.08 ;
    END
  END s1__pe2[15]
  PIN s1__pe2[16]
    DIRECTION INPUT ;
    USE SIGNAL ;
    PORT
      LAYER M5 ;
        RECT  199.5 189.888 199.524 190.08 ;
    END
  END s1__pe2[16]
  PIN s1__pe2[17]
    DIRECTION INPUT ;
    USE SIGNAL ;
    PORT
      LAYER M5 ;
        RECT  199.74 189.888 199.764 190.08 ;
    END
  END s1__pe2[17]
  PIN s1__pe2[18]
    DIRECTION INPUT ;
    USE SIGNAL ;
    PORT
      LAYER M5 ;
        RECT  199.98 189.888 200.004 190.08 ;
    END
  END s1__pe2[18]
  PIN s1__pe2[19]
    DIRECTION INPUT ;
    USE SIGNAL ;
    PORT
      LAYER M5 ;
        RECT  200.172 189.888 200.196 190.08 ;
    END
  END s1__pe2[19]
  PIN s1__pe2[1]
    DIRECTION INPUT ;
    USE SIGNAL ;
    PORT
      LAYER M5 ;
        RECT  196.092 189.888 196.116 190.08 ;
    END
  END s1__pe2[1]
  PIN s1__pe2[20]
    DIRECTION INPUT ;
    USE SIGNAL ;
    PORT
      LAYER M5 ;
        RECT  200.412 189.888 200.436 190.08 ;
    END
  END s1__pe2[20]
  PIN s1__pe2[21]
    DIRECTION INPUT ;
    USE SIGNAL ;
    PORT
      LAYER M5 ;
        RECT  200.652 189.888 200.676 190.08 ;
    END
  END s1__pe2[21]
  PIN s1__pe2[22]
    DIRECTION INPUT ;
    USE SIGNAL ;
    PORT
      LAYER M5 ;
        RECT  200.892 189.888 200.916 190.08 ;
    END
  END s1__pe2[22]
  PIN s1__pe2[23]
    DIRECTION INPUT ;
    USE SIGNAL ;
    PORT
      LAYER M5 ;
        RECT  201.084 189.888 201.108 190.08 ;
    END
  END s1__pe2[23]
  PIN s1__pe2[24]
    DIRECTION INPUT ;
    USE SIGNAL ;
    PORT
      LAYER M5 ;
        RECT  201.324 189.888 201.348 190.08 ;
    END
  END s1__pe2[24]
  PIN s1__pe2[25]
    DIRECTION INPUT ;
    USE SIGNAL ;
    PORT
      LAYER M5 ;
        RECT  201.564 189.888 201.588 190.08 ;
    END
  END s1__pe2[25]
  PIN s1__pe2[26]
    DIRECTION INPUT ;
    USE SIGNAL ;
    PORT
      LAYER M5 ;
        RECT  201.804 189.888 201.828 190.08 ;
    END
  END s1__pe2[26]
  PIN s1__pe2[27]
    DIRECTION INPUT ;
    USE SIGNAL ;
    PORT
      LAYER M5 ;
        RECT  201.996 189.888 202.02 190.08 ;
    END
  END s1__pe2[27]
  PIN s1__pe2[28]
    DIRECTION INPUT ;
    USE SIGNAL ;
    PORT
      LAYER M5 ;
        RECT  202.236 189.888 202.26 190.08 ;
    END
  END s1__pe2[28]
  PIN s1__pe2[29]
    DIRECTION INPUT ;
    USE SIGNAL ;
    PORT
      LAYER M5 ;
        RECT  202.476 189.888 202.5 190.08 ;
    END
  END s1__pe2[29]
  PIN s1__pe2[2]
    DIRECTION INPUT ;
    USE SIGNAL ;
    PORT
      LAYER M5 ;
        RECT  196.332 189.888 196.356 190.08 ;
    END
  END s1__pe2[2]
  PIN s1__pe2[30]
    DIRECTION INPUT ;
    USE SIGNAL ;
    PORT
      LAYER M5 ;
        RECT  202.716 189.888 202.74 190.08 ;
    END
  END s1__pe2[30]
  PIN s1__pe2[31]
    DIRECTION INPUT ;
    USE SIGNAL ;
    PORT
      LAYER M5 ;
        RECT  202.908 189.888 202.932 190.08 ;
    END
  END s1__pe2[31]
  PIN s1__pe2[3]
    DIRECTION INPUT ;
    USE SIGNAL ;
    PORT
      LAYER M5 ;
        RECT  196.572 189.888 196.596 190.08 ;
    END
  END s1__pe2[3]
  PIN s1__pe2[4]
    DIRECTION INPUT ;
    USE SIGNAL ;
    PORT
      LAYER M5 ;
        RECT  196.764 189.888 196.788 190.08 ;
    END
  END s1__pe2[4]
  PIN s1__pe2[5]
    DIRECTION INPUT ;
    USE SIGNAL ;
    PORT
      LAYER M5 ;
        RECT  197.004 189.888 197.028 190.08 ;
    END
  END s1__pe2[5]
  PIN s1__pe2[6]
    DIRECTION INPUT ;
    USE SIGNAL ;
    PORT
      LAYER M5 ;
        RECT  197.244 189.888 197.268 190.08 ;
    END
  END s1__pe2[6]
  PIN s1__pe2[7]
    DIRECTION INPUT ;
    USE SIGNAL ;
    PORT
      LAYER M5 ;
        RECT  197.484 189.888 197.508 190.08 ;
    END
  END s1__pe2[7]
  PIN s1__pe2[8]
    DIRECTION INPUT ;
    USE SIGNAL ;
    PORT
      LAYER M5 ;
        RECT  197.676 189.888 197.7 190.08 ;
    END
  END s1__pe2[8]
  PIN s1__pe2[9]
    DIRECTION INPUT ;
    USE SIGNAL ;
    PORT
      LAYER M5 ;
        RECT  197.916 189.888 197.94 190.08 ;
    END
  END s1__pe2[9]
  PIN s1__pv2[0]
    DIRECTION INPUT ;
    USE SIGNAL ;
    PORT
      LAYER M5 ;
        RECT  203.148 189.888 203.172 190.08 ;
    END
  END s1__pv2[0]
  PIN s1__pv2[100]
    DIRECTION INPUT ;
    USE SIGNAL ;
    PORT
      LAYER M5 ;
        RECT  225.9 189.888 225.924 190.08 ;
    END
  END s1__pv2[100]
  PIN s1__pv2[101]
    DIRECTION INPUT ;
    USE SIGNAL ;
    PORT
      LAYER M5 ;
        RECT  226.14 189.888 226.164 190.08 ;
    END
  END s1__pv2[101]
  PIN s1__pv2[102]
    DIRECTION INPUT ;
    USE SIGNAL ;
    PORT
      LAYER M5 ;
        RECT  226.332 189.888 226.356 190.08 ;
    END
  END s1__pv2[102]
  PIN s1__pv2[103]
    DIRECTION INPUT ;
    USE SIGNAL ;
    PORT
      LAYER M5 ;
        RECT  226.572 189.888 226.596 190.08 ;
    END
  END s1__pv2[103]
  PIN s1__pv2[104]
    DIRECTION INPUT ;
    USE SIGNAL ;
    PORT
      LAYER M5 ;
        RECT  226.812 189.888 226.836 190.08 ;
    END
  END s1__pv2[104]
  PIN s1__pv2[105]
    DIRECTION INPUT ;
    USE SIGNAL ;
    PORT
      LAYER M5 ;
        RECT  227.052 189.888 227.076 190.08 ;
    END
  END s1__pv2[105]
  PIN s1__pv2[106]
    DIRECTION INPUT ;
    USE SIGNAL ;
    PORT
      LAYER M5 ;
        RECT  227.244 189.888 227.268 190.08 ;
    END
  END s1__pv2[106]
  PIN s1__pv2[107]
    DIRECTION INPUT ;
    USE SIGNAL ;
    PORT
      LAYER M5 ;
        RECT  227.484 189.888 227.508 190.08 ;
    END
  END s1__pv2[107]
  PIN s1__pv2[108]
    DIRECTION INPUT ;
    USE SIGNAL ;
    PORT
      LAYER M5 ;
        RECT  227.724 189.888 227.748 190.08 ;
    END
  END s1__pv2[108]
  PIN s1__pv2[109]
    DIRECTION INPUT ;
    USE SIGNAL ;
    PORT
      LAYER M5 ;
        RECT  227.964 189.888 227.988 190.08 ;
    END
  END s1__pv2[109]
  PIN s1__pv2[10]
    DIRECTION INPUT ;
    USE SIGNAL ;
    PORT
      LAYER M5 ;
        RECT  205.404 189.888 205.428 190.08 ;
    END
  END s1__pv2[10]
  PIN s1__pv2[110]
    DIRECTION INPUT ;
    USE SIGNAL ;
    PORT
      LAYER M5 ;
        RECT  228.156 189.888 228.18 190.08 ;
    END
  END s1__pv2[110]
  PIN s1__pv2[111]
    DIRECTION INPUT ;
    USE SIGNAL ;
    PORT
      LAYER M5 ;
        RECT  228.396 189.888 228.42 190.08 ;
    END
  END s1__pv2[111]
  PIN s1__pv2[112]
    DIRECTION INPUT ;
    USE SIGNAL ;
    PORT
      LAYER M5 ;
        RECT  228.636 189.888 228.66 190.08 ;
    END
  END s1__pv2[112]
  PIN s1__pv2[113]
    DIRECTION INPUT ;
    USE SIGNAL ;
    PORT
      LAYER M5 ;
        RECT  228.876 189.888 228.9 190.08 ;
    END
  END s1__pv2[113]
  PIN s1__pv2[114]
    DIRECTION INPUT ;
    USE SIGNAL ;
    PORT
      LAYER M5 ;
        RECT  229.068 189.888 229.092 190.08 ;
    END
  END s1__pv2[114]
  PIN s1__pv2[115]
    DIRECTION INPUT ;
    USE SIGNAL ;
    PORT
      LAYER M5 ;
        RECT  229.308 189.888 229.332 190.08 ;
    END
  END s1__pv2[115]
  PIN s1__pv2[116]
    DIRECTION INPUT ;
    USE SIGNAL ;
    PORT
      LAYER M5 ;
        RECT  229.548 189.888 229.572 190.08 ;
    END
  END s1__pv2[116]
  PIN s1__pv2[117]
    DIRECTION INPUT ;
    USE SIGNAL ;
    PORT
      LAYER M5 ;
        RECT  229.788 189.888 229.812 190.08 ;
    END
  END s1__pv2[117]
  PIN s1__pv2[118]
    DIRECTION INPUT ;
    USE SIGNAL ;
    PORT
      LAYER M5 ;
        RECT  229.98 189.888 230.004 190.08 ;
    END
  END s1__pv2[118]
  PIN s1__pv2[119]
    DIRECTION INPUT ;
    USE SIGNAL ;
    PORT
      LAYER M5 ;
        RECT  230.22 189.888 230.244 190.08 ;
    END
  END s1__pv2[119]
  PIN s1__pv2[11]
    DIRECTION INPUT ;
    USE SIGNAL ;
    PORT
      LAYER M5 ;
        RECT  205.644 189.888 205.668 190.08 ;
    END
  END s1__pv2[11]
  PIN s1__pv2[120]
    DIRECTION INPUT ;
    USE SIGNAL ;
    PORT
      LAYER M5 ;
        RECT  230.46 189.888 230.484 190.08 ;
    END
  END s1__pv2[120]
  PIN s1__pv2[121]
    DIRECTION INPUT ;
    USE SIGNAL ;
    PORT
      LAYER M5 ;
        RECT  230.7 189.888 230.724 190.08 ;
    END
  END s1__pv2[121]
  PIN s1__pv2[122]
    DIRECTION INPUT ;
    USE SIGNAL ;
    PORT
      LAYER M5 ;
        RECT  230.892 189.888 230.916 190.08 ;
    END
  END s1__pv2[122]
  PIN s1__pv2[123]
    DIRECTION INPUT ;
    USE SIGNAL ;
    PORT
      LAYER M5 ;
        RECT  231.132 189.888 231.156 190.08 ;
    END
  END s1__pv2[123]
  PIN s1__pv2[124]
    DIRECTION INPUT ;
    USE SIGNAL ;
    PORT
      LAYER M5 ;
        RECT  231.372 189.888 231.396 190.08 ;
    END
  END s1__pv2[124]
  PIN s1__pv2[125]
    DIRECTION INPUT ;
    USE SIGNAL ;
    PORT
      LAYER M5 ;
        RECT  231.564 189.888 231.588 190.08 ;
    END
  END s1__pv2[125]
  PIN s1__pv2[126]
    DIRECTION INPUT ;
    USE SIGNAL ;
    PORT
      LAYER M5 ;
        RECT  231.804 189.888 231.828 190.08 ;
    END
  END s1__pv2[126]
  PIN s1__pv2[127]
    DIRECTION INPUT ;
    USE SIGNAL ;
    PORT
      LAYER M5 ;
        RECT  232.044 189.888 232.068 190.08 ;
    END
  END s1__pv2[127]
  PIN s1__pv2[128]
    DIRECTION INPUT ;
    USE SIGNAL ;
    PORT
      LAYER M5 ;
        RECT  232.284 189.888 232.308 190.08 ;
    END
  END s1__pv2[128]
  PIN s1__pv2[129]
    DIRECTION INPUT ;
    USE SIGNAL ;
    PORT
      LAYER M5 ;
        RECT  232.476 189.888 232.5 190.08 ;
    END
  END s1__pv2[129]
  PIN s1__pv2[12]
    DIRECTION INPUT ;
    USE SIGNAL ;
    PORT
      LAYER M5 ;
        RECT  205.884 189.888 205.908 190.08 ;
    END
  END s1__pv2[12]
  PIN s1__pv2[130]
    DIRECTION INPUT ;
    USE SIGNAL ;
    PORT
      LAYER M5 ;
        RECT  232.716 189.888 232.74 190.08 ;
    END
  END s1__pv2[130]
  PIN s1__pv2[131]
    DIRECTION INPUT ;
    USE SIGNAL ;
    PORT
      LAYER M5 ;
        RECT  232.956 189.888 232.98 190.08 ;
    END
  END s1__pv2[131]
  PIN s1__pv2[132]
    DIRECTION INPUT ;
    USE SIGNAL ;
    PORT
      LAYER M5 ;
        RECT  233.196 189.888 233.22 190.08 ;
    END
  END s1__pv2[132]
  PIN s1__pv2[133]
    DIRECTION INPUT ;
    USE SIGNAL ;
    PORT
      LAYER M5 ;
        RECT  233.388 189.888 233.412 190.08 ;
    END
  END s1__pv2[133]
  PIN s1__pv2[134]
    DIRECTION INPUT ;
    USE SIGNAL ;
    PORT
      LAYER M5 ;
        RECT  233.628 189.888 233.652 190.08 ;
    END
  END s1__pv2[134]
  PIN s1__pv2[135]
    DIRECTION INPUT ;
    USE SIGNAL ;
    PORT
      LAYER M5 ;
        RECT  233.868 189.888 233.892 190.08 ;
    END
  END s1__pv2[135]
  PIN s1__pv2[136]
    DIRECTION INPUT ;
    USE SIGNAL ;
    PORT
      LAYER M5 ;
        RECT  234.108 189.888 234.132 190.08 ;
    END
  END s1__pv2[136]
  PIN s1__pv2[137]
    DIRECTION INPUT ;
    USE SIGNAL ;
    PORT
      LAYER M5 ;
        RECT  234.3 189.888 234.324 190.08 ;
    END
  END s1__pv2[137]
  PIN s1__pv2[138]
    DIRECTION INPUT ;
    USE SIGNAL ;
    PORT
      LAYER M5 ;
        RECT  234.54 189.888 234.564 190.08 ;
    END
  END s1__pv2[138]
  PIN s1__pv2[139]
    DIRECTION INPUT ;
    USE SIGNAL ;
    PORT
      LAYER M5 ;
        RECT  234.78 189.888 234.804 190.08 ;
    END
  END s1__pv2[139]
  PIN s1__pv2[13]
    DIRECTION INPUT ;
    USE SIGNAL ;
    PORT
      LAYER M5 ;
        RECT  206.124 189.888 206.148 190.08 ;
    END
  END s1__pv2[13]
  PIN s1__pv2[140]
    DIRECTION INPUT ;
    USE SIGNAL ;
    PORT
      LAYER M5 ;
        RECT  235.02 189.888 235.044 190.08 ;
    END
  END s1__pv2[140]
  PIN s1__pv2[141]
    DIRECTION INPUT ;
    USE SIGNAL ;
    PORT
      LAYER M5 ;
        RECT  235.212 189.888 235.236 190.08 ;
    END
  END s1__pv2[141]
  PIN s1__pv2[142]
    DIRECTION INPUT ;
    USE SIGNAL ;
    PORT
      LAYER M5 ;
        RECT  235.452 189.888 235.476 190.08 ;
    END
  END s1__pv2[142]
  PIN s1__pv2[143]
    DIRECTION INPUT ;
    USE SIGNAL ;
    PORT
      LAYER M5 ;
        RECT  235.692 189.888 235.716 190.08 ;
    END
  END s1__pv2[143]
  PIN s1__pv2[144]
    DIRECTION INPUT ;
    USE SIGNAL ;
    PORT
      LAYER M5 ;
        RECT  235.932 189.888 235.956 190.08 ;
    END
  END s1__pv2[144]
  PIN s1__pv2[145]
    DIRECTION INPUT ;
    USE SIGNAL ;
    PORT
      LAYER M5 ;
        RECT  236.124 189.888 236.148 190.08 ;
    END
  END s1__pv2[145]
  PIN s1__pv2[146]
    DIRECTION INPUT ;
    USE SIGNAL ;
    PORT
      LAYER M5 ;
        RECT  236.364 189.888 236.388 190.08 ;
    END
  END s1__pv2[146]
  PIN s1__pv2[147]
    DIRECTION INPUT ;
    USE SIGNAL ;
    PORT
      LAYER M5 ;
        RECT  236.604 189.888 236.628 190.08 ;
    END
  END s1__pv2[147]
  PIN s1__pv2[148]
    DIRECTION INPUT ;
    USE SIGNAL ;
    PORT
      LAYER M5 ;
        RECT  236.844 189.888 236.868 190.08 ;
    END
  END s1__pv2[148]
  PIN s1__pv2[149]
    DIRECTION INPUT ;
    USE SIGNAL ;
    PORT
      LAYER M5 ;
        RECT  237.036 189.888 237.06 190.08 ;
    END
  END s1__pv2[149]
  PIN s1__pv2[14]
    DIRECTION INPUT ;
    USE SIGNAL ;
    PORT
      LAYER M5 ;
        RECT  206.316 189.888 206.34 190.08 ;
    END
  END s1__pv2[14]
  PIN s1__pv2[150]
    DIRECTION INPUT ;
    USE SIGNAL ;
    PORT
      LAYER M5 ;
        RECT  237.276 189.888 237.3 190.08 ;
    END
  END s1__pv2[150]
  PIN s1__pv2[151]
    DIRECTION INPUT ;
    USE SIGNAL ;
    PORT
      LAYER M5 ;
        RECT  237.516 189.888 237.54 190.08 ;
    END
  END s1__pv2[151]
  PIN s1__pv2[152]
    DIRECTION INPUT ;
    USE SIGNAL ;
    PORT
      LAYER M5 ;
        RECT  237.708 189.888 237.732 190.08 ;
    END
  END s1__pv2[152]
  PIN s1__pv2[153]
    DIRECTION INPUT ;
    USE SIGNAL ;
    PORT
      LAYER M5 ;
        RECT  237.948 189.888 237.972 190.08 ;
    END
  END s1__pv2[153]
  PIN s1__pv2[154]
    DIRECTION INPUT ;
    USE SIGNAL ;
    PORT
      LAYER M5 ;
        RECT  238.188 189.888 238.212 190.08 ;
    END
  END s1__pv2[154]
  PIN s1__pv2[155]
    DIRECTION INPUT ;
    USE SIGNAL ;
    PORT
      LAYER M5 ;
        RECT  238.428 189.888 238.452 190.08 ;
    END
  END s1__pv2[155]
  PIN s1__pv2[156]
    DIRECTION INPUT ;
    USE SIGNAL ;
    PORT
      LAYER M5 ;
        RECT  238.62 189.888 238.644 190.08 ;
    END
  END s1__pv2[156]
  PIN s1__pv2[157]
    DIRECTION INPUT ;
    USE SIGNAL ;
    PORT
      LAYER M5 ;
        RECT  238.86 189.888 238.884 190.08 ;
    END
  END s1__pv2[157]
  PIN s1__pv2[158]
    DIRECTION INPUT ;
    USE SIGNAL ;
    PORT
      LAYER M5 ;
        RECT  239.1 189.888 239.124 190.08 ;
    END
  END s1__pv2[158]
  PIN s1__pv2[159]
    DIRECTION INPUT ;
    USE SIGNAL ;
    PORT
      LAYER M5 ;
        RECT  239.34 189.888 239.364 190.08 ;
    END
  END s1__pv2[159]
  PIN s1__pv2[15]
    DIRECTION INPUT ;
    USE SIGNAL ;
    PORT
      LAYER M5 ;
        RECT  206.556 189.888 206.58 190.08 ;
    END
  END s1__pv2[15]
  PIN s1__pv2[160]
    DIRECTION INPUT ;
    USE SIGNAL ;
    PORT
      LAYER M5 ;
        RECT  239.532 189.888 239.556 190.08 ;
    END
  END s1__pv2[160]
  PIN s1__pv2[161]
    DIRECTION INPUT ;
    USE SIGNAL ;
    PORT
      LAYER M5 ;
        RECT  239.772 189.888 239.796 190.08 ;
    END
  END s1__pv2[161]
  PIN s1__pv2[162]
    DIRECTION INPUT ;
    USE SIGNAL ;
    PORT
      LAYER M5 ;
        RECT  240.012 189.888 240.036 190.08 ;
    END
  END s1__pv2[162]
  PIN s1__pv2[163]
    DIRECTION INPUT ;
    USE SIGNAL ;
    PORT
      LAYER M5 ;
        RECT  240.252 189.888 240.276 190.08 ;
    END
  END s1__pv2[163]
  PIN s1__pv2[164]
    DIRECTION INPUT ;
    USE SIGNAL ;
    PORT
      LAYER M5 ;
        RECT  240.444 189.888 240.468 190.08 ;
    END
  END s1__pv2[164]
  PIN s1__pv2[165]
    DIRECTION INPUT ;
    USE SIGNAL ;
    PORT
      LAYER M5 ;
        RECT  240.684 189.888 240.708 190.08 ;
    END
  END s1__pv2[165]
  PIN s1__pv2[166]
    DIRECTION INPUT ;
    USE SIGNAL ;
    PORT
      LAYER M5 ;
        RECT  240.924 189.888 240.948 190.08 ;
    END
  END s1__pv2[166]
  PIN s1__pv2[167]
    DIRECTION INPUT ;
    USE SIGNAL ;
    PORT
      LAYER M5 ;
        RECT  241.164 189.888 241.188 190.08 ;
    END
  END s1__pv2[167]
  PIN s1__pv2[168]
    DIRECTION INPUT ;
    USE SIGNAL ;
    PORT
      LAYER M5 ;
        RECT  241.356 189.888 241.38 190.08 ;
    END
  END s1__pv2[168]
  PIN s1__pv2[169]
    DIRECTION INPUT ;
    USE SIGNAL ;
    PORT
      LAYER M5 ;
        RECT  241.596 189.888 241.62 190.08 ;
    END
  END s1__pv2[169]
  PIN s1__pv2[16]
    DIRECTION INPUT ;
    USE SIGNAL ;
    PORT
      LAYER M5 ;
        RECT  206.796 189.888 206.82 190.08 ;
    END
  END s1__pv2[16]
  PIN s1__pv2[170]
    DIRECTION INPUT ;
    USE SIGNAL ;
    PORT
      LAYER M5 ;
        RECT  241.836 189.888 241.86 190.08 ;
    END
  END s1__pv2[170]
  PIN s1__pv2[171]
    DIRECTION INPUT ;
    USE SIGNAL ;
    PORT
      LAYER M5 ;
        RECT  242.076 189.888 242.1 190.08 ;
    END
  END s1__pv2[171]
  PIN s1__pv2[172]
    DIRECTION INPUT ;
    USE SIGNAL ;
    PORT
      LAYER M5 ;
        RECT  242.268 189.888 242.292 190.08 ;
    END
  END s1__pv2[172]
  PIN s1__pv2[173]
    DIRECTION INPUT ;
    USE SIGNAL ;
    PORT
      LAYER M5 ;
        RECT  242.508 189.888 242.532 190.08 ;
    END
  END s1__pv2[173]
  PIN s1__pv2[174]
    DIRECTION INPUT ;
    USE SIGNAL ;
    PORT
      LAYER M5 ;
        RECT  242.748 189.888 242.772 190.08 ;
    END
  END s1__pv2[174]
  PIN s1__pv2[175]
    DIRECTION INPUT ;
    USE SIGNAL ;
    PORT
      LAYER M5 ;
        RECT  242.94 189.888 242.964 190.08 ;
    END
  END s1__pv2[175]
  PIN s1__pv2[176]
    DIRECTION INPUT ;
    USE SIGNAL ;
    PORT
      LAYER M5 ;
        RECT  243.18 189.888 243.204 190.08 ;
    END
  END s1__pv2[176]
  PIN s1__pv2[177]
    DIRECTION INPUT ;
    USE SIGNAL ;
    PORT
      LAYER M5 ;
        RECT  243.42 189.888 243.444 190.08 ;
    END
  END s1__pv2[177]
  PIN s1__pv2[178]
    DIRECTION INPUT ;
    USE SIGNAL ;
    PORT
      LAYER M5 ;
        RECT  243.66 189.888 243.684 190.08 ;
    END
  END s1__pv2[178]
  PIN s1__pv2[179]
    DIRECTION INPUT ;
    USE SIGNAL ;
    PORT
      LAYER M5 ;
        RECT  243.852 189.888 243.876 190.08 ;
    END
  END s1__pv2[179]
  PIN s1__pv2[17]
    DIRECTION INPUT ;
    USE SIGNAL ;
    PORT
      LAYER M5 ;
        RECT  207.036 189.888 207.06 190.08 ;
    END
  END s1__pv2[17]
  PIN s1__pv2[180]
    DIRECTION INPUT ;
    USE SIGNAL ;
    PORT
      LAYER M5 ;
        RECT  244.092 189.888 244.116 190.08 ;
    END
  END s1__pv2[180]
  PIN s1__pv2[181]
    DIRECTION INPUT ;
    USE SIGNAL ;
    PORT
      LAYER M5 ;
        RECT  244.332 189.888 244.356 190.08 ;
    END
  END s1__pv2[181]
  PIN s1__pv2[182]
    DIRECTION INPUT ;
    USE SIGNAL ;
    PORT
      LAYER M5 ;
        RECT  244.572 189.888 244.596 190.08 ;
    END
  END s1__pv2[182]
  PIN s1__pv2[183]
    DIRECTION INPUT ;
    USE SIGNAL ;
    PORT
      LAYER M5 ;
        RECT  244.764 189.888 244.788 190.08 ;
    END
  END s1__pv2[183]
  PIN s1__pv2[184]
    DIRECTION INPUT ;
    USE SIGNAL ;
    PORT
      LAYER M5 ;
        RECT  245.004 189.888 245.028 190.08 ;
    END
  END s1__pv2[184]
  PIN s1__pv2[185]
    DIRECTION INPUT ;
    USE SIGNAL ;
    PORT
      LAYER M5 ;
        RECT  245.244 189.888 245.268 190.08 ;
    END
  END s1__pv2[185]
  PIN s1__pv2[186]
    DIRECTION INPUT ;
    USE SIGNAL ;
    PORT
      LAYER M5 ;
        RECT  245.484 189.888 245.508 190.08 ;
    END
  END s1__pv2[186]
  PIN s1__pv2[187]
    DIRECTION INPUT ;
    USE SIGNAL ;
    PORT
      LAYER M5 ;
        RECT  245.676 189.888 245.7 190.08 ;
    END
  END s1__pv2[187]
  PIN s1__pv2[188]
    DIRECTION INPUT ;
    USE SIGNAL ;
    PORT
      LAYER M5 ;
        RECT  245.916 189.888 245.94 190.08 ;
    END
  END s1__pv2[188]
  PIN s1__pv2[189]
    DIRECTION INPUT ;
    USE SIGNAL ;
    PORT
      LAYER M5 ;
        RECT  246.156 189.888 246.18 190.08 ;
    END
  END s1__pv2[189]
  PIN s1__pv2[18]
    DIRECTION INPUT ;
    USE SIGNAL ;
    PORT
      LAYER M5 ;
        RECT  207.228 189.888 207.252 190.08 ;
    END
  END s1__pv2[18]
  PIN s1__pv2[190]
    DIRECTION INPUT ;
    USE SIGNAL ;
    PORT
      LAYER M5 ;
        RECT  246.396 189.888 246.42 190.08 ;
    END
  END s1__pv2[190]
  PIN s1__pv2[191]
    DIRECTION INPUT ;
    USE SIGNAL ;
    PORT
      LAYER M5 ;
        RECT  246.588 189.888 246.612 190.08 ;
    END
  END s1__pv2[191]
  PIN s1__pv2[192]
    DIRECTION INPUT ;
    USE SIGNAL ;
    PORT
      LAYER M5 ;
        RECT  246.828 189.888 246.852 190.08 ;
    END
  END s1__pv2[192]
  PIN s1__pv2[193]
    DIRECTION INPUT ;
    USE SIGNAL ;
    PORT
      LAYER M5 ;
        RECT  247.068 189.888 247.092 190.08 ;
    END
  END s1__pv2[193]
  PIN s1__pv2[194]
    DIRECTION INPUT ;
    USE SIGNAL ;
    PORT
      LAYER M5 ;
        RECT  247.308 189.888 247.332 190.08 ;
    END
  END s1__pv2[194]
  PIN s1__pv2[195]
    DIRECTION INPUT ;
    USE SIGNAL ;
    PORT
      LAYER M5 ;
        RECT  247.5 189.888 247.524 190.08 ;
    END
  END s1__pv2[195]
  PIN s1__pv2[196]
    DIRECTION INPUT ;
    USE SIGNAL ;
    PORT
      LAYER M5 ;
        RECT  247.74 189.888 247.764 190.08 ;
    END
  END s1__pv2[196]
  PIN s1__pv2[197]
    DIRECTION INPUT ;
    USE SIGNAL ;
    PORT
      LAYER M5 ;
        RECT  247.98 189.888 248.004 190.08 ;
    END
  END s1__pv2[197]
  PIN s1__pv2[198]
    DIRECTION INPUT ;
    USE SIGNAL ;
    PORT
      LAYER M5 ;
        RECT  248.172 189.888 248.196 190.08 ;
    END
  END s1__pv2[198]
  PIN s1__pv2[199]
    DIRECTION INPUT ;
    USE SIGNAL ;
    PORT
      LAYER M5 ;
        RECT  248.412 189.888 248.436 190.08 ;
    END
  END s1__pv2[199]
  PIN s1__pv2[19]
    DIRECTION INPUT ;
    USE SIGNAL ;
    PORT
      LAYER M5 ;
        RECT  207.468 189.888 207.492 190.08 ;
    END
  END s1__pv2[19]
  PIN s1__pv2[1]
    DIRECTION INPUT ;
    USE SIGNAL ;
    PORT
      LAYER M5 ;
        RECT  203.388 189.888 203.412 190.08 ;
    END
  END s1__pv2[1]
  PIN s1__pv2[200]
    DIRECTION INPUT ;
    USE SIGNAL ;
    PORT
      LAYER M5 ;
        RECT  248.652 189.888 248.676 190.08 ;
    END
  END s1__pv2[200]
  PIN s1__pv2[201]
    DIRECTION INPUT ;
    USE SIGNAL ;
    PORT
      LAYER M5 ;
        RECT  248.892 189.888 248.916 190.08 ;
    END
  END s1__pv2[201]
  PIN s1__pv2[202]
    DIRECTION INPUT ;
    USE SIGNAL ;
    PORT
      LAYER M5 ;
        RECT  249.084 189.888 249.108 190.08 ;
    END
  END s1__pv2[202]
  PIN s1__pv2[203]
    DIRECTION INPUT ;
    USE SIGNAL ;
    PORT
      LAYER M5 ;
        RECT  249.324 189.888 249.348 190.08 ;
    END
  END s1__pv2[203]
  PIN s1__pv2[204]
    DIRECTION INPUT ;
    USE SIGNAL ;
    PORT
      LAYER M5 ;
        RECT  249.564 189.888 249.588 190.08 ;
    END
  END s1__pv2[204]
  PIN s1__pv2[205]
    DIRECTION INPUT ;
    USE SIGNAL ;
    PORT
      LAYER M5 ;
        RECT  249.804 189.888 249.828 190.08 ;
    END
  END s1__pv2[205]
  PIN s1__pv2[206]
    DIRECTION INPUT ;
    USE SIGNAL ;
    PORT
      LAYER M5 ;
        RECT  249.996 189.888 250.02 190.08 ;
    END
  END s1__pv2[206]
  PIN s1__pv2[207]
    DIRECTION INPUT ;
    USE SIGNAL ;
    PORT
      LAYER M5 ;
        RECT  250.236 189.888 250.26 190.08 ;
    END
  END s1__pv2[207]
  PIN s1__pv2[208]
    DIRECTION INPUT ;
    USE SIGNAL ;
    PORT
      LAYER M5 ;
        RECT  250.476 189.888 250.5 190.08 ;
    END
  END s1__pv2[208]
  PIN s1__pv2[209]
    DIRECTION INPUT ;
    USE SIGNAL ;
    PORT
      LAYER M5 ;
        RECT  250.716 189.888 250.74 190.08 ;
    END
  END s1__pv2[209]
  PIN s1__pv2[20]
    DIRECTION INPUT ;
    USE SIGNAL ;
    PORT
      LAYER M5 ;
        RECT  207.708 189.888 207.732 190.08 ;
    END
  END s1__pv2[20]
  PIN s1__pv2[210]
    DIRECTION INPUT ;
    USE SIGNAL ;
    PORT
      LAYER M5 ;
        RECT  250.908 189.888 250.932 190.08 ;
    END
  END s1__pv2[210]
  PIN s1__pv2[211]
    DIRECTION INPUT ;
    USE SIGNAL ;
    PORT
      LAYER M5 ;
        RECT  251.148 189.888 251.172 190.08 ;
    END
  END s1__pv2[211]
  PIN s1__pv2[212]
    DIRECTION INPUT ;
    USE SIGNAL ;
    PORT
      LAYER M5 ;
        RECT  251.388 189.888 251.412 190.08 ;
    END
  END s1__pv2[212]
  PIN s1__pv2[213]
    DIRECTION INPUT ;
    USE SIGNAL ;
    PORT
      LAYER M5 ;
        RECT  251.628 189.888 251.652 190.08 ;
    END
  END s1__pv2[213]
  PIN s1__pv2[214]
    DIRECTION INPUT ;
    USE SIGNAL ;
    PORT
      LAYER M5 ;
        RECT  251.82 189.888 251.844 190.08 ;
    END
  END s1__pv2[214]
  PIN s1__pv2[215]
    DIRECTION INPUT ;
    USE SIGNAL ;
    PORT
      LAYER M5 ;
        RECT  252.06 189.888 252.084 190.08 ;
    END
  END s1__pv2[215]
  PIN s1__pv2[216]
    DIRECTION INPUT ;
    USE SIGNAL ;
    PORT
      LAYER M5 ;
        RECT  252.3 189.888 252.324 190.08 ;
    END
  END s1__pv2[216]
  PIN s1__pv2[217]
    DIRECTION INPUT ;
    USE SIGNAL ;
    PORT
      LAYER M5 ;
        RECT  252.54 189.888 252.564 190.08 ;
    END
  END s1__pv2[217]
  PIN s1__pv2[218]
    DIRECTION INPUT ;
    USE SIGNAL ;
    PORT
      LAYER M5 ;
        RECT  252.732 189.888 252.756 190.08 ;
    END
  END s1__pv2[218]
  PIN s1__pv2[219]
    DIRECTION INPUT ;
    USE SIGNAL ;
    PORT
      LAYER M5 ;
        RECT  252.972 189.888 252.996 190.08 ;
    END
  END s1__pv2[219]
  PIN s1__pv2[21]
    DIRECTION INPUT ;
    USE SIGNAL ;
    PORT
      LAYER M5 ;
        RECT  207.948 189.888 207.972 190.08 ;
    END
  END s1__pv2[21]
  PIN s1__pv2[220]
    DIRECTION INPUT ;
    USE SIGNAL ;
    PORT
      LAYER M5 ;
        RECT  253.212 189.888 253.236 190.08 ;
    END
  END s1__pv2[220]
  PIN s1__pv2[221]
    DIRECTION INPUT ;
    USE SIGNAL ;
    PORT
      LAYER M5 ;
        RECT  253.452 189.888 253.476 190.08 ;
    END
  END s1__pv2[221]
  PIN s1__pv2[222]
    DIRECTION INPUT ;
    USE SIGNAL ;
    PORT
      LAYER M5 ;
        RECT  253.644 189.888 253.668 190.08 ;
    END
  END s1__pv2[222]
  PIN s1__pv2[223]
    DIRECTION INPUT ;
    USE SIGNAL ;
    PORT
      LAYER M5 ;
        RECT  253.884 189.888 253.908 190.08 ;
    END
  END s1__pv2[223]
  PIN s1__pv2[224]
    DIRECTION INPUT ;
    USE SIGNAL ;
    PORT
      LAYER M5 ;
        RECT  254.124 189.888 254.148 190.08 ;
    END
  END s1__pv2[224]
  PIN s1__pv2[225]
    DIRECTION INPUT ;
    USE SIGNAL ;
    PORT
      LAYER M5 ;
        RECT  254.316 189.888 254.34 190.08 ;
    END
  END s1__pv2[225]
  PIN s1__pv2[226]
    DIRECTION INPUT ;
    USE SIGNAL ;
    PORT
      LAYER M5 ;
        RECT  254.556 189.888 254.58 190.08 ;
    END
  END s1__pv2[226]
  PIN s1__pv2[227]
    DIRECTION INPUT ;
    USE SIGNAL ;
    PORT
      LAYER M5 ;
        RECT  254.796 189.888 254.82 190.08 ;
    END
  END s1__pv2[227]
  PIN s1__pv2[228]
    DIRECTION INPUT ;
    USE SIGNAL ;
    PORT
      LAYER M5 ;
        RECT  255.036 189.888 255.06 190.08 ;
    END
  END s1__pv2[228]
  PIN s1__pv2[229]
    DIRECTION INPUT ;
    USE SIGNAL ;
    PORT
      LAYER M5 ;
        RECT  255.228 189.888 255.252 190.08 ;
    END
  END s1__pv2[229]
  PIN s1__pv2[22]
    DIRECTION INPUT ;
    USE SIGNAL ;
    PORT
      LAYER M5 ;
        RECT  208.14 189.888 208.164 190.08 ;
    END
  END s1__pv2[22]
  PIN s1__pv2[230]
    DIRECTION INPUT ;
    USE SIGNAL ;
    PORT
      LAYER M5 ;
        RECT  255.468 189.888 255.492 190.08 ;
    END
  END s1__pv2[230]
  PIN s1__pv2[231]
    DIRECTION INPUT ;
    USE SIGNAL ;
    PORT
      LAYER M5 ;
        RECT  255.708 189.888 255.732 190.08 ;
    END
  END s1__pv2[231]
  PIN s1__pv2[232]
    DIRECTION INPUT ;
    USE SIGNAL ;
    PORT
      LAYER M5 ;
        RECT  255.948 189.888 255.972 190.08 ;
    END
  END s1__pv2[232]
  PIN s1__pv2[233]
    DIRECTION INPUT ;
    USE SIGNAL ;
    PORT
      LAYER M5 ;
        RECT  256.14 189.888 256.164 190.08 ;
    END
  END s1__pv2[233]
  PIN s1__pv2[234]
    DIRECTION INPUT ;
    USE SIGNAL ;
    PORT
      LAYER M5 ;
        RECT  256.38 189.888 256.404 190.08 ;
    END
  END s1__pv2[234]
  PIN s1__pv2[235]
    DIRECTION INPUT ;
    USE SIGNAL ;
    PORT
      LAYER M5 ;
        RECT  256.62 189.888 256.644 190.08 ;
    END
  END s1__pv2[235]
  PIN s1__pv2[236]
    DIRECTION INPUT ;
    USE SIGNAL ;
    PORT
      LAYER M5 ;
        RECT  256.86 189.888 256.884 190.08 ;
    END
  END s1__pv2[236]
  PIN s1__pv2[237]
    DIRECTION INPUT ;
    USE SIGNAL ;
    PORT
      LAYER M5 ;
        RECT  257.052 189.888 257.076 190.08 ;
    END
  END s1__pv2[237]
  PIN s1__pv2[238]
    DIRECTION INPUT ;
    USE SIGNAL ;
    PORT
      LAYER M5 ;
        RECT  257.292 189.888 257.316 190.08 ;
    END
  END s1__pv2[238]
  PIN s1__pv2[239]
    DIRECTION INPUT ;
    USE SIGNAL ;
    PORT
      LAYER M5 ;
        RECT  257.532 189.888 257.556 190.08 ;
    END
  END s1__pv2[239]
  PIN s1__pv2[23]
    DIRECTION INPUT ;
    USE SIGNAL ;
    PORT
      LAYER M5 ;
        RECT  208.38 189.888 208.404 190.08 ;
    END
  END s1__pv2[23]
  PIN s1__pv2[240]
    DIRECTION INPUT ;
    USE SIGNAL ;
    PORT
      LAYER M5 ;
        RECT  257.772 189.888 257.796 190.08 ;
    END
  END s1__pv2[240]
  PIN s1__pv2[241]
    DIRECTION INPUT ;
    USE SIGNAL ;
    PORT
      LAYER M5 ;
        RECT  257.964 189.888 257.988 190.08 ;
    END
  END s1__pv2[241]
  PIN s1__pv2[242]
    DIRECTION INPUT ;
    USE SIGNAL ;
    PORT
      LAYER M5 ;
        RECT  258.204 189.888 258.228 190.08 ;
    END
  END s1__pv2[242]
  PIN s1__pv2[243]
    DIRECTION INPUT ;
    USE SIGNAL ;
    PORT
      LAYER M5 ;
        RECT  258.444 189.888 258.468 190.08 ;
    END
  END s1__pv2[243]
  PIN s1__pv2[244]
    DIRECTION INPUT ;
    USE SIGNAL ;
    PORT
      LAYER M5 ;
        RECT  258.684 189.888 258.708 190.08 ;
    END
  END s1__pv2[244]
  PIN s1__pv2[245]
    DIRECTION INPUT ;
    USE SIGNAL ;
    PORT
      LAYER M5 ;
        RECT  258.876 189.888 258.9 190.08 ;
    END
  END s1__pv2[245]
  PIN s1__pv2[246]
    DIRECTION INPUT ;
    USE SIGNAL ;
    PORT
      LAYER M5 ;
        RECT  259.116 189.888 259.14 190.08 ;
    END
  END s1__pv2[246]
  PIN s1__pv2[247]
    DIRECTION INPUT ;
    USE SIGNAL ;
    PORT
      LAYER M5 ;
        RECT  259.356 189.888 259.38 190.08 ;
    END
  END s1__pv2[247]
  PIN s1__pv2[248]
    DIRECTION INPUT ;
    USE SIGNAL ;
    PORT
      LAYER M5 ;
        RECT  259.548 189.888 259.572 190.08 ;
    END
  END s1__pv2[248]
  PIN s1__pv2[249]
    DIRECTION INPUT ;
    USE SIGNAL ;
    PORT
      LAYER M5 ;
        RECT  259.788 189.888 259.812 190.08 ;
    END
  END s1__pv2[249]
  PIN s1__pv2[24]
    DIRECTION INPUT ;
    USE SIGNAL ;
    PORT
      LAYER M5 ;
        RECT  208.62 189.888 208.644 190.08 ;
    END
  END s1__pv2[24]
  PIN s1__pv2[250]
    DIRECTION INPUT ;
    USE SIGNAL ;
    PORT
      LAYER M5 ;
        RECT  260.028 189.888 260.052 190.08 ;
    END
  END s1__pv2[250]
  PIN s1__pv2[251]
    DIRECTION INPUT ;
    USE SIGNAL ;
    PORT
      LAYER M5 ;
        RECT  260.268 189.888 260.292 190.08 ;
    END
  END s1__pv2[251]
  PIN s1__pv2[252]
    DIRECTION INPUT ;
    USE SIGNAL ;
    PORT
      LAYER M5 ;
        RECT  260.46 189.888 260.484 190.08 ;
    END
  END s1__pv2[252]
  PIN s1__pv2[253]
    DIRECTION INPUT ;
    USE SIGNAL ;
    PORT
      LAYER M5 ;
        RECT  260.7 189.888 260.724 190.08 ;
    END
  END s1__pv2[253]
  PIN s1__pv2[254]
    DIRECTION INPUT ;
    USE SIGNAL ;
    PORT
      LAYER M5 ;
        RECT  260.94 189.888 260.964 190.08 ;
    END
  END s1__pv2[254]
  PIN s1__pv2[255]
    DIRECTION INPUT ;
    USE SIGNAL ;
    PORT
      LAYER M5 ;
        RECT  261.18 189.888 261.204 190.08 ;
    END
  END s1__pv2[255]
  PIN s1__pv2[25]
    DIRECTION INPUT ;
    USE SIGNAL ;
    PORT
      LAYER M5 ;
        RECT  208.86 189.888 208.884 190.08 ;
    END
  END s1__pv2[25]
  PIN s1__pv2[26]
    DIRECTION INPUT ;
    USE SIGNAL ;
    PORT
      LAYER M5 ;
        RECT  209.052 189.888 209.076 190.08 ;
    END
  END s1__pv2[26]
  PIN s1__pv2[27]
    DIRECTION INPUT ;
    USE SIGNAL ;
    PORT
      LAYER M5 ;
        RECT  209.292 189.888 209.316 190.08 ;
    END
  END s1__pv2[27]
  PIN s1__pv2[28]
    DIRECTION INPUT ;
    USE SIGNAL ;
    PORT
      LAYER M5 ;
        RECT  209.532 189.888 209.556 190.08 ;
    END
  END s1__pv2[28]
  PIN s1__pv2[29]
    DIRECTION INPUT ;
    USE SIGNAL ;
    PORT
      LAYER M5 ;
        RECT  209.724 189.888 209.748 190.08 ;
    END
  END s1__pv2[29]
  PIN s1__pv2[2]
    DIRECTION INPUT ;
    USE SIGNAL ;
    PORT
      LAYER M5 ;
        RECT  203.628 189.888 203.652 190.08 ;
    END
  END s1__pv2[2]
  PIN s1__pv2[30]
    DIRECTION INPUT ;
    USE SIGNAL ;
    PORT
      LAYER M5 ;
        RECT  209.964 189.888 209.988 190.08 ;
    END
  END s1__pv2[30]
  PIN s1__pv2[31]
    DIRECTION INPUT ;
    USE SIGNAL ;
    PORT
      LAYER M5 ;
        RECT  210.204 189.888 210.228 190.08 ;
    END
  END s1__pv2[31]
  PIN s1__pv2[32]
    DIRECTION INPUT ;
    USE SIGNAL ;
    PORT
      LAYER M5 ;
        RECT  210.444 189.888 210.468 190.08 ;
    END
  END s1__pv2[32]
  PIN s1__pv2[33]
    DIRECTION INPUT ;
    USE SIGNAL ;
    PORT
      LAYER M5 ;
        RECT  210.636 189.888 210.66 190.08 ;
    END
  END s1__pv2[33]
  PIN s1__pv2[34]
    DIRECTION INPUT ;
    USE SIGNAL ;
    PORT
      LAYER M5 ;
        RECT  210.876 189.888 210.9 190.08 ;
    END
  END s1__pv2[34]
  PIN s1__pv2[35]
    DIRECTION INPUT ;
    USE SIGNAL ;
    PORT
      LAYER M5 ;
        RECT  211.116 189.888 211.14 190.08 ;
    END
  END s1__pv2[35]
  PIN s1__pv2[36]
    DIRECTION INPUT ;
    USE SIGNAL ;
    PORT
      LAYER M5 ;
        RECT  211.356 189.888 211.38 190.08 ;
    END
  END s1__pv2[36]
  PIN s1__pv2[37]
    DIRECTION INPUT ;
    USE SIGNAL ;
    PORT
      LAYER M5 ;
        RECT  211.548 189.888 211.572 190.08 ;
    END
  END s1__pv2[37]
  PIN s1__pv2[38]
    DIRECTION INPUT ;
    USE SIGNAL ;
    PORT
      LAYER M5 ;
        RECT  211.788 189.888 211.812 190.08 ;
    END
  END s1__pv2[38]
  PIN s1__pv2[39]
    DIRECTION INPUT ;
    USE SIGNAL ;
    PORT
      LAYER M5 ;
        RECT  212.028 189.888 212.052 190.08 ;
    END
  END s1__pv2[39]
  PIN s1__pv2[3]
    DIRECTION INPUT ;
    USE SIGNAL ;
    PORT
      LAYER M5 ;
        RECT  203.82 189.888 203.844 190.08 ;
    END
  END s1__pv2[3]
  PIN s1__pv2[40]
    DIRECTION INPUT ;
    USE SIGNAL ;
    PORT
      LAYER M5 ;
        RECT  212.268 189.888 212.292 190.08 ;
    END
  END s1__pv2[40]
  PIN s1__pv2[41]
    DIRECTION INPUT ;
    USE SIGNAL ;
    PORT
      LAYER M5 ;
        RECT  212.46 189.888 212.484 190.08 ;
    END
  END s1__pv2[41]
  PIN s1__pv2[42]
    DIRECTION INPUT ;
    USE SIGNAL ;
    PORT
      LAYER M5 ;
        RECT  212.7 189.888 212.724 190.08 ;
    END
  END s1__pv2[42]
  PIN s1__pv2[43]
    DIRECTION INPUT ;
    USE SIGNAL ;
    PORT
      LAYER M5 ;
        RECT  212.94 189.888 212.964 190.08 ;
    END
  END s1__pv2[43]
  PIN s1__pv2[44]
    DIRECTION INPUT ;
    USE SIGNAL ;
    PORT
      LAYER M5 ;
        RECT  213.18 189.888 213.204 190.08 ;
    END
  END s1__pv2[44]
  PIN s1__pv2[45]
    DIRECTION INPUT ;
    USE SIGNAL ;
    PORT
      LAYER M5 ;
        RECT  213.372 189.888 213.396 190.08 ;
    END
  END s1__pv2[45]
  PIN s1__pv2[46]
    DIRECTION INPUT ;
    USE SIGNAL ;
    PORT
      LAYER M5 ;
        RECT  213.612 189.888 213.636 190.08 ;
    END
  END s1__pv2[46]
  PIN s1__pv2[47]
    DIRECTION INPUT ;
    USE SIGNAL ;
    PORT
      LAYER M5 ;
        RECT  213.852 189.888 213.876 190.08 ;
    END
  END s1__pv2[47]
  PIN s1__pv2[48]
    DIRECTION INPUT ;
    USE SIGNAL ;
    PORT
      LAYER M5 ;
        RECT  214.092 189.888 214.116 190.08 ;
    END
  END s1__pv2[48]
  PIN s1__pv2[49]
    DIRECTION INPUT ;
    USE SIGNAL ;
    PORT
      LAYER M5 ;
        RECT  214.284 189.888 214.308 190.08 ;
    END
  END s1__pv2[49]
  PIN s1__pv2[4]
    DIRECTION INPUT ;
    USE SIGNAL ;
    PORT
      LAYER M5 ;
        RECT  204.06 189.888 204.084 190.08 ;
    END
  END s1__pv2[4]
  PIN s1__pv2[50]
    DIRECTION INPUT ;
    USE SIGNAL ;
    PORT
      LAYER M5 ;
        RECT  214.524 189.888 214.548 190.08 ;
    END
  END s1__pv2[50]
  PIN s1__pv2[51]
    DIRECTION INPUT ;
    USE SIGNAL ;
    PORT
      LAYER M5 ;
        RECT  214.764 189.888 214.788 190.08 ;
    END
  END s1__pv2[51]
  PIN s1__pv2[52]
    DIRECTION INPUT ;
    USE SIGNAL ;
    PORT
      LAYER M5 ;
        RECT  214.956 189.888 214.98 190.08 ;
    END
  END s1__pv2[52]
  PIN s1__pv2[53]
    DIRECTION INPUT ;
    USE SIGNAL ;
    PORT
      LAYER M5 ;
        RECT  215.196 189.888 215.22 190.08 ;
    END
  END s1__pv2[53]
  PIN s1__pv2[54]
    DIRECTION INPUT ;
    USE SIGNAL ;
    PORT
      LAYER M5 ;
        RECT  215.436 189.888 215.46 190.08 ;
    END
  END s1__pv2[54]
  PIN s1__pv2[55]
    DIRECTION INPUT ;
    USE SIGNAL ;
    PORT
      LAYER M5 ;
        RECT  215.676 189.888 215.7 190.08 ;
    END
  END s1__pv2[55]
  PIN s1__pv2[56]
    DIRECTION INPUT ;
    USE SIGNAL ;
    PORT
      LAYER M5 ;
        RECT  215.868 189.888 215.892 190.08 ;
    END
  END s1__pv2[56]
  PIN s1__pv2[57]
    DIRECTION INPUT ;
    USE SIGNAL ;
    PORT
      LAYER M5 ;
        RECT  216.108 189.888 216.132 190.08 ;
    END
  END s1__pv2[57]
  PIN s1__pv2[58]
    DIRECTION INPUT ;
    USE SIGNAL ;
    PORT
      LAYER M5 ;
        RECT  216.348 189.888 216.372 190.08 ;
    END
  END s1__pv2[58]
  PIN s1__pv2[59]
    DIRECTION INPUT ;
    USE SIGNAL ;
    PORT
      LAYER M5 ;
        RECT  216.588 189.888 216.612 190.08 ;
    END
  END s1__pv2[59]
  PIN s1__pv2[5]
    DIRECTION INPUT ;
    USE SIGNAL ;
    PORT
      LAYER M5 ;
        RECT  204.3 189.888 204.324 190.08 ;
    END
  END s1__pv2[5]
  PIN s1__pv2[60]
    DIRECTION INPUT ;
    USE SIGNAL ;
    PORT
      LAYER M5 ;
        RECT  216.78 189.888 216.804 190.08 ;
    END
  END s1__pv2[60]
  PIN s1__pv2[61]
    DIRECTION INPUT ;
    USE SIGNAL ;
    PORT
      LAYER M5 ;
        RECT  217.02 189.888 217.044 190.08 ;
    END
  END s1__pv2[61]
  PIN s1__pv2[62]
    DIRECTION INPUT ;
    USE SIGNAL ;
    PORT
      LAYER M5 ;
        RECT  217.26 189.888 217.284 190.08 ;
    END
  END s1__pv2[62]
  PIN s1__pv2[63]
    DIRECTION INPUT ;
    USE SIGNAL ;
    PORT
      LAYER M5 ;
        RECT  217.5 189.888 217.524 190.08 ;
    END
  END s1__pv2[63]
  PIN s1__pv2[64]
    DIRECTION INPUT ;
    USE SIGNAL ;
    PORT
      LAYER M5 ;
        RECT  217.692 189.888 217.716 190.08 ;
    END
  END s1__pv2[64]
  PIN s1__pv2[65]
    DIRECTION INPUT ;
    USE SIGNAL ;
    PORT
      LAYER M5 ;
        RECT  217.932 189.888 217.956 190.08 ;
    END
  END s1__pv2[65]
  PIN s1__pv2[66]
    DIRECTION INPUT ;
    USE SIGNAL ;
    PORT
      LAYER M5 ;
        RECT  218.172 189.888 218.196 190.08 ;
    END
  END s1__pv2[66]
  PIN s1__pv2[67]
    DIRECTION INPUT ;
    USE SIGNAL ;
    PORT
      LAYER M5 ;
        RECT  218.412 189.888 218.436 190.08 ;
    END
  END s1__pv2[67]
  PIN s1__pv2[68]
    DIRECTION INPUT ;
    USE SIGNAL ;
    PORT
      LAYER M5 ;
        RECT  218.604 189.888 218.628 190.08 ;
    END
  END s1__pv2[68]
  PIN s1__pv2[69]
    DIRECTION INPUT ;
    USE SIGNAL ;
    PORT
      LAYER M5 ;
        RECT  218.844 189.888 218.868 190.08 ;
    END
  END s1__pv2[69]
  PIN s1__pv2[6]
    DIRECTION INPUT ;
    USE SIGNAL ;
    PORT
      LAYER M5 ;
        RECT  204.492 189.888 204.516 190.08 ;
    END
  END s1__pv2[6]
  PIN s1__pv2[70]
    DIRECTION INPUT ;
    USE SIGNAL ;
    PORT
      LAYER M5 ;
        RECT  219.084 189.888 219.108 190.08 ;
    END
  END s1__pv2[70]
  PIN s1__pv2[71]
    DIRECTION INPUT ;
    USE SIGNAL ;
    PORT
      LAYER M5 ;
        RECT  219.324 189.888 219.348 190.08 ;
    END
  END s1__pv2[71]
  PIN s1__pv2[72]
    DIRECTION INPUT ;
    USE SIGNAL ;
    PORT
      LAYER M5 ;
        RECT  219.516 189.888 219.54 190.08 ;
    END
  END s1__pv2[72]
  PIN s1__pv2[73]
    DIRECTION INPUT ;
    USE SIGNAL ;
    PORT
      LAYER M5 ;
        RECT  219.756 189.888 219.78 190.08 ;
    END
  END s1__pv2[73]
  PIN s1__pv2[74]
    DIRECTION INPUT ;
    USE SIGNAL ;
    PORT
      LAYER M5 ;
        RECT  219.996 189.888 220.02 190.08 ;
    END
  END s1__pv2[74]
  PIN s1__pv2[75]
    DIRECTION INPUT ;
    USE SIGNAL ;
    PORT
      LAYER M5 ;
        RECT  220.236 189.888 220.26 190.08 ;
    END
  END s1__pv2[75]
  PIN s1__pv2[76]
    DIRECTION INPUT ;
    USE SIGNAL ;
    PORT
      LAYER M5 ;
        RECT  220.428 189.888 220.452 190.08 ;
    END
  END s1__pv2[76]
  PIN s1__pv2[77]
    DIRECTION INPUT ;
    USE SIGNAL ;
    PORT
      LAYER M5 ;
        RECT  220.668 189.888 220.692 190.08 ;
    END
  END s1__pv2[77]
  PIN s1__pv2[78]
    DIRECTION INPUT ;
    USE SIGNAL ;
    PORT
      LAYER M5 ;
        RECT  220.908 189.888 220.932 190.08 ;
    END
  END s1__pv2[78]
  PIN s1__pv2[79]
    DIRECTION INPUT ;
    USE SIGNAL ;
    PORT
      LAYER M5 ;
        RECT  221.1 189.888 221.124 190.08 ;
    END
  END s1__pv2[79]
  PIN s1__pv2[7]
    DIRECTION INPUT ;
    USE SIGNAL ;
    PORT
      LAYER M5 ;
        RECT  204.732 189.888 204.756 190.08 ;
    END
  END s1__pv2[7]
  PIN s1__pv2[80]
    DIRECTION INPUT ;
    USE SIGNAL ;
    PORT
      LAYER M5 ;
        RECT  221.34 189.888 221.364 190.08 ;
    END
  END s1__pv2[80]
  PIN s1__pv2[81]
    DIRECTION INPUT ;
    USE SIGNAL ;
    PORT
      LAYER M5 ;
        RECT  221.58 189.888 221.604 190.08 ;
    END
  END s1__pv2[81]
  PIN s1__pv2[82]
    DIRECTION INPUT ;
    USE SIGNAL ;
    PORT
      LAYER M5 ;
        RECT  221.82 189.888 221.844 190.08 ;
    END
  END s1__pv2[82]
  PIN s1__pv2[83]
    DIRECTION INPUT ;
    USE SIGNAL ;
    PORT
      LAYER M5 ;
        RECT  222.012 189.888 222.036 190.08 ;
    END
  END s1__pv2[83]
  PIN s1__pv2[84]
    DIRECTION INPUT ;
    USE SIGNAL ;
    PORT
      LAYER M5 ;
        RECT  222.252 189.888 222.276 190.08 ;
    END
  END s1__pv2[84]
  PIN s1__pv2[85]
    DIRECTION INPUT ;
    USE SIGNAL ;
    PORT
      LAYER M5 ;
        RECT  222.492 189.888 222.516 190.08 ;
    END
  END s1__pv2[85]
  PIN s1__pv2[86]
    DIRECTION INPUT ;
    USE SIGNAL ;
    PORT
      LAYER M5 ;
        RECT  222.732 189.888 222.756 190.08 ;
    END
  END s1__pv2[86]
  PIN s1__pv2[87]
    DIRECTION INPUT ;
    USE SIGNAL ;
    PORT
      LAYER M5 ;
        RECT  222.924 189.888 222.948 190.08 ;
    END
  END s1__pv2[87]
  PIN s1__pv2[88]
    DIRECTION INPUT ;
    USE SIGNAL ;
    PORT
      LAYER M5 ;
        RECT  223.164 189.888 223.188 190.08 ;
    END
  END s1__pv2[88]
  PIN s1__pv2[89]
    DIRECTION INPUT ;
    USE SIGNAL ;
    PORT
      LAYER M5 ;
        RECT  223.404 189.888 223.428 190.08 ;
    END
  END s1__pv2[89]
  PIN s1__pv2[8]
    DIRECTION INPUT ;
    USE SIGNAL ;
    PORT
      LAYER M5 ;
        RECT  204.972 189.888 204.996 190.08 ;
    END
  END s1__pv2[8]
  PIN s1__pv2[90]
    DIRECTION INPUT ;
    USE SIGNAL ;
    PORT
      LAYER M5 ;
        RECT  223.644 189.888 223.668 190.08 ;
    END
  END s1__pv2[90]
  PIN s1__pv2[91]
    DIRECTION INPUT ;
    USE SIGNAL ;
    PORT
      LAYER M5 ;
        RECT  223.836 189.888 223.86 190.08 ;
    END
  END s1__pv2[91]
  PIN s1__pv2[92]
    DIRECTION INPUT ;
    USE SIGNAL ;
    PORT
      LAYER M5 ;
        RECT  224.076 189.888 224.1 190.08 ;
    END
  END s1__pv2[92]
  PIN s1__pv2[93]
    DIRECTION INPUT ;
    USE SIGNAL ;
    PORT
      LAYER M5 ;
        RECT  224.316 189.888 224.34 190.08 ;
    END
  END s1__pv2[93]
  PIN s1__pv2[94]
    DIRECTION INPUT ;
    USE SIGNAL ;
    PORT
      LAYER M5 ;
        RECT  224.556 189.888 224.58 190.08 ;
    END
  END s1__pv2[94]
  PIN s1__pv2[95]
    DIRECTION INPUT ;
    USE SIGNAL ;
    PORT
      LAYER M5 ;
        RECT  224.748 189.888 224.772 190.08 ;
    END
  END s1__pv2[95]
  PIN s1__pv2[96]
    DIRECTION INPUT ;
    USE SIGNAL ;
    PORT
      LAYER M5 ;
        RECT  224.988 189.888 225.012 190.08 ;
    END
  END s1__pv2[96]
  PIN s1__pv2[97]
    DIRECTION INPUT ;
    USE SIGNAL ;
    PORT
      LAYER M5 ;
        RECT  225.228 189.888 225.252 190.08 ;
    END
  END s1__pv2[97]
  PIN s1__pv2[98]
    DIRECTION INPUT ;
    USE SIGNAL ;
    PORT
      LAYER M5 ;
        RECT  225.468 189.888 225.492 190.08 ;
    END
  END s1__pv2[98]
  PIN s1__pv2[99]
    DIRECTION INPUT ;
    USE SIGNAL ;
    PORT
      LAYER M5 ;
        RECT  225.66 189.888 225.684 190.08 ;
    END
  END s1__pv2[99]
  PIN s1__pv2[9]
    DIRECTION INPUT ;
    USE SIGNAL ;
    PORT
      LAYER M5 ;
        RECT  205.212 189.888 205.236 190.08 ;
    END
  END s1__pv2[9]
  PIN s1__rst_n[0]
    DIRECTION INPUT ;
    USE SIGNAL ;
    PORT
      LAYER M5 ;
        RECT  261.372 189.888 261.396 190.08 ;
    END
  END s1__rst_n[0]
  PIN s1__ts[0]
    DIRECTION OUTPUT ;
    USE SIGNAL ;
    PORT
      LAYER M5 ;
        RECT  261.612 189.888 261.636 190.08 ;
    END
  END s1__ts[0]
  PIN s1__ts[100]
    DIRECTION OUTPUT ;
    USE SIGNAL ;
    PORT
      LAYER M5 ;
        RECT  284.364 189.888 284.388 190.08 ;
    END
  END s1__ts[100]
  PIN s1__ts[101]
    DIRECTION OUTPUT ;
    USE SIGNAL ;
    PORT
      LAYER M5 ;
        RECT  284.604 189.888 284.628 190.08 ;
    END
  END s1__ts[101]
  PIN s1__ts[102]
    DIRECTION OUTPUT ;
    USE SIGNAL ;
    PORT
      LAYER M5 ;
        RECT  284.844 189.888 284.868 190.08 ;
    END
  END s1__ts[102]
  PIN s1__ts[103]
    DIRECTION OUTPUT ;
    USE SIGNAL ;
    PORT
      LAYER M5 ;
        RECT  285.036 189.888 285.06 190.08 ;
    END
  END s1__ts[103]
  PIN s1__ts[104]
    DIRECTION OUTPUT ;
    USE SIGNAL ;
    PORT
      LAYER M5 ;
        RECT  285.276 189.888 285.3 190.08 ;
    END
  END s1__ts[104]
  PIN s1__ts[105]
    DIRECTION OUTPUT ;
    USE SIGNAL ;
    PORT
      LAYER M5 ;
        RECT  285.516 189.888 285.54 190.08 ;
    END
  END s1__ts[105]
  PIN s1__ts[106]
    DIRECTION OUTPUT ;
    USE SIGNAL ;
    PORT
      LAYER M5 ;
        RECT  285.756 189.888 285.78 190.08 ;
    END
  END s1__ts[106]
  PIN s1__ts[107]
    DIRECTION OUTPUT ;
    USE SIGNAL ;
    PORT
      LAYER M5 ;
        RECT  285.948 189.888 285.972 190.08 ;
    END
  END s1__ts[107]
  PIN s1__ts[108]
    DIRECTION OUTPUT ;
    USE SIGNAL ;
    PORT
      LAYER M5 ;
        RECT  286.188 189.888 286.212 190.08 ;
    END
  END s1__ts[108]
  PIN s1__ts[109]
    DIRECTION OUTPUT ;
    USE SIGNAL ;
    PORT
      LAYER M5 ;
        RECT  286.428 189.888 286.452 190.08 ;
    END
  END s1__ts[109]
  PIN s1__ts[10]
    DIRECTION OUTPUT ;
    USE SIGNAL ;
    PORT
      LAYER M5 ;
        RECT  263.916 189.888 263.94 190.08 ;
    END
  END s1__ts[10]
  PIN s1__ts[110]
    DIRECTION OUTPUT ;
    USE SIGNAL ;
    PORT
      LAYER M5 ;
        RECT  286.668 189.888 286.692 190.08 ;
    END
  END s1__ts[110]
  PIN s1__ts[111]
    DIRECTION OUTPUT ;
    USE SIGNAL ;
    PORT
      LAYER M5 ;
        RECT  286.86 189.888 286.884 190.08 ;
    END
  END s1__ts[111]
  PIN s1__ts[112]
    DIRECTION OUTPUT ;
    USE SIGNAL ;
    PORT
      LAYER M5 ;
        RECT  287.1 189.888 287.124 190.08 ;
    END
  END s1__ts[112]
  PIN s1__ts[113]
    DIRECTION OUTPUT ;
    USE SIGNAL ;
    PORT
      LAYER M5 ;
        RECT  287.34 189.888 287.364 190.08 ;
    END
  END s1__ts[113]
  PIN s1__ts[114]
    DIRECTION OUTPUT ;
    USE SIGNAL ;
    PORT
      LAYER M5 ;
        RECT  287.532 189.888 287.556 190.08 ;
    END
  END s1__ts[114]
  PIN s1__ts[115]
    DIRECTION OUTPUT ;
    USE SIGNAL ;
    PORT
      LAYER M5 ;
        RECT  287.772 189.888 287.796 190.08 ;
    END
  END s1__ts[115]
  PIN s1__ts[116]
    DIRECTION OUTPUT ;
    USE SIGNAL ;
    PORT
      LAYER M5 ;
        RECT  288.012 189.888 288.036 190.08 ;
    END
  END s1__ts[116]
  PIN s1__ts[117]
    DIRECTION OUTPUT ;
    USE SIGNAL ;
    PORT
      LAYER M5 ;
        RECT  288.252 189.888 288.276 190.08 ;
    END
  END s1__ts[117]
  PIN s1__ts[118]
    DIRECTION OUTPUT ;
    USE SIGNAL ;
    PORT
      LAYER M5 ;
        RECT  288.444 189.888 288.468 190.08 ;
    END
  END s1__ts[118]
  PIN s1__ts[119]
    DIRECTION OUTPUT ;
    USE SIGNAL ;
    PORT
      LAYER M5 ;
        RECT  288.684 189.888 288.708 190.08 ;
    END
  END s1__ts[119]
  PIN s1__ts[11]
    DIRECTION OUTPUT ;
    USE SIGNAL ;
    PORT
      LAYER M5 ;
        RECT  264.108 189.888 264.132 190.08 ;
    END
  END s1__ts[11]
  PIN s1__ts[120]
    DIRECTION OUTPUT ;
    USE SIGNAL ;
    PORT
      LAYER M5 ;
        RECT  288.924 189.888 288.948 190.08 ;
    END
  END s1__ts[120]
  PIN s1__ts[121]
    DIRECTION OUTPUT ;
    USE SIGNAL ;
    PORT
      LAYER M5 ;
        RECT  289.164 189.888 289.188 190.08 ;
    END
  END s1__ts[121]
  PIN s1__ts[122]
    DIRECTION OUTPUT ;
    USE SIGNAL ;
    PORT
      LAYER M5 ;
        RECT  289.356 189.888 289.38 190.08 ;
    END
  END s1__ts[122]
  PIN s1__ts[123]
    DIRECTION OUTPUT ;
    USE SIGNAL ;
    PORT
      LAYER M5 ;
        RECT  289.596 189.888 289.62 190.08 ;
    END
  END s1__ts[123]
  PIN s1__ts[124]
    DIRECTION OUTPUT ;
    USE SIGNAL ;
    PORT
      LAYER M5 ;
        RECT  289.836 189.888 289.86 190.08 ;
    END
  END s1__ts[124]
  PIN s1__ts[125]
    DIRECTION OUTPUT ;
    USE SIGNAL ;
    PORT
      LAYER M5 ;
        RECT  290.076 189.888 290.1 190.08 ;
    END
  END s1__ts[125]
  PIN s1__ts[126]
    DIRECTION OUTPUT ;
    USE SIGNAL ;
    PORT
      LAYER M5 ;
        RECT  290.268 189.888 290.292 190.08 ;
    END
  END s1__ts[126]
  PIN s1__ts[127]
    DIRECTION OUTPUT ;
    USE SIGNAL ;
    PORT
      LAYER M5 ;
        RECT  290.508 189.888 290.532 190.08 ;
    END
  END s1__ts[127]
  PIN s1__ts[128]
    DIRECTION OUTPUT ;
    USE SIGNAL ;
    PORT
      LAYER M5 ;
        RECT  290.748 189.888 290.772 190.08 ;
    END
  END s1__ts[128]
  PIN s1__ts[129]
    DIRECTION OUTPUT ;
    USE SIGNAL ;
    PORT
      LAYER M5 ;
        RECT  290.988 189.888 291.012 190.08 ;
    END
  END s1__ts[129]
  PIN s1__ts[12]
    DIRECTION OUTPUT ;
    USE SIGNAL ;
    PORT
      LAYER M5 ;
        RECT  264.348 189.888 264.372 190.08 ;
    END
  END s1__ts[12]
  PIN s1__ts[130]
    DIRECTION OUTPUT ;
    USE SIGNAL ;
    PORT
      LAYER M5 ;
        RECT  291.18 189.888 291.204 190.08 ;
    END
  END s1__ts[130]
  PIN s1__ts[131]
    DIRECTION OUTPUT ;
    USE SIGNAL ;
    PORT
      LAYER M5 ;
        RECT  291.42 189.888 291.444 190.08 ;
    END
  END s1__ts[131]
  PIN s1__ts[132]
    DIRECTION OUTPUT ;
    USE SIGNAL ;
    PORT
      LAYER M5 ;
        RECT  291.66 189.888 291.684 190.08 ;
    END
  END s1__ts[132]
  PIN s1__ts[133]
    DIRECTION OUTPUT ;
    USE SIGNAL ;
    PORT
      LAYER M5 ;
        RECT  291.9 189.888 291.924 190.08 ;
    END
  END s1__ts[133]
  PIN s1__ts[134]
    DIRECTION OUTPUT ;
    USE SIGNAL ;
    PORT
      LAYER M5 ;
        RECT  292.092 189.888 292.116 190.08 ;
    END
  END s1__ts[134]
  PIN s1__ts[135]
    DIRECTION OUTPUT ;
    USE SIGNAL ;
    PORT
      LAYER M5 ;
        RECT  292.332 189.888 292.356 190.08 ;
    END
  END s1__ts[135]
  PIN s1__ts[136]
    DIRECTION OUTPUT ;
    USE SIGNAL ;
    PORT
      LAYER M5 ;
        RECT  292.572 189.888 292.596 190.08 ;
    END
  END s1__ts[136]
  PIN s1__ts[137]
    DIRECTION OUTPUT ;
    USE SIGNAL ;
    PORT
      LAYER M5 ;
        RECT  292.764 189.888 292.788 190.08 ;
    END
  END s1__ts[137]
  PIN s1__ts[138]
    DIRECTION OUTPUT ;
    USE SIGNAL ;
    PORT
      LAYER M5 ;
        RECT  293.004 189.888 293.028 190.08 ;
    END
  END s1__ts[138]
  PIN s1__ts[139]
    DIRECTION OUTPUT ;
    USE SIGNAL ;
    PORT
      LAYER M5 ;
        RECT  293.244 189.888 293.268 190.08 ;
    END
  END s1__ts[139]
  PIN s1__ts[13]
    DIRECTION OUTPUT ;
    USE SIGNAL ;
    PORT
      LAYER M5 ;
        RECT  264.588 189.888 264.612 190.08 ;
    END
  END s1__ts[13]
  PIN s1__ts[140]
    DIRECTION OUTPUT ;
    USE SIGNAL ;
    PORT
      LAYER M5 ;
        RECT  293.484 189.888 293.508 190.08 ;
    END
  END s1__ts[140]
  PIN s1__ts[141]
    DIRECTION OUTPUT ;
    USE SIGNAL ;
    PORT
      LAYER M5 ;
        RECT  293.676 189.888 293.7 190.08 ;
    END
  END s1__ts[141]
  PIN s1__ts[142]
    DIRECTION OUTPUT ;
    USE SIGNAL ;
    PORT
      LAYER M5 ;
        RECT  293.916 189.888 293.94 190.08 ;
    END
  END s1__ts[142]
  PIN s1__ts[143]
    DIRECTION OUTPUT ;
    USE SIGNAL ;
    PORT
      LAYER M5 ;
        RECT  294.156 189.888 294.18 190.08 ;
    END
  END s1__ts[143]
  PIN s1__ts[144]
    DIRECTION OUTPUT ;
    USE SIGNAL ;
    PORT
      LAYER M5 ;
        RECT  294.396 189.888 294.42 190.08 ;
    END
  END s1__ts[144]
  PIN s1__ts[145]
    DIRECTION OUTPUT ;
    USE SIGNAL ;
    PORT
      LAYER M5 ;
        RECT  294.588 189.888 294.612 190.08 ;
    END
  END s1__ts[145]
  PIN s1__ts[146]
    DIRECTION OUTPUT ;
    USE SIGNAL ;
    PORT
      LAYER M5 ;
        RECT  294.828 189.888 294.852 190.08 ;
    END
  END s1__ts[146]
  PIN s1__ts[147]
    DIRECTION OUTPUT ;
    USE SIGNAL ;
    PORT
      LAYER M5 ;
        RECT  295.068 189.888 295.092 190.08 ;
    END
  END s1__ts[147]
  PIN s1__ts[148]
    DIRECTION OUTPUT ;
    USE SIGNAL ;
    PORT
      LAYER M5 ;
        RECT  295.308 189.888 295.332 190.08 ;
    END
  END s1__ts[148]
  PIN s1__ts[149]
    DIRECTION OUTPUT ;
    USE SIGNAL ;
    PORT
      LAYER M5 ;
        RECT  295.5 189.888 295.524 190.08 ;
    END
  END s1__ts[149]
  PIN s1__ts[14]
    DIRECTION OUTPUT ;
    USE SIGNAL ;
    PORT
      LAYER M5 ;
        RECT  264.78 189.888 264.804 190.08 ;
    END
  END s1__ts[14]
  PIN s1__ts[150]
    DIRECTION OUTPUT ;
    USE SIGNAL ;
    PORT
      LAYER M5 ;
        RECT  295.74 189.888 295.764 190.08 ;
    END
  END s1__ts[150]
  PIN s1__ts[151]
    DIRECTION OUTPUT ;
    USE SIGNAL ;
    PORT
      LAYER M5 ;
        RECT  295.98 189.888 296.004 190.08 ;
    END
  END s1__ts[151]
  PIN s1__ts[152]
    DIRECTION OUTPUT ;
    USE SIGNAL ;
    PORT
      LAYER M5 ;
        RECT  296.22 189.888 296.244 190.08 ;
    END
  END s1__ts[152]
  PIN s1__ts[153]
    DIRECTION OUTPUT ;
    USE SIGNAL ;
    PORT
      LAYER M5 ;
        RECT  296.412 189.888 296.436 190.08 ;
    END
  END s1__ts[153]
  PIN s1__ts[154]
    DIRECTION OUTPUT ;
    USE SIGNAL ;
    PORT
      LAYER M5 ;
        RECT  296.652 189.888 296.676 190.08 ;
    END
  END s1__ts[154]
  PIN s1__ts[155]
    DIRECTION OUTPUT ;
    USE SIGNAL ;
    PORT
      LAYER M5 ;
        RECT  296.892 189.888 296.916 190.08 ;
    END
  END s1__ts[155]
  PIN s1__ts[156]
    DIRECTION OUTPUT ;
    USE SIGNAL ;
    PORT
      LAYER M5 ;
        RECT  297.132 189.888 297.156 190.08 ;
    END
  END s1__ts[156]
  PIN s1__ts[157]
    DIRECTION OUTPUT ;
    USE SIGNAL ;
    PORT
      LAYER M5 ;
        RECT  297.324 189.888 297.348 190.08 ;
    END
  END s1__ts[157]
  PIN s1__ts[158]
    DIRECTION OUTPUT ;
    USE SIGNAL ;
    PORT
      LAYER M5 ;
        RECT  297.564 189.888 297.588 190.08 ;
    END
  END s1__ts[158]
  PIN s1__ts[159]
    DIRECTION OUTPUT ;
    USE SIGNAL ;
    PORT
      LAYER M5 ;
        RECT  297.804 189.888 297.828 190.08 ;
    END
  END s1__ts[159]
  PIN s1__ts[15]
    DIRECTION OUTPUT ;
    USE SIGNAL ;
    PORT
      LAYER M5 ;
        RECT  265.02 189.888 265.044 190.08 ;
    END
  END s1__ts[15]
  PIN s1__ts[160]
    DIRECTION OUTPUT ;
    USE SIGNAL ;
    PORT
      LAYER M5 ;
        RECT  297.996 189.888 298.02 190.08 ;
    END
  END s1__ts[160]
  PIN s1__ts[161]
    DIRECTION OUTPUT ;
    USE SIGNAL ;
    PORT
      LAYER M5 ;
        RECT  298.236 189.888 298.26 190.08 ;
    END
  END s1__ts[161]
  PIN s1__ts[162]
    DIRECTION OUTPUT ;
    USE SIGNAL ;
    PORT
      LAYER M5 ;
        RECT  298.476 189.888 298.5 190.08 ;
    END
  END s1__ts[162]
  PIN s1__ts[163]
    DIRECTION OUTPUT ;
    USE SIGNAL ;
    PORT
      LAYER M5 ;
        RECT  298.716 189.888 298.74 190.08 ;
    END
  END s1__ts[163]
  PIN s1__ts[164]
    DIRECTION OUTPUT ;
    USE SIGNAL ;
    PORT
      LAYER M5 ;
        RECT  298.908 189.888 298.932 190.08 ;
    END
  END s1__ts[164]
  PIN s1__ts[165]
    DIRECTION OUTPUT ;
    USE SIGNAL ;
    PORT
      LAYER M5 ;
        RECT  299.148 189.888 299.172 190.08 ;
    END
  END s1__ts[165]
  PIN s1__ts[166]
    DIRECTION OUTPUT ;
    USE SIGNAL ;
    PORT
      LAYER M5 ;
        RECT  299.388 189.888 299.412 190.08 ;
    END
  END s1__ts[166]
  PIN s1__ts[167]
    DIRECTION OUTPUT ;
    USE SIGNAL ;
    PORT
      LAYER M5 ;
        RECT  299.628 189.888 299.652 190.08 ;
    END
  END s1__ts[167]
  PIN s1__ts[168]
    DIRECTION OUTPUT ;
    USE SIGNAL ;
    PORT
      LAYER M5 ;
        RECT  299.82 189.888 299.844 190.08 ;
    END
  END s1__ts[168]
  PIN s1__ts[169]
    DIRECTION OUTPUT ;
    USE SIGNAL ;
    PORT
      LAYER M5 ;
        RECT  300.06 189.888 300.084 190.08 ;
    END
  END s1__ts[169]
  PIN s1__ts[16]
    DIRECTION OUTPUT ;
    USE SIGNAL ;
    PORT
      LAYER M5 ;
        RECT  265.26 189.888 265.284 190.08 ;
    END
  END s1__ts[16]
  PIN s1__ts[170]
    DIRECTION OUTPUT ;
    USE SIGNAL ;
    PORT
      LAYER M5 ;
        RECT  300.3 189.888 300.324 190.08 ;
    END
  END s1__ts[170]
  PIN s1__ts[171]
    DIRECTION OUTPUT ;
    USE SIGNAL ;
    PORT
      LAYER M5 ;
        RECT  300.54 189.888 300.564 190.08 ;
    END
  END s1__ts[171]
  PIN s1__ts[172]
    DIRECTION OUTPUT ;
    USE SIGNAL ;
    PORT
      LAYER M5 ;
        RECT  300.732 189.888 300.756 190.08 ;
    END
  END s1__ts[172]
  PIN s1__ts[173]
    DIRECTION OUTPUT ;
    USE SIGNAL ;
    PORT
      LAYER M5 ;
        RECT  300.972 189.888 300.996 190.08 ;
    END
  END s1__ts[173]
  PIN s1__ts[174]
    DIRECTION OUTPUT ;
    USE SIGNAL ;
    PORT
      LAYER M5 ;
        RECT  301.212 189.888 301.236 190.08 ;
    END
  END s1__ts[174]
  PIN s1__ts[175]
    DIRECTION OUTPUT ;
    USE SIGNAL ;
    PORT
      LAYER M5 ;
        RECT  301.452 189.888 301.476 190.08 ;
    END
  END s1__ts[175]
  PIN s1__ts[176]
    DIRECTION OUTPUT ;
    USE SIGNAL ;
    PORT
      LAYER M5 ;
        RECT  301.644 189.888 301.668 190.08 ;
    END
  END s1__ts[176]
  PIN s1__ts[177]
    DIRECTION OUTPUT ;
    USE SIGNAL ;
    PORT
      LAYER M5 ;
        RECT  301.884 189.888 301.908 190.08 ;
    END
  END s1__ts[177]
  PIN s1__ts[178]
    DIRECTION OUTPUT ;
    USE SIGNAL ;
    PORT
      LAYER M5 ;
        RECT  302.124 189.888 302.148 190.08 ;
    END
  END s1__ts[178]
  PIN s1__ts[179]
    DIRECTION OUTPUT ;
    USE SIGNAL ;
    PORT
      LAYER M5 ;
        RECT  302.364 189.888 302.388 190.08 ;
    END
  END s1__ts[179]
  PIN s1__ts[17]
    DIRECTION OUTPUT ;
    USE SIGNAL ;
    PORT
      LAYER M5 ;
        RECT  265.5 189.888 265.524 190.08 ;
    END
  END s1__ts[17]
  PIN s1__ts[180]
    DIRECTION OUTPUT ;
    USE SIGNAL ;
    PORT
      LAYER M5 ;
        RECT  302.556 189.888 302.58 190.08 ;
    END
  END s1__ts[180]
  PIN s1__ts[181]
    DIRECTION OUTPUT ;
    USE SIGNAL ;
    PORT
      LAYER M5 ;
        RECT  302.796 189.888 302.82 190.08 ;
    END
  END s1__ts[181]
  PIN s1__ts[182]
    DIRECTION OUTPUT ;
    USE SIGNAL ;
    PORT
      LAYER M5 ;
        RECT  303.036 189.888 303.06 190.08 ;
    END
  END s1__ts[182]
  PIN s1__ts[183]
    DIRECTION OUTPUT ;
    USE SIGNAL ;
    PORT
      LAYER M5 ;
        RECT  303.276 189.888 303.3 190.08 ;
    END
  END s1__ts[183]
  PIN s1__ts[184]
    DIRECTION OUTPUT ;
    USE SIGNAL ;
    PORT
      LAYER M5 ;
        RECT  303.468 189.888 303.492 190.08 ;
    END
  END s1__ts[184]
  PIN s1__ts[185]
    DIRECTION OUTPUT ;
    USE SIGNAL ;
    PORT
      LAYER M5 ;
        RECT  303.708 189.888 303.732 190.08 ;
    END
  END s1__ts[185]
  PIN s1__ts[186]
    DIRECTION OUTPUT ;
    USE SIGNAL ;
    PORT
      LAYER M5 ;
        RECT  303.948 189.888 303.972 190.08 ;
    END
  END s1__ts[186]
  PIN s1__ts[187]
    DIRECTION OUTPUT ;
    USE SIGNAL ;
    PORT
      LAYER M5 ;
        RECT  304.14 189.888 304.164 190.08 ;
    END
  END s1__ts[187]
  PIN s1__ts[188]
    DIRECTION OUTPUT ;
    USE SIGNAL ;
    PORT
      LAYER M5 ;
        RECT  304.38 189.888 304.404 190.08 ;
    END
  END s1__ts[188]
  PIN s1__ts[189]
    DIRECTION OUTPUT ;
    USE SIGNAL ;
    PORT
      LAYER M5 ;
        RECT  304.62 189.888 304.644 190.08 ;
    END
  END s1__ts[189]
  PIN s1__ts[18]
    DIRECTION OUTPUT ;
    USE SIGNAL ;
    PORT
      LAYER M5 ;
        RECT  265.692 189.888 265.716 190.08 ;
    END
  END s1__ts[18]
  PIN s1__ts[190]
    DIRECTION OUTPUT ;
    USE SIGNAL ;
    PORT
      LAYER M5 ;
        RECT  304.86 189.888 304.884 190.08 ;
    END
  END s1__ts[190]
  PIN s1__ts[191]
    DIRECTION OUTPUT ;
    USE SIGNAL ;
    PORT
      LAYER M5 ;
        RECT  305.052 189.888 305.076 190.08 ;
    END
  END s1__ts[191]
  PIN s1__ts[192]
    DIRECTION OUTPUT ;
    USE SIGNAL ;
    PORT
      LAYER M5 ;
        RECT  305.292 189.888 305.316 190.08 ;
    END
  END s1__ts[192]
  PIN s1__ts[193]
    DIRECTION OUTPUT ;
    USE SIGNAL ;
    PORT
      LAYER M5 ;
        RECT  305.532 189.888 305.556 190.08 ;
    END
  END s1__ts[193]
  PIN s1__ts[194]
    DIRECTION OUTPUT ;
    USE SIGNAL ;
    PORT
      LAYER M5 ;
        RECT  305.772 189.888 305.796 190.08 ;
    END
  END s1__ts[194]
  PIN s1__ts[195]
    DIRECTION OUTPUT ;
    USE SIGNAL ;
    PORT
      LAYER M5 ;
        RECT  305.964 189.888 305.988 190.08 ;
    END
  END s1__ts[195]
  PIN s1__ts[196]
    DIRECTION OUTPUT ;
    USE SIGNAL ;
    PORT
      LAYER M5 ;
        RECT  306.204 189.888 306.228 190.08 ;
    END
  END s1__ts[196]
  PIN s1__ts[197]
    DIRECTION OUTPUT ;
    USE SIGNAL ;
    PORT
      LAYER M5 ;
        RECT  306.444 189.888 306.468 190.08 ;
    END
  END s1__ts[197]
  PIN s1__ts[198]
    DIRECTION OUTPUT ;
    USE SIGNAL ;
    PORT
      LAYER M5 ;
        RECT  306.684 189.888 306.708 190.08 ;
    END
  END s1__ts[198]
  PIN s1__ts[199]
    DIRECTION OUTPUT ;
    USE SIGNAL ;
    PORT
      LAYER M5 ;
        RECT  306.876 189.888 306.9 190.08 ;
    END
  END s1__ts[199]
  PIN s1__ts[19]
    DIRECTION OUTPUT ;
    USE SIGNAL ;
    PORT
      LAYER M5 ;
        RECT  265.932 189.888 265.956 190.08 ;
    END
  END s1__ts[19]
  PIN s1__ts[1]
    DIRECTION OUTPUT ;
    USE SIGNAL ;
    PORT
      LAYER M5 ;
        RECT  261.852 189.888 261.876 190.08 ;
    END
  END s1__ts[1]
  PIN s1__ts[200]
    DIRECTION OUTPUT ;
    USE SIGNAL ;
    PORT
      LAYER M5 ;
        RECT  307.116 189.888 307.14 190.08 ;
    END
  END s1__ts[200]
  PIN s1__ts[201]
    DIRECTION OUTPUT ;
    USE SIGNAL ;
    PORT
      LAYER M5 ;
        RECT  307.356 189.888 307.38 190.08 ;
    END
  END s1__ts[201]
  PIN s1__ts[202]
    DIRECTION OUTPUT ;
    USE SIGNAL ;
    PORT
      LAYER M5 ;
        RECT  307.596 189.888 307.62 190.08 ;
    END
  END s1__ts[202]
  PIN s1__ts[203]
    DIRECTION OUTPUT ;
    USE SIGNAL ;
    PORT
      LAYER M5 ;
        RECT  307.788 189.888 307.812 190.08 ;
    END
  END s1__ts[203]
  PIN s1__ts[204]
    DIRECTION OUTPUT ;
    USE SIGNAL ;
    PORT
      LAYER M5 ;
        RECT  308.028 189.888 308.052 190.08 ;
    END
  END s1__ts[204]
  PIN s1__ts[205]
    DIRECTION OUTPUT ;
    USE SIGNAL ;
    PORT
      LAYER M5 ;
        RECT  308.268 189.888 308.292 190.08 ;
    END
  END s1__ts[205]
  PIN s1__ts[206]
    DIRECTION OUTPUT ;
    USE SIGNAL ;
    PORT
      LAYER M5 ;
        RECT  308.508 189.888 308.532 190.08 ;
    END
  END s1__ts[206]
  PIN s1__ts[207]
    DIRECTION OUTPUT ;
    USE SIGNAL ;
    PORT
      LAYER M5 ;
        RECT  308.7 189.888 308.724 190.08 ;
    END
  END s1__ts[207]
  PIN s1__ts[208]
    DIRECTION OUTPUT ;
    USE SIGNAL ;
    PORT
      LAYER M5 ;
        RECT  308.94 189.888 308.964 190.08 ;
    END
  END s1__ts[208]
  PIN s1__ts[209]
    DIRECTION OUTPUT ;
    USE SIGNAL ;
    PORT
      LAYER M5 ;
        RECT  309.18 189.888 309.204 190.08 ;
    END
  END s1__ts[209]
  PIN s1__ts[20]
    DIRECTION OUTPUT ;
    USE SIGNAL ;
    PORT
      LAYER M5 ;
        RECT  266.172 189.888 266.196 190.08 ;
    END
  END s1__ts[20]
  PIN s1__ts[210]
    DIRECTION OUTPUT ;
    USE SIGNAL ;
    PORT
      LAYER M5 ;
        RECT  309.372 189.888 309.396 190.08 ;
    END
  END s1__ts[210]
  PIN s1__ts[211]
    DIRECTION OUTPUT ;
    USE SIGNAL ;
    PORT
      LAYER M5 ;
        RECT  309.612 189.888 309.636 190.08 ;
    END
  END s1__ts[211]
  PIN s1__ts[212]
    DIRECTION OUTPUT ;
    USE SIGNAL ;
    PORT
      LAYER M5 ;
        RECT  309.852 189.888 309.876 190.08 ;
    END
  END s1__ts[212]
  PIN s1__ts[213]
    DIRECTION OUTPUT ;
    USE SIGNAL ;
    PORT
      LAYER M5 ;
        RECT  310.092 189.888 310.116 190.08 ;
    END
  END s1__ts[213]
  PIN s1__ts[214]
    DIRECTION OUTPUT ;
    USE SIGNAL ;
    PORT
      LAYER M5 ;
        RECT  310.284 189.888 310.308 190.08 ;
    END
  END s1__ts[214]
  PIN s1__ts[215]
    DIRECTION OUTPUT ;
    USE SIGNAL ;
    PORT
      LAYER M5 ;
        RECT  310.524 189.888 310.548 190.08 ;
    END
  END s1__ts[215]
  PIN s1__ts[216]
    DIRECTION OUTPUT ;
    USE SIGNAL ;
    PORT
      LAYER M5 ;
        RECT  310.764 189.888 310.788 190.08 ;
    END
  END s1__ts[216]
  PIN s1__ts[217]
    DIRECTION OUTPUT ;
    USE SIGNAL ;
    PORT
      LAYER M5 ;
        RECT  311.004 189.888 311.028 190.08 ;
    END
  END s1__ts[217]
  PIN s1__ts[218]
    DIRECTION OUTPUT ;
    USE SIGNAL ;
    PORT
      LAYER M5 ;
        RECT  311.196 189.888 311.22 190.08 ;
    END
  END s1__ts[218]
  PIN s1__ts[219]
    DIRECTION OUTPUT ;
    USE SIGNAL ;
    PORT
      LAYER M5 ;
        RECT  311.436 189.888 311.46 190.08 ;
    END
  END s1__ts[219]
  PIN s1__ts[21]
    DIRECTION OUTPUT ;
    USE SIGNAL ;
    PORT
      LAYER M5 ;
        RECT  266.412 189.888 266.436 190.08 ;
    END
  END s1__ts[21]
  PIN s1__ts[220]
    DIRECTION OUTPUT ;
    USE SIGNAL ;
    PORT
      LAYER M5 ;
        RECT  311.676 189.888 311.7 190.08 ;
    END
  END s1__ts[220]
  PIN s1__ts[221]
    DIRECTION OUTPUT ;
    USE SIGNAL ;
    PORT
      LAYER M5 ;
        RECT  311.916 189.888 311.94 190.08 ;
    END
  END s1__ts[221]
  PIN s1__ts[222]
    DIRECTION OUTPUT ;
    USE SIGNAL ;
    PORT
      LAYER M5 ;
        RECT  312.108 189.888 312.132 190.08 ;
    END
  END s1__ts[222]
  PIN s1__ts[223]
    DIRECTION OUTPUT ;
    USE SIGNAL ;
    PORT
      LAYER M5 ;
        RECT  312.348 189.888 312.372 190.08 ;
    END
  END s1__ts[223]
  PIN s1__ts[224]
    DIRECTION OUTPUT ;
    USE SIGNAL ;
    PORT
      LAYER M5 ;
        RECT  312.588 189.888 312.612 190.08 ;
    END
  END s1__ts[224]
  PIN s1__ts[225]
    DIRECTION OUTPUT ;
    USE SIGNAL ;
    PORT
      LAYER M5 ;
        RECT  312.828 189.888 312.852 190.08 ;
    END
  END s1__ts[225]
  PIN s1__ts[226]
    DIRECTION OUTPUT ;
    USE SIGNAL ;
    PORT
      LAYER M5 ;
        RECT  313.02 189.888 313.044 190.08 ;
    END
  END s1__ts[226]
  PIN s1__ts[227]
    DIRECTION OUTPUT ;
    USE SIGNAL ;
    PORT
      LAYER M5 ;
        RECT  313.26 189.888 313.284 190.08 ;
    END
  END s1__ts[227]
  PIN s1__ts[228]
    DIRECTION OUTPUT ;
    USE SIGNAL ;
    PORT
      LAYER M5 ;
        RECT  313.5 189.888 313.524 190.08 ;
    END
  END s1__ts[228]
  PIN s1__ts[229]
    DIRECTION OUTPUT ;
    USE SIGNAL ;
    PORT
      LAYER M5 ;
        RECT  313.74 189.888 313.764 190.08 ;
    END
  END s1__ts[229]
  PIN s1__ts[22]
    DIRECTION OUTPUT ;
    USE SIGNAL ;
    PORT
      LAYER M5 ;
        RECT  266.604 189.888 266.628 190.08 ;
    END
  END s1__ts[22]
  PIN s1__ts[230]
    DIRECTION OUTPUT ;
    USE SIGNAL ;
    PORT
      LAYER M5 ;
        RECT  313.932 189.888 313.956 190.08 ;
    END
  END s1__ts[230]
  PIN s1__ts[231]
    DIRECTION OUTPUT ;
    USE SIGNAL ;
    PORT
      LAYER M5 ;
        RECT  314.172 189.888 314.196 190.08 ;
    END
  END s1__ts[231]
  PIN s1__ts[232]
    DIRECTION OUTPUT ;
    USE SIGNAL ;
    PORT
      LAYER M5 ;
        RECT  314.412 189.888 314.436 190.08 ;
    END
  END s1__ts[232]
  PIN s1__ts[233]
    DIRECTION OUTPUT ;
    USE SIGNAL ;
    PORT
      LAYER M5 ;
        RECT  314.604 189.888 314.628 190.08 ;
    END
  END s1__ts[233]
  PIN s1__ts[234]
    DIRECTION OUTPUT ;
    USE SIGNAL ;
    PORT
      LAYER M5 ;
        RECT  314.844 189.888 314.868 190.08 ;
    END
  END s1__ts[234]
  PIN s1__ts[235]
    DIRECTION OUTPUT ;
    USE SIGNAL ;
    PORT
      LAYER M5 ;
        RECT  315.084 189.888 315.108 190.08 ;
    END
  END s1__ts[235]
  PIN s1__ts[236]
    DIRECTION OUTPUT ;
    USE SIGNAL ;
    PORT
      LAYER M5 ;
        RECT  315.324 189.888 315.348 190.08 ;
    END
  END s1__ts[236]
  PIN s1__ts[237]
    DIRECTION OUTPUT ;
    USE SIGNAL ;
    PORT
      LAYER M5 ;
        RECT  315.516 189.888 315.54 190.08 ;
    END
  END s1__ts[237]
  PIN s1__ts[238]
    DIRECTION OUTPUT ;
    USE SIGNAL ;
    PORT
      LAYER M5 ;
        RECT  315.756 189.888 315.78 190.08 ;
    END
  END s1__ts[238]
  PIN s1__ts[239]
    DIRECTION OUTPUT ;
    USE SIGNAL ;
    PORT
      LAYER M5 ;
        RECT  315.996 189.888 316.02 190.08 ;
    END
  END s1__ts[239]
  PIN s1__ts[23]
    DIRECTION OUTPUT ;
    USE SIGNAL ;
    PORT
      LAYER M5 ;
        RECT  266.844 189.888 266.868 190.08 ;
    END
  END s1__ts[23]
  PIN s1__ts[240]
    DIRECTION OUTPUT ;
    USE SIGNAL ;
    PORT
      LAYER M5 ;
        RECT  316.236 189.888 316.26 190.08 ;
    END
  END s1__ts[240]
  PIN s1__ts[241]
    DIRECTION OUTPUT ;
    USE SIGNAL ;
    PORT
      LAYER M5 ;
        RECT  316.428 189.888 316.452 190.08 ;
    END
  END s1__ts[241]
  PIN s1__ts[242]
    DIRECTION OUTPUT ;
    USE SIGNAL ;
    PORT
      LAYER M5 ;
        RECT  316.668 189.888 316.692 190.08 ;
    END
  END s1__ts[242]
  PIN s1__ts[243]
    DIRECTION OUTPUT ;
    USE SIGNAL ;
    PORT
      LAYER M5 ;
        RECT  316.908 189.888 316.932 190.08 ;
    END
  END s1__ts[243]
  PIN s1__ts[244]
    DIRECTION OUTPUT ;
    USE SIGNAL ;
    PORT
      LAYER M5 ;
        RECT  317.148 189.888 317.172 190.08 ;
    END
  END s1__ts[244]
  PIN s1__ts[245]
    DIRECTION OUTPUT ;
    USE SIGNAL ;
    PORT
      LAYER M5 ;
        RECT  317.34 189.888 317.364 190.08 ;
    END
  END s1__ts[245]
  PIN s1__ts[246]
    DIRECTION OUTPUT ;
    USE SIGNAL ;
    PORT
      LAYER M5 ;
        RECT  317.58 189.888 317.604 190.08 ;
    END
  END s1__ts[246]
  PIN s1__ts[247]
    DIRECTION OUTPUT ;
    USE SIGNAL ;
    PORT
      LAYER M5 ;
        RECT  317.82 189.888 317.844 190.08 ;
    END
  END s1__ts[247]
  PIN s1__ts[248]
    DIRECTION OUTPUT ;
    USE SIGNAL ;
    PORT
      LAYER M5 ;
        RECT  318.06 189.888 318.084 190.08 ;
    END
  END s1__ts[248]
  PIN s1__ts[249]
    DIRECTION OUTPUT ;
    USE SIGNAL ;
    PORT
      LAYER M5 ;
        RECT  318.252 189.888 318.276 190.08 ;
    END
  END s1__ts[249]
  PIN s1__ts[24]
    DIRECTION OUTPUT ;
    USE SIGNAL ;
    PORT
      LAYER M5 ;
        RECT  267.084 189.888 267.108 190.08 ;
    END
  END s1__ts[24]
  PIN s1__ts[250]
    DIRECTION OUTPUT ;
    USE SIGNAL ;
    PORT
      LAYER M5 ;
        RECT  318.492 189.888 318.516 190.08 ;
    END
  END s1__ts[250]
  PIN s1__ts[251]
    DIRECTION OUTPUT ;
    USE SIGNAL ;
    PORT
      LAYER M5 ;
        RECT  318.732 189.888 318.756 190.08 ;
    END
  END s1__ts[251]
  PIN s1__ts[252]
    DIRECTION OUTPUT ;
    USE SIGNAL ;
    PORT
      LAYER M5 ;
        RECT  318.972 189.888 318.996 190.08 ;
    END
  END s1__ts[252]
  PIN s1__ts[253]
    DIRECTION OUTPUT ;
    USE SIGNAL ;
    PORT
      LAYER M5 ;
        RECT  319.164 189.888 319.188 190.08 ;
    END
  END s1__ts[253]
  PIN s1__ts[254]
    DIRECTION OUTPUT ;
    USE SIGNAL ;
    PORT
      LAYER M5 ;
        RECT  319.404 189.888 319.428 190.08 ;
    END
  END s1__ts[254]
  PIN s1__ts[255]
    DIRECTION OUTPUT ;
    USE SIGNAL ;
    PORT
      LAYER M5 ;
        RECT  319.644 189.888 319.668 190.08 ;
    END
  END s1__ts[255]
  PIN s1__ts[256]
    DIRECTION OUTPUT ;
    USE SIGNAL ;
    PORT
      LAYER M5 ;
        RECT  319.884 189.888 319.908 190.08 ;
    END
  END s1__ts[256]
  PIN s1__ts[257]
    DIRECTION OUTPUT ;
    USE SIGNAL ;
    PORT
      LAYER M5 ;
        RECT  320.076 189.888 320.1 190.08 ;
    END
  END s1__ts[257]
  PIN s1__ts[258]
    DIRECTION OUTPUT ;
    USE SIGNAL ;
    PORT
      LAYER M5 ;
        RECT  320.316 189.888 320.34 190.08 ;
    END
  END s1__ts[258]
  PIN s1__ts[259]
    DIRECTION OUTPUT ;
    USE SIGNAL ;
    PORT
      LAYER M5 ;
        RECT  320.556 189.888 320.58 190.08 ;
    END
  END s1__ts[259]
  PIN s1__ts[25]
    DIRECTION OUTPUT ;
    USE SIGNAL ;
    PORT
      LAYER M5 ;
        RECT  267.324 189.888 267.348 190.08 ;
    END
  END s1__ts[25]
  PIN s1__ts[260]
    DIRECTION OUTPUT ;
    USE SIGNAL ;
    PORT
      LAYER M5 ;
        RECT  320.748 189.888 320.772 190.08 ;
    END
  END s1__ts[260]
  PIN s1__ts[261]
    DIRECTION OUTPUT ;
    USE SIGNAL ;
    PORT
      LAYER M5 ;
        RECT  320.988 189.888 321.012 190.08 ;
    END
  END s1__ts[261]
  PIN s1__ts[262]
    DIRECTION OUTPUT ;
    USE SIGNAL ;
    PORT
      LAYER M5 ;
        RECT  321.228 189.888 321.252 190.08 ;
    END
  END s1__ts[262]
  PIN s1__ts[263]
    DIRECTION OUTPUT ;
    USE SIGNAL ;
    PORT
      LAYER M5 ;
        RECT  321.468 189.888 321.492 190.08 ;
    END
  END s1__ts[263]
  PIN s1__ts[264]
    DIRECTION OUTPUT ;
    USE SIGNAL ;
    PORT
      LAYER M5 ;
        RECT  321.66 189.888 321.684 190.08 ;
    END
  END s1__ts[264]
  PIN s1__ts[265]
    DIRECTION OUTPUT ;
    USE SIGNAL ;
    PORT
      LAYER M5 ;
        RECT  321.9 189.888 321.924 190.08 ;
    END
  END s1__ts[265]
  PIN s1__ts[266]
    DIRECTION OUTPUT ;
    USE SIGNAL ;
    PORT
      LAYER M5 ;
        RECT  322.14 189.888 322.164 190.08 ;
    END
  END s1__ts[266]
  PIN s1__ts[267]
    DIRECTION OUTPUT ;
    USE SIGNAL ;
    PORT
      LAYER M5 ;
        RECT  322.38 189.888 322.404 190.08 ;
    END
  END s1__ts[267]
  PIN s1__ts[268]
    DIRECTION OUTPUT ;
    USE SIGNAL ;
    PORT
      LAYER M5 ;
        RECT  322.572 189.888 322.596 190.08 ;
    END
  END s1__ts[268]
  PIN s1__ts[269]
    DIRECTION OUTPUT ;
    USE SIGNAL ;
    PORT
      LAYER M5 ;
        RECT  322.812 189.888 322.836 190.08 ;
    END
  END s1__ts[269]
  PIN s1__ts[26]
    DIRECTION OUTPUT ;
    USE SIGNAL ;
    PORT
      LAYER M5 ;
        RECT  267.516 189.888 267.54 190.08 ;
    END
  END s1__ts[26]
  PIN s1__ts[270]
    DIRECTION OUTPUT ;
    USE SIGNAL ;
    PORT
      LAYER M5 ;
        RECT  323.052 189.888 323.076 190.08 ;
    END
  END s1__ts[270]
  PIN s1__ts[271]
    DIRECTION OUTPUT ;
    USE SIGNAL ;
    PORT
      LAYER M5 ;
        RECT  323.292 189.888 323.316 190.08 ;
    END
  END s1__ts[271]
  PIN s1__ts[272]
    DIRECTION OUTPUT ;
    USE SIGNAL ;
    PORT
      LAYER M5 ;
        RECT  323.484 189.888 323.508 190.08 ;
    END
  END s1__ts[272]
  PIN s1__ts[273]
    DIRECTION OUTPUT ;
    USE SIGNAL ;
    PORT
      LAYER M5 ;
        RECT  323.724 189.888 323.748 190.08 ;
    END
  END s1__ts[273]
  PIN s1__ts[274]
    DIRECTION OUTPUT ;
    USE SIGNAL ;
    PORT
      LAYER M5 ;
        RECT  323.964 189.888 323.988 190.08 ;
    END
  END s1__ts[274]
  PIN s1__ts[275]
    DIRECTION OUTPUT ;
    USE SIGNAL ;
    PORT
      LAYER M5 ;
        RECT  324.204 189.888 324.228 190.08 ;
    END
  END s1__ts[275]
  PIN s1__ts[276]
    DIRECTION OUTPUT ;
    USE SIGNAL ;
    PORT
      LAYER M5 ;
        RECT  324.396 189.888 324.42 190.08 ;
    END
  END s1__ts[276]
  PIN s1__ts[277]
    DIRECTION OUTPUT ;
    USE SIGNAL ;
    PORT
      LAYER M5 ;
        RECT  324.636 189.888 324.66 190.08 ;
    END
  END s1__ts[277]
  PIN s1__ts[278]
    DIRECTION OUTPUT ;
    USE SIGNAL ;
    PORT
      LAYER M5 ;
        RECT  324.876 189.888 324.9 190.08 ;
    END
  END s1__ts[278]
  PIN s1__ts[279]
    DIRECTION OUTPUT ;
    USE SIGNAL ;
    PORT
      LAYER M5 ;
        RECT  325.116 189.888 325.14 190.08 ;
    END
  END s1__ts[279]
  PIN s1__ts[27]
    DIRECTION OUTPUT ;
    USE SIGNAL ;
    PORT
      LAYER M5 ;
        RECT  267.756 189.888 267.78 190.08 ;
    END
  END s1__ts[27]
  PIN s1__ts[280]
    DIRECTION OUTPUT ;
    USE SIGNAL ;
    PORT
      LAYER M5 ;
        RECT  325.308 189.888 325.332 190.08 ;
    END
  END s1__ts[280]
  PIN s1__ts[281]
    DIRECTION OUTPUT ;
    USE SIGNAL ;
    PORT
      LAYER M5 ;
        RECT  325.548 189.888 325.572 190.08 ;
    END
  END s1__ts[281]
  PIN s1__ts[282]
    DIRECTION OUTPUT ;
    USE SIGNAL ;
    PORT
      LAYER M5 ;
        RECT  325.788 189.888 325.812 190.08 ;
    END
  END s1__ts[282]
  PIN s1__ts[283]
    DIRECTION OUTPUT ;
    USE SIGNAL ;
    PORT
      LAYER M5 ;
        RECT  325.98 189.888 326.004 190.08 ;
    END
  END s1__ts[283]
  PIN s1__ts[284]
    DIRECTION OUTPUT ;
    USE SIGNAL ;
    PORT
      LAYER M5 ;
        RECT  326.22 189.888 326.244 190.08 ;
    END
  END s1__ts[284]
  PIN s1__ts[285]
    DIRECTION OUTPUT ;
    USE SIGNAL ;
    PORT
      LAYER M5 ;
        RECT  326.46 189.888 326.484 190.08 ;
    END
  END s1__ts[285]
  PIN s1__ts[286]
    DIRECTION OUTPUT ;
    USE SIGNAL ;
    PORT
      LAYER M5 ;
        RECT  326.7 189.888 326.724 190.08 ;
    END
  END s1__ts[286]
  PIN s1__ts[287]
    DIRECTION OUTPUT ;
    USE SIGNAL ;
    PORT
      LAYER M5 ;
        RECT  326.892 189.888 326.916 190.08 ;
    END
  END s1__ts[287]
  PIN s1__ts[288]
    DIRECTION OUTPUT ;
    USE SIGNAL ;
    PORT
      LAYER M5 ;
        RECT  327.132 189.888 327.156 190.08 ;
    END
  END s1__ts[288]
  PIN s1__ts[289]
    DIRECTION OUTPUT ;
    USE SIGNAL ;
    PORT
      LAYER M5 ;
        RECT  327.372 189.888 327.396 190.08 ;
    END
  END s1__ts[289]
  PIN s1__ts[28]
    DIRECTION OUTPUT ;
    USE SIGNAL ;
    PORT
      LAYER M5 ;
        RECT  267.996 189.888 268.02 190.08 ;
    END
  END s1__ts[28]
  PIN s1__ts[290]
    DIRECTION OUTPUT ;
    USE SIGNAL ;
    PORT
      LAYER M5 ;
        RECT  327.612 189.888 327.636 190.08 ;
    END
  END s1__ts[290]
  PIN s1__ts[291]
    DIRECTION OUTPUT ;
    USE SIGNAL ;
    PORT
      LAYER M5 ;
        RECT  327.804 189.888 327.828 190.08 ;
    END
  END s1__ts[291]
  PIN s1__ts[292]
    DIRECTION OUTPUT ;
    USE SIGNAL ;
    PORT
      LAYER M5 ;
        RECT  328.044 189.888 328.068 190.08 ;
    END
  END s1__ts[292]
  PIN s1__ts[293]
    DIRECTION OUTPUT ;
    USE SIGNAL ;
    PORT
      LAYER M5 ;
        RECT  328.284 189.888 328.308 190.08 ;
    END
  END s1__ts[293]
  PIN s1__ts[294]
    DIRECTION OUTPUT ;
    USE SIGNAL ;
    PORT
      LAYER M5 ;
        RECT  328.524 189.888 328.548 190.08 ;
    END
  END s1__ts[294]
  PIN s1__ts[295]
    DIRECTION OUTPUT ;
    USE SIGNAL ;
    PORT
      LAYER M5 ;
        RECT  328.716 189.888 328.74 190.08 ;
    END
  END s1__ts[295]
  PIN s1__ts[296]
    DIRECTION OUTPUT ;
    USE SIGNAL ;
    PORT
      LAYER M5 ;
        RECT  328.956 189.888 328.98 190.08 ;
    END
  END s1__ts[296]
  PIN s1__ts[297]
    DIRECTION OUTPUT ;
    USE SIGNAL ;
    PORT
      LAYER M5 ;
        RECT  329.196 189.888 329.22 190.08 ;
    END
  END s1__ts[297]
  PIN s1__ts[298]
    DIRECTION OUTPUT ;
    USE SIGNAL ;
    PORT
      LAYER M5 ;
        RECT  329.436 189.888 329.46 190.08 ;
    END
  END s1__ts[298]
  PIN s1__ts[299]
    DIRECTION OUTPUT ;
    USE SIGNAL ;
    PORT
      LAYER M5 ;
        RECT  329.628 189.888 329.652 190.08 ;
    END
  END s1__ts[299]
  PIN s1__ts[29]
    DIRECTION OUTPUT ;
    USE SIGNAL ;
    PORT
      LAYER M5 ;
        RECT  268.236 189.888 268.26 190.08 ;
    END
  END s1__ts[29]
  PIN s1__ts[2]
    DIRECTION OUTPUT ;
    USE SIGNAL ;
    PORT
      LAYER M5 ;
        RECT  262.092 189.888 262.116 190.08 ;
    END
  END s1__ts[2]
  PIN s1__ts[300]
    DIRECTION OUTPUT ;
    USE SIGNAL ;
    PORT
      LAYER M5 ;
        RECT  329.868 189.888 329.892 190.08 ;
    END
  END s1__ts[300]
  PIN s1__ts[301]
    DIRECTION OUTPUT ;
    USE SIGNAL ;
    PORT
      LAYER M5 ;
        RECT  330.108 189.888 330.132 190.08 ;
    END
  END s1__ts[301]
  PIN s1__ts[302]
    DIRECTION OUTPUT ;
    USE SIGNAL ;
    PORT
      LAYER M5 ;
        RECT  330.348 189.888 330.372 190.08 ;
    END
  END s1__ts[302]
  PIN s1__ts[303]
    DIRECTION OUTPUT ;
    USE SIGNAL ;
    PORT
      LAYER M5 ;
        RECT  330.54 189.888 330.564 190.08 ;
    END
  END s1__ts[303]
  PIN s1__ts[304]
    DIRECTION OUTPUT ;
    USE SIGNAL ;
    PORT
      LAYER M5 ;
        RECT  330.78 189.888 330.804 190.08 ;
    END
  END s1__ts[304]
  PIN s1__ts[305]
    DIRECTION OUTPUT ;
    USE SIGNAL ;
    PORT
      LAYER M5 ;
        RECT  331.02 189.888 331.044 190.08 ;
    END
  END s1__ts[305]
  PIN s1__ts[306]
    DIRECTION OUTPUT ;
    USE SIGNAL ;
    PORT
      LAYER M5 ;
        RECT  331.212 189.888 331.236 190.08 ;
    END
  END s1__ts[306]
  PIN s1__ts[307]
    DIRECTION OUTPUT ;
    USE SIGNAL ;
    PORT
      LAYER M5 ;
        RECT  331.452 189.888 331.476 190.08 ;
    END
  END s1__ts[307]
  PIN s1__ts[308]
    DIRECTION OUTPUT ;
    USE SIGNAL ;
    PORT
      LAYER M5 ;
        RECT  331.692 189.888 331.716 190.08 ;
    END
  END s1__ts[308]
  PIN s1__ts[309]
    DIRECTION OUTPUT ;
    USE SIGNAL ;
    PORT
      LAYER M5 ;
        RECT  331.932 189.888 331.956 190.08 ;
    END
  END s1__ts[309]
  PIN s1__ts[30]
    DIRECTION OUTPUT ;
    USE SIGNAL ;
    PORT
      LAYER M5 ;
        RECT  268.428 189.888 268.452 190.08 ;
    END
  END s1__ts[30]
  PIN s1__ts[310]
    DIRECTION OUTPUT ;
    USE SIGNAL ;
    PORT
      LAYER M5 ;
        RECT  332.124 189.888 332.148 190.08 ;
    END
  END s1__ts[310]
  PIN s1__ts[311]
    DIRECTION OUTPUT ;
    USE SIGNAL ;
    PORT
      LAYER M5 ;
        RECT  332.364 189.888 332.388 190.08 ;
    END
  END s1__ts[311]
  PIN s1__ts[312]
    DIRECTION OUTPUT ;
    USE SIGNAL ;
    PORT
      LAYER M5 ;
        RECT  332.604 189.888 332.628 190.08 ;
    END
  END s1__ts[312]
  PIN s1__ts[313]
    DIRECTION OUTPUT ;
    USE SIGNAL ;
    PORT
      LAYER M5 ;
        RECT  332.844 189.888 332.868 190.08 ;
    END
  END s1__ts[313]
  PIN s1__ts[314]
    DIRECTION OUTPUT ;
    USE SIGNAL ;
    PORT
      LAYER M5 ;
        RECT  333.036 189.888 333.06 190.08 ;
    END
  END s1__ts[314]
  PIN s1__ts[315]
    DIRECTION OUTPUT ;
    USE SIGNAL ;
    PORT
      LAYER M5 ;
        RECT  333.276 189.888 333.3 190.08 ;
    END
  END s1__ts[315]
  PIN s1__ts[316]
    DIRECTION OUTPUT ;
    USE SIGNAL ;
    PORT
      LAYER M5 ;
        RECT  333.516 189.888 333.54 190.08 ;
    END
  END s1__ts[316]
  PIN s1__ts[317]
    DIRECTION OUTPUT ;
    USE SIGNAL ;
    PORT
      LAYER M5 ;
        RECT  333.756 189.888 333.78 190.08 ;
    END
  END s1__ts[317]
  PIN s1__ts[318]
    DIRECTION OUTPUT ;
    USE SIGNAL ;
    PORT
      LAYER M5 ;
        RECT  333.948 189.888 333.972 190.08 ;
    END
  END s1__ts[318]
  PIN s1__ts[319]
    DIRECTION OUTPUT ;
    USE SIGNAL ;
    PORT
      LAYER M5 ;
        RECT  334.188 189.888 334.212 190.08 ;
    END
  END s1__ts[319]
  PIN s1__ts[31]
    DIRECTION OUTPUT ;
    USE SIGNAL ;
    PORT
      LAYER M5 ;
        RECT  268.668 189.888 268.692 190.08 ;
    END
  END s1__ts[31]
  PIN s1__ts[320]
    DIRECTION OUTPUT ;
    USE SIGNAL ;
    PORT
      LAYER M5 ;
        RECT  334.428 189.888 334.452 190.08 ;
    END
  END s1__ts[320]
  PIN s1__ts[321]
    DIRECTION OUTPUT ;
    USE SIGNAL ;
    PORT
      LAYER M5 ;
        RECT  334.668 189.888 334.692 190.08 ;
    END
  END s1__ts[321]
  PIN s1__ts[322]
    DIRECTION OUTPUT ;
    USE SIGNAL ;
    PORT
      LAYER M5 ;
        RECT  334.86 189.888 334.884 190.08 ;
    END
  END s1__ts[322]
  PIN s1__ts[323]
    DIRECTION OUTPUT ;
    USE SIGNAL ;
    PORT
      LAYER M5 ;
        RECT  335.1 189.888 335.124 190.08 ;
    END
  END s1__ts[323]
  PIN s1__ts[324]
    DIRECTION OUTPUT ;
    USE SIGNAL ;
    PORT
      LAYER M5 ;
        RECT  335.34 189.888 335.364 190.08 ;
    END
  END s1__ts[324]
  PIN s1__ts[325]
    DIRECTION OUTPUT ;
    USE SIGNAL ;
    PORT
      LAYER M5 ;
        RECT  335.58 189.888 335.604 190.08 ;
    END
  END s1__ts[325]
  PIN s1__ts[326]
    DIRECTION OUTPUT ;
    USE SIGNAL ;
    PORT
      LAYER M5 ;
        RECT  335.772 189.888 335.796 190.08 ;
    END
  END s1__ts[326]
  PIN s1__ts[327]
    DIRECTION OUTPUT ;
    USE SIGNAL ;
    PORT
      LAYER M5 ;
        RECT  336.012 189.888 336.036 190.08 ;
    END
  END s1__ts[327]
  PIN s1__ts[328]
    DIRECTION OUTPUT ;
    USE SIGNAL ;
    PORT
      LAYER M5 ;
        RECT  336.252 189.888 336.276 190.08 ;
    END
  END s1__ts[328]
  PIN s1__ts[329]
    DIRECTION OUTPUT ;
    USE SIGNAL ;
    PORT
      LAYER M5 ;
        RECT  336.492 189.888 336.516 190.08 ;
    END
  END s1__ts[329]
  PIN s1__ts[32]
    DIRECTION OUTPUT ;
    USE SIGNAL ;
    PORT
      LAYER M5 ;
        RECT  268.908 189.888 268.932 190.08 ;
    END
  END s1__ts[32]
  PIN s1__ts[330]
    DIRECTION OUTPUT ;
    USE SIGNAL ;
    PORT
      LAYER M5 ;
        RECT  336.684 189.888 336.708 190.08 ;
    END
  END s1__ts[330]
  PIN s1__ts[331]
    DIRECTION OUTPUT ;
    USE SIGNAL ;
    PORT
      LAYER M5 ;
        RECT  336.924 189.888 336.948 190.08 ;
    END
  END s1__ts[331]
  PIN s1__ts[332]
    DIRECTION OUTPUT ;
    USE SIGNAL ;
    PORT
      LAYER M5 ;
        RECT  337.164 189.888 337.188 190.08 ;
    END
  END s1__ts[332]
  PIN s1__ts[333]
    DIRECTION OUTPUT ;
    USE SIGNAL ;
    PORT
      LAYER M5 ;
        RECT  337.356 189.888 337.38 190.08 ;
    END
  END s1__ts[333]
  PIN s1__ts[334]
    DIRECTION OUTPUT ;
    USE SIGNAL ;
    PORT
      LAYER M5 ;
        RECT  337.596 189.888 337.62 190.08 ;
    END
  END s1__ts[334]
  PIN s1__ts[335]
    DIRECTION OUTPUT ;
    USE SIGNAL ;
    PORT
      LAYER M5 ;
        RECT  337.836 189.888 337.86 190.08 ;
    END
  END s1__ts[335]
  PIN s1__ts[336]
    DIRECTION OUTPUT ;
    USE SIGNAL ;
    PORT
      LAYER M5 ;
        RECT  338.076 189.888 338.1 190.08 ;
    END
  END s1__ts[336]
  PIN s1__ts[337]
    DIRECTION OUTPUT ;
    USE SIGNAL ;
    PORT
      LAYER M5 ;
        RECT  338.268 189.888 338.292 190.08 ;
    END
  END s1__ts[337]
  PIN s1__ts[338]
    DIRECTION OUTPUT ;
    USE SIGNAL ;
    PORT
      LAYER M5 ;
        RECT  338.508 189.888 338.532 190.08 ;
    END
  END s1__ts[338]
  PIN s1__ts[339]
    DIRECTION OUTPUT ;
    USE SIGNAL ;
    PORT
      LAYER M5 ;
        RECT  338.748 189.888 338.772 190.08 ;
    END
  END s1__ts[339]
  PIN s1__ts[33]
    DIRECTION OUTPUT ;
    USE SIGNAL ;
    PORT
      LAYER M5 ;
        RECT  269.148 189.888 269.172 190.08 ;
    END
  END s1__ts[33]
  PIN s1__ts[340]
    DIRECTION OUTPUT ;
    USE SIGNAL ;
    PORT
      LAYER M5 ;
        RECT  338.988 189.888 339.012 190.08 ;
    END
  END s1__ts[340]
  PIN s1__ts[341]
    DIRECTION OUTPUT ;
    USE SIGNAL ;
    PORT
      LAYER M5 ;
        RECT  339.18 189.888 339.204 190.08 ;
    END
  END s1__ts[341]
  PIN s1__ts[342]
    DIRECTION OUTPUT ;
    USE SIGNAL ;
    PORT
      LAYER M5 ;
        RECT  339.42 189.888 339.444 190.08 ;
    END
  END s1__ts[342]
  PIN s1__ts[343]
    DIRECTION OUTPUT ;
    USE SIGNAL ;
    PORT
      LAYER M5 ;
        RECT  339.66 189.888 339.684 190.08 ;
    END
  END s1__ts[343]
  PIN s1__ts[344]
    DIRECTION OUTPUT ;
    USE SIGNAL ;
    PORT
      LAYER M5 ;
        RECT  339.9 189.888 339.924 190.08 ;
    END
  END s1__ts[344]
  PIN s1__ts[345]
    DIRECTION OUTPUT ;
    USE SIGNAL ;
    PORT
      LAYER M5 ;
        RECT  340.092 189.888 340.116 190.08 ;
    END
  END s1__ts[345]
  PIN s1__ts[346]
    DIRECTION OUTPUT ;
    USE SIGNAL ;
    PORT
      LAYER M5 ;
        RECT  340.332 189.888 340.356 190.08 ;
    END
  END s1__ts[346]
  PIN s1__ts[347]
    DIRECTION OUTPUT ;
    USE SIGNAL ;
    PORT
      LAYER M5 ;
        RECT  340.572 189.888 340.596 190.08 ;
    END
  END s1__ts[347]
  PIN s1__ts[348]
    DIRECTION OUTPUT ;
    USE SIGNAL ;
    PORT
      LAYER M5 ;
        RECT  340.812 189.888 340.836 190.08 ;
    END
  END s1__ts[348]
  PIN s1__ts[349]
    DIRECTION OUTPUT ;
    USE SIGNAL ;
    PORT
      LAYER M5 ;
        RECT  341.004 189.888 341.028 190.08 ;
    END
  END s1__ts[349]
  PIN s1__ts[34]
    DIRECTION OUTPUT ;
    USE SIGNAL ;
    PORT
      LAYER M5 ;
        RECT  269.34 189.888 269.364 190.08 ;
    END
  END s1__ts[34]
  PIN s1__ts[350]
    DIRECTION OUTPUT ;
    USE SIGNAL ;
    PORT
      LAYER M5 ;
        RECT  341.244 189.888 341.268 190.08 ;
    END
  END s1__ts[350]
  PIN s1__ts[351]
    DIRECTION OUTPUT ;
    USE SIGNAL ;
    PORT
      LAYER M5 ;
        RECT  341.484 189.888 341.508 190.08 ;
    END
  END s1__ts[351]
  PIN s1__ts[352]
    DIRECTION OUTPUT ;
    USE SIGNAL ;
    PORT
      LAYER M5 ;
        RECT  341.724 189.888 341.748 190.08 ;
    END
  END s1__ts[352]
  PIN s1__ts[353]
    DIRECTION OUTPUT ;
    USE SIGNAL ;
    PORT
      LAYER M5 ;
        RECT  341.916 189.888 341.94 190.08 ;
    END
  END s1__ts[353]
  PIN s1__ts[354]
    DIRECTION OUTPUT ;
    USE SIGNAL ;
    PORT
      LAYER M5 ;
        RECT  342.156 189.888 342.18 190.08 ;
    END
  END s1__ts[354]
  PIN s1__ts[355]
    DIRECTION OUTPUT ;
    USE SIGNAL ;
    PORT
      LAYER M5 ;
        RECT  342.396 189.888 342.42 190.08 ;
    END
  END s1__ts[355]
  PIN s1__ts[356]
    DIRECTION OUTPUT ;
    USE SIGNAL ;
    PORT
      LAYER M5 ;
        RECT  342.588 189.888 342.612 190.08 ;
    END
  END s1__ts[356]
  PIN s1__ts[357]
    DIRECTION OUTPUT ;
    USE SIGNAL ;
    PORT
      LAYER M5 ;
        RECT  342.828 189.888 342.852 190.08 ;
    END
  END s1__ts[357]
  PIN s1__ts[358]
    DIRECTION OUTPUT ;
    USE SIGNAL ;
    PORT
      LAYER M5 ;
        RECT  343.068 189.888 343.092 190.08 ;
    END
  END s1__ts[358]
  PIN s1__ts[359]
    DIRECTION OUTPUT ;
    USE SIGNAL ;
    PORT
      LAYER M5 ;
        RECT  343.308 189.888 343.332 190.08 ;
    END
  END s1__ts[359]
  PIN s1__ts[35]
    DIRECTION OUTPUT ;
    USE SIGNAL ;
    PORT
      LAYER M5 ;
        RECT  269.58 189.888 269.604 190.08 ;
    END
  END s1__ts[35]
  PIN s1__ts[360]
    DIRECTION OUTPUT ;
    USE SIGNAL ;
    PORT
      LAYER M5 ;
        RECT  343.5 189.888 343.524 190.08 ;
    END
  END s1__ts[360]
  PIN s1__ts[361]
    DIRECTION OUTPUT ;
    USE SIGNAL ;
    PORT
      LAYER M5 ;
        RECT  343.74 189.888 343.764 190.08 ;
    END
  END s1__ts[361]
  PIN s1__ts[362]
    DIRECTION OUTPUT ;
    USE SIGNAL ;
    PORT
      LAYER M5 ;
        RECT  343.98 189.888 344.004 190.08 ;
    END
  END s1__ts[362]
  PIN s1__ts[363]
    DIRECTION OUTPUT ;
    USE SIGNAL ;
    PORT
      LAYER M5 ;
        RECT  344.22 189.888 344.244 190.08 ;
    END
  END s1__ts[363]
  PIN s1__ts[364]
    DIRECTION OUTPUT ;
    USE SIGNAL ;
    PORT
      LAYER M5 ;
        RECT  344.412 189.888 344.436 190.08 ;
    END
  END s1__ts[364]
  PIN s1__ts[365]
    DIRECTION OUTPUT ;
    USE SIGNAL ;
    PORT
      LAYER M5 ;
        RECT  344.652 189.888 344.676 190.08 ;
    END
  END s1__ts[365]
  PIN s1__ts[366]
    DIRECTION OUTPUT ;
    USE SIGNAL ;
    PORT
      LAYER M5 ;
        RECT  344.892 189.888 344.916 190.08 ;
    END
  END s1__ts[366]
  PIN s1__ts[367]
    DIRECTION OUTPUT ;
    USE SIGNAL ;
    PORT
      LAYER M5 ;
        RECT  345.132 189.888 345.156 190.08 ;
    END
  END s1__ts[367]
  PIN s1__ts[368]
    DIRECTION OUTPUT ;
    USE SIGNAL ;
    PORT
      LAYER M5 ;
        RECT  345.324 189.888 345.348 190.08 ;
    END
  END s1__ts[368]
  PIN s1__ts[369]
    DIRECTION OUTPUT ;
    USE SIGNAL ;
    PORT
      LAYER M5 ;
        RECT  345.564 189.888 345.588 190.08 ;
    END
  END s1__ts[369]
  PIN s1__ts[36]
    DIRECTION OUTPUT ;
    USE SIGNAL ;
    PORT
      LAYER M5 ;
        RECT  269.82 189.888 269.844 190.08 ;
    END
  END s1__ts[36]
  PIN s1__ts[370]
    DIRECTION OUTPUT ;
    USE SIGNAL ;
    PORT
      LAYER M5 ;
        RECT  345.804 189.888 345.828 190.08 ;
    END
  END s1__ts[370]
  PIN s1__ts[371]
    DIRECTION OUTPUT ;
    USE SIGNAL ;
    PORT
      LAYER M5 ;
        RECT  346.044 189.888 346.068 190.08 ;
    END
  END s1__ts[371]
  PIN s1__ts[372]
    DIRECTION OUTPUT ;
    USE SIGNAL ;
    PORT
      LAYER M5 ;
        RECT  346.236 189.888 346.26 190.08 ;
    END
  END s1__ts[372]
  PIN s1__ts[373]
    DIRECTION OUTPUT ;
    USE SIGNAL ;
    PORT
      LAYER M5 ;
        RECT  346.476 189.888 346.5 190.08 ;
    END
  END s1__ts[373]
  PIN s1__ts[374]
    DIRECTION OUTPUT ;
    USE SIGNAL ;
    PORT
      LAYER M5 ;
        RECT  346.716 189.888 346.74 190.08 ;
    END
  END s1__ts[374]
  PIN s1__ts[375]
    DIRECTION OUTPUT ;
    USE SIGNAL ;
    PORT
      LAYER M5 ;
        RECT  346.956 189.888 346.98 190.08 ;
    END
  END s1__ts[375]
  PIN s1__ts[376]
    DIRECTION OUTPUT ;
    USE SIGNAL ;
    PORT
      LAYER M5 ;
        RECT  347.148 189.888 347.172 190.08 ;
    END
  END s1__ts[376]
  PIN s1__ts[377]
    DIRECTION OUTPUT ;
    USE SIGNAL ;
    PORT
      LAYER M5 ;
        RECT  347.388 189.888 347.412 190.08 ;
    END
  END s1__ts[377]
  PIN s1__ts[378]
    DIRECTION OUTPUT ;
    USE SIGNAL ;
    PORT
      LAYER M5 ;
        RECT  347.628 189.888 347.652 190.08 ;
    END
  END s1__ts[378]
  PIN s1__ts[379]
    DIRECTION OUTPUT ;
    USE SIGNAL ;
    PORT
      LAYER M5 ;
        RECT  347.82 189.888 347.844 190.08 ;
    END
  END s1__ts[379]
  PIN s1__ts[37]
    DIRECTION OUTPUT ;
    USE SIGNAL ;
    PORT
      LAYER M5 ;
        RECT  270.06 189.888 270.084 190.08 ;
    END
  END s1__ts[37]
  PIN s1__ts[380]
    DIRECTION OUTPUT ;
    USE SIGNAL ;
    PORT
      LAYER M5 ;
        RECT  348.06 189.888 348.084 190.08 ;
    END
  END s1__ts[380]
  PIN s1__ts[381]
    DIRECTION OUTPUT ;
    USE SIGNAL ;
    PORT
      LAYER M5 ;
        RECT  348.3 189.888 348.324 190.08 ;
    END
  END s1__ts[381]
  PIN s1__ts[382]
    DIRECTION OUTPUT ;
    USE SIGNAL ;
    PORT
      LAYER M5 ;
        RECT  348.54 189.888 348.564 190.08 ;
    END
  END s1__ts[382]
  PIN s1__ts[383]
    DIRECTION OUTPUT ;
    USE SIGNAL ;
    PORT
      LAYER M5 ;
        RECT  348.732 189.888 348.756 190.08 ;
    END
  END s1__ts[383]
  PIN s1__ts[384]
    DIRECTION OUTPUT ;
    USE SIGNAL ;
    PORT
      LAYER M5 ;
        RECT  348.972 189.888 348.996 190.08 ;
    END
  END s1__ts[384]
  PIN s1__ts[385]
    DIRECTION OUTPUT ;
    USE SIGNAL ;
    PORT
      LAYER M5 ;
        RECT  349.212 189.888 349.236 190.08 ;
    END
  END s1__ts[385]
  PIN s1__ts[386]
    DIRECTION OUTPUT ;
    USE SIGNAL ;
    PORT
      LAYER M5 ;
        RECT  349.452 189.888 349.476 190.08 ;
    END
  END s1__ts[386]
  PIN s1__ts[387]
    DIRECTION OUTPUT ;
    USE SIGNAL ;
    PORT
      LAYER M5 ;
        RECT  349.644 189.888 349.668 190.08 ;
    END
  END s1__ts[387]
  PIN s1__ts[388]
    DIRECTION OUTPUT ;
    USE SIGNAL ;
    PORT
      LAYER M5 ;
        RECT  349.884 189.888 349.908 190.08 ;
    END
  END s1__ts[388]
  PIN s1__ts[389]
    DIRECTION OUTPUT ;
    USE SIGNAL ;
    PORT
      LAYER M5 ;
        RECT  350.124 189.888 350.148 190.08 ;
    END
  END s1__ts[389]
  PIN s1__ts[38]
    DIRECTION OUTPUT ;
    USE SIGNAL ;
    PORT
      LAYER M5 ;
        RECT  270.252 189.888 270.276 190.08 ;
    END
  END s1__ts[38]
  PIN s1__ts[390]
    DIRECTION OUTPUT ;
    USE SIGNAL ;
    PORT
      LAYER M5 ;
        RECT  350.364 189.888 350.388 190.08 ;
    END
  END s1__ts[390]
  PIN s1__ts[391]
    DIRECTION OUTPUT ;
    USE SIGNAL ;
    PORT
      LAYER M5 ;
        RECT  350.556 189.888 350.58 190.08 ;
    END
  END s1__ts[391]
  PIN s1__ts[392]
    DIRECTION OUTPUT ;
    USE SIGNAL ;
    PORT
      LAYER M5 ;
        RECT  350.796 189.888 350.82 190.08 ;
    END
  END s1__ts[392]
  PIN s1__ts[393]
    DIRECTION OUTPUT ;
    USE SIGNAL ;
    PORT
      LAYER M5 ;
        RECT  351.036 189.888 351.06 190.08 ;
    END
  END s1__ts[393]
  PIN s1__ts[394]
    DIRECTION OUTPUT ;
    USE SIGNAL ;
    PORT
      LAYER M5 ;
        RECT  351.276 189.888 351.3 190.08 ;
    END
  END s1__ts[394]
  PIN s1__ts[395]
    DIRECTION OUTPUT ;
    USE SIGNAL ;
    PORT
      LAYER M5 ;
        RECT  351.468 189.888 351.492 190.08 ;
    END
  END s1__ts[395]
  PIN s1__ts[396]
    DIRECTION OUTPUT ;
    USE SIGNAL ;
    PORT
      LAYER M5 ;
        RECT  351.708 189.888 351.732 190.08 ;
    END
  END s1__ts[396]
  PIN s1__ts[397]
    DIRECTION OUTPUT ;
    USE SIGNAL ;
    PORT
      LAYER M5 ;
        RECT  351.948 189.888 351.972 190.08 ;
    END
  END s1__ts[397]
  PIN s1__ts[398]
    DIRECTION OUTPUT ;
    USE SIGNAL ;
    PORT
      LAYER M5 ;
        RECT  352.188 189.888 352.212 190.08 ;
    END
  END s1__ts[398]
  PIN s1__ts[399]
    DIRECTION OUTPUT ;
    USE SIGNAL ;
    PORT
      LAYER M5 ;
        RECT  352.38 189.888 352.404 190.08 ;
    END
  END s1__ts[399]
  PIN s1__ts[39]
    DIRECTION OUTPUT ;
    USE SIGNAL ;
    PORT
      LAYER M5 ;
        RECT  270.492 189.888 270.516 190.08 ;
    END
  END s1__ts[39]
  PIN s1__ts[3]
    DIRECTION OUTPUT ;
    USE SIGNAL ;
    PORT
      LAYER M5 ;
        RECT  262.284 189.888 262.308 190.08 ;
    END
  END s1__ts[3]
  PIN s1__ts[400]
    DIRECTION OUTPUT ;
    USE SIGNAL ;
    PORT
      LAYER M5 ;
        RECT  352.62 189.888 352.644 190.08 ;
    END
  END s1__ts[400]
  PIN s1__ts[401]
    DIRECTION OUTPUT ;
    USE SIGNAL ;
    PORT
      LAYER M5 ;
        RECT  352.86 189.888 352.884 190.08 ;
    END
  END s1__ts[401]
  PIN s1__ts[402]
    DIRECTION OUTPUT ;
    USE SIGNAL ;
    PORT
      LAYER M5 ;
        RECT  353.1 189.888 353.124 190.08 ;
    END
  END s1__ts[402]
  PIN s1__ts[403]
    DIRECTION OUTPUT ;
    USE SIGNAL ;
    PORT
      LAYER M5 ;
        RECT  353.292 189.888 353.316 190.08 ;
    END
  END s1__ts[403]
  PIN s1__ts[404]
    DIRECTION OUTPUT ;
    USE SIGNAL ;
    PORT
      LAYER M5 ;
        RECT  353.532 189.888 353.556 190.08 ;
    END
  END s1__ts[404]
  PIN s1__ts[405]
    DIRECTION OUTPUT ;
    USE SIGNAL ;
    PORT
      LAYER M5 ;
        RECT  353.772 189.888 353.796 190.08 ;
    END
  END s1__ts[405]
  PIN s1__ts[406]
    DIRECTION OUTPUT ;
    USE SIGNAL ;
    PORT
      LAYER M5 ;
        RECT  353.964 189.888 353.988 190.08 ;
    END
  END s1__ts[406]
  PIN s1__ts[407]
    DIRECTION OUTPUT ;
    USE SIGNAL ;
    PORT
      LAYER M5 ;
        RECT  354.204 189.888 354.228 190.08 ;
    END
  END s1__ts[407]
  PIN s1__ts[408]
    DIRECTION OUTPUT ;
    USE SIGNAL ;
    PORT
      LAYER M5 ;
        RECT  354.444 189.888 354.468 190.08 ;
    END
  END s1__ts[408]
  PIN s1__ts[409]
    DIRECTION OUTPUT ;
    USE SIGNAL ;
    PORT
      LAYER M5 ;
        RECT  354.684 189.888 354.708 190.08 ;
    END
  END s1__ts[409]
  PIN s1__ts[40]
    DIRECTION OUTPUT ;
    USE SIGNAL ;
    PORT
      LAYER M5 ;
        RECT  270.732 189.888 270.756 190.08 ;
    END
  END s1__ts[40]
  PIN s1__ts[410]
    DIRECTION OUTPUT ;
    USE SIGNAL ;
    PORT
      LAYER M5 ;
        RECT  354.876 189.888 354.9 190.08 ;
    END
  END s1__ts[410]
  PIN s1__ts[411]
    DIRECTION OUTPUT ;
    USE SIGNAL ;
    PORT
      LAYER M5 ;
        RECT  355.116 189.888 355.14 190.08 ;
    END
  END s1__ts[411]
  PIN s1__ts[412]
    DIRECTION OUTPUT ;
    USE SIGNAL ;
    PORT
      LAYER M5 ;
        RECT  355.356 189.888 355.38 190.08 ;
    END
  END s1__ts[412]
  PIN s1__ts[413]
    DIRECTION OUTPUT ;
    USE SIGNAL ;
    PORT
      LAYER M5 ;
        RECT  355.596 189.888 355.62 190.08 ;
    END
  END s1__ts[413]
  PIN s1__ts[414]
    DIRECTION OUTPUT ;
    USE SIGNAL ;
    PORT
      LAYER M5 ;
        RECT  355.788 189.888 355.812 190.08 ;
    END
  END s1__ts[414]
  PIN s1__ts[415]
    DIRECTION OUTPUT ;
    USE SIGNAL ;
    PORT
      LAYER M5 ;
        RECT  356.028 189.888 356.052 190.08 ;
    END
  END s1__ts[415]
  PIN s1__ts[416]
    DIRECTION OUTPUT ;
    USE SIGNAL ;
    PORT
      LAYER M5 ;
        RECT  356.268 189.888 356.292 190.08 ;
    END
  END s1__ts[416]
  PIN s1__ts[417]
    DIRECTION OUTPUT ;
    USE SIGNAL ;
    PORT
      LAYER M5 ;
        RECT  356.508 189.888 356.532 190.08 ;
    END
  END s1__ts[417]
  PIN s1__ts[418]
    DIRECTION OUTPUT ;
    USE SIGNAL ;
    PORT
      LAYER M5 ;
        RECT  356.7 189.888 356.724 190.08 ;
    END
  END s1__ts[418]
  PIN s1__ts[419]
    DIRECTION OUTPUT ;
    USE SIGNAL ;
    PORT
      LAYER M5 ;
        RECT  356.94 189.888 356.964 190.08 ;
    END
  END s1__ts[419]
  PIN s1__ts[41]
    DIRECTION OUTPUT ;
    USE SIGNAL ;
    PORT
      LAYER M5 ;
        RECT  270.924 189.888 270.948 190.08 ;
    END
  END s1__ts[41]
  PIN s1__ts[420]
    DIRECTION OUTPUT ;
    USE SIGNAL ;
    PORT
      LAYER M5 ;
        RECT  357.18 189.888 357.204 190.08 ;
    END
  END s1__ts[420]
  PIN s1__ts[421]
    DIRECTION OUTPUT ;
    USE SIGNAL ;
    PORT
      LAYER M5 ;
        RECT  357.42 189.888 357.444 190.08 ;
    END
  END s1__ts[421]
  PIN s1__ts[422]
    DIRECTION OUTPUT ;
    USE SIGNAL ;
    PORT
      LAYER M5 ;
        RECT  357.612 189.888 357.636 190.08 ;
    END
  END s1__ts[422]
  PIN s1__ts[423]
    DIRECTION OUTPUT ;
    USE SIGNAL ;
    PORT
      LAYER M5 ;
        RECT  357.852 189.888 357.876 190.08 ;
    END
  END s1__ts[423]
  PIN s1__ts[424]
    DIRECTION OUTPUT ;
    USE SIGNAL ;
    PORT
      LAYER M5 ;
        RECT  358.092 189.888 358.116 190.08 ;
    END
  END s1__ts[424]
  PIN s1__ts[425]
    DIRECTION OUTPUT ;
    USE SIGNAL ;
    PORT
      LAYER M5 ;
        RECT  358.332 189.888 358.356 190.08 ;
    END
  END s1__ts[425]
  PIN s1__ts[426]
    DIRECTION OUTPUT ;
    USE SIGNAL ;
    PORT
      LAYER M5 ;
        RECT  358.524 189.888 358.548 190.08 ;
    END
  END s1__ts[426]
  PIN s1__ts[427]
    DIRECTION OUTPUT ;
    USE SIGNAL ;
    PORT
      LAYER M5 ;
        RECT  358.764 189.888 358.788 190.08 ;
    END
  END s1__ts[427]
  PIN s1__ts[428]
    DIRECTION OUTPUT ;
    USE SIGNAL ;
    PORT
      LAYER M5 ;
        RECT  359.004 189.888 359.028 190.08 ;
    END
  END s1__ts[428]
  PIN s1__ts[429]
    DIRECTION OUTPUT ;
    USE SIGNAL ;
    PORT
      LAYER M5 ;
        RECT  359.196 189.888 359.22 190.08 ;
    END
  END s1__ts[429]
  PIN s1__ts[42]
    DIRECTION OUTPUT ;
    USE SIGNAL ;
    PORT
      LAYER M5 ;
        RECT  271.164 189.888 271.188 190.08 ;
    END
  END s1__ts[42]
  PIN s1__ts[430]
    DIRECTION OUTPUT ;
    USE SIGNAL ;
    PORT
      LAYER M5 ;
        RECT  359.436 189.888 359.46 190.08 ;
    END
  END s1__ts[430]
  PIN s1__ts[431]
    DIRECTION OUTPUT ;
    USE SIGNAL ;
    PORT
      LAYER M5 ;
        RECT  359.676 189.888 359.7 190.08 ;
    END
  END s1__ts[431]
  PIN s1__ts[432]
    DIRECTION OUTPUT ;
    USE SIGNAL ;
    PORT
      LAYER M5 ;
        RECT  359.916 189.888 359.94 190.08 ;
    END
  END s1__ts[432]
  PIN s1__ts[433]
    DIRECTION OUTPUT ;
    USE SIGNAL ;
    PORT
      LAYER M5 ;
        RECT  360.108 189.888 360.132 190.08 ;
    END
  END s1__ts[433]
  PIN s1__ts[434]
    DIRECTION OUTPUT ;
    USE SIGNAL ;
    PORT
      LAYER M5 ;
        RECT  360.348 189.888 360.372 190.08 ;
    END
  END s1__ts[434]
  PIN s1__ts[435]
    DIRECTION OUTPUT ;
    USE SIGNAL ;
    PORT
      LAYER M5 ;
        RECT  360.588 189.888 360.612 190.08 ;
    END
  END s1__ts[435]
  PIN s1__ts[436]
    DIRECTION OUTPUT ;
    USE SIGNAL ;
    PORT
      LAYER M5 ;
        RECT  360.828 189.888 360.852 190.08 ;
    END
  END s1__ts[436]
  PIN s1__ts[437]
    DIRECTION OUTPUT ;
    USE SIGNAL ;
    PORT
      LAYER M5 ;
        RECT  361.02 189.888 361.044 190.08 ;
    END
  END s1__ts[437]
  PIN s1__ts[438]
    DIRECTION OUTPUT ;
    USE SIGNAL ;
    PORT
      LAYER M5 ;
        RECT  361.26 189.888 361.284 190.08 ;
    END
  END s1__ts[438]
  PIN s1__ts[439]
    DIRECTION OUTPUT ;
    USE SIGNAL ;
    PORT
      LAYER M5 ;
        RECT  361.5 189.888 361.524 190.08 ;
    END
  END s1__ts[439]
  PIN s1__ts[43]
    DIRECTION OUTPUT ;
    USE SIGNAL ;
    PORT
      LAYER M5 ;
        RECT  271.404 189.888 271.428 190.08 ;
    END
  END s1__ts[43]
  PIN s1__ts[440]
    DIRECTION OUTPUT ;
    USE SIGNAL ;
    PORT
      LAYER M5 ;
        RECT  361.74 189.888 361.764 190.08 ;
    END
  END s1__ts[440]
  PIN s1__ts[441]
    DIRECTION OUTPUT ;
    USE SIGNAL ;
    PORT
      LAYER M5 ;
        RECT  361.932 189.888 361.956 190.08 ;
    END
  END s1__ts[441]
  PIN s1__ts[442]
    DIRECTION OUTPUT ;
    USE SIGNAL ;
    PORT
      LAYER M5 ;
        RECT  362.172 189.888 362.196 190.08 ;
    END
  END s1__ts[442]
  PIN s1__ts[443]
    DIRECTION OUTPUT ;
    USE SIGNAL ;
    PORT
      LAYER M5 ;
        RECT  362.412 189.888 362.436 190.08 ;
    END
  END s1__ts[443]
  PIN s1__ts[444]
    DIRECTION OUTPUT ;
    USE SIGNAL ;
    PORT
      LAYER M5 ;
        RECT  362.652 189.888 362.676 190.08 ;
    END
  END s1__ts[444]
  PIN s1__ts[445]
    DIRECTION OUTPUT ;
    USE SIGNAL ;
    PORT
      LAYER M5 ;
        RECT  362.844 189.888 362.868 190.08 ;
    END
  END s1__ts[445]
  PIN s1__ts[446]
    DIRECTION OUTPUT ;
    USE SIGNAL ;
    PORT
      LAYER M5 ;
        RECT  363.084 189.888 363.108 190.08 ;
    END
  END s1__ts[446]
  PIN s1__ts[447]
    DIRECTION OUTPUT ;
    USE SIGNAL ;
    PORT
      LAYER M5 ;
        RECT  363.324 189.888 363.348 190.08 ;
    END
  END s1__ts[447]
  PIN s1__ts[448]
    DIRECTION OUTPUT ;
    USE SIGNAL ;
    PORT
      LAYER M5 ;
        RECT  363.564 189.888 363.588 190.08 ;
    END
  END s1__ts[448]
  PIN s1__ts[449]
    DIRECTION OUTPUT ;
    USE SIGNAL ;
    PORT
      LAYER M5 ;
        RECT  363.756 189.888 363.78 190.08 ;
    END
  END s1__ts[449]
  PIN s1__ts[44]
    DIRECTION OUTPUT ;
    USE SIGNAL ;
    PORT
      LAYER M5 ;
        RECT  271.644 189.888 271.668 190.08 ;
    END
  END s1__ts[44]
  PIN s1__ts[450]
    DIRECTION OUTPUT ;
    USE SIGNAL ;
    PORT
      LAYER M5 ;
        RECT  363.996 189.888 364.02 190.08 ;
    END
  END s1__ts[450]
  PIN s1__ts[451]
    DIRECTION OUTPUT ;
    USE SIGNAL ;
    PORT
      LAYER M5 ;
        RECT  364.236 189.888 364.26 190.08 ;
    END
  END s1__ts[451]
  PIN s1__ts[452]
    DIRECTION OUTPUT ;
    USE SIGNAL ;
    PORT
      LAYER M5 ;
        RECT  364.428 189.888 364.452 190.08 ;
    END
  END s1__ts[452]
  PIN s1__ts[453]
    DIRECTION OUTPUT ;
    USE SIGNAL ;
    PORT
      LAYER M5 ;
        RECT  364.668 189.888 364.692 190.08 ;
    END
  END s1__ts[453]
  PIN s1__ts[454]
    DIRECTION OUTPUT ;
    USE SIGNAL ;
    PORT
      LAYER M5 ;
        RECT  364.908 189.888 364.932 190.08 ;
    END
  END s1__ts[454]
  PIN s1__ts[455]
    DIRECTION OUTPUT ;
    USE SIGNAL ;
    PORT
      LAYER M5 ;
        RECT  365.148 189.888 365.172 190.08 ;
    END
  END s1__ts[455]
  PIN s1__ts[456]
    DIRECTION OUTPUT ;
    USE SIGNAL ;
    PORT
      LAYER M5 ;
        RECT  365.34 189.888 365.364 190.08 ;
    END
  END s1__ts[456]
  PIN s1__ts[457]
    DIRECTION OUTPUT ;
    USE SIGNAL ;
    PORT
      LAYER M5 ;
        RECT  365.58 189.888 365.604 190.08 ;
    END
  END s1__ts[457]
  PIN s1__ts[458]
    DIRECTION OUTPUT ;
    USE SIGNAL ;
    PORT
      LAYER M5 ;
        RECT  365.82 189.888 365.844 190.08 ;
    END
  END s1__ts[458]
  PIN s1__ts[459]
    DIRECTION OUTPUT ;
    USE SIGNAL ;
    PORT
      LAYER M5 ;
        RECT  366.06 189.888 366.084 190.08 ;
    END
  END s1__ts[459]
  PIN s1__ts[45]
    DIRECTION OUTPUT ;
    USE SIGNAL ;
    PORT
      LAYER M5 ;
        RECT  271.836 189.888 271.86 190.08 ;
    END
  END s1__ts[45]
  PIN s1__ts[460]
    DIRECTION OUTPUT ;
    USE SIGNAL ;
    PORT
      LAYER M5 ;
        RECT  366.252 189.888 366.276 190.08 ;
    END
  END s1__ts[460]
  PIN s1__ts[461]
    DIRECTION OUTPUT ;
    USE SIGNAL ;
    PORT
      LAYER M5 ;
        RECT  366.492 189.888 366.516 190.08 ;
    END
  END s1__ts[461]
  PIN s1__ts[462]
    DIRECTION OUTPUT ;
    USE SIGNAL ;
    PORT
      LAYER M5 ;
        RECT  366.732 189.888 366.756 190.08 ;
    END
  END s1__ts[462]
  PIN s1__ts[463]
    DIRECTION OUTPUT ;
    USE SIGNAL ;
    PORT
      LAYER M5 ;
        RECT  366.972 189.888 366.996 190.08 ;
    END
  END s1__ts[463]
  PIN s1__ts[464]
    DIRECTION OUTPUT ;
    USE SIGNAL ;
    PORT
      LAYER M5 ;
        RECT  367.164 189.888 367.188 190.08 ;
    END
  END s1__ts[464]
  PIN s1__ts[465]
    DIRECTION OUTPUT ;
    USE SIGNAL ;
    PORT
      LAYER M5 ;
        RECT  367.404 189.888 367.428 190.08 ;
    END
  END s1__ts[465]
  PIN s1__ts[466]
    DIRECTION OUTPUT ;
    USE SIGNAL ;
    PORT
      LAYER M5 ;
        RECT  367.644 189.888 367.668 190.08 ;
    END
  END s1__ts[466]
  PIN s1__ts[467]
    DIRECTION OUTPUT ;
    USE SIGNAL ;
    PORT
      LAYER M5 ;
        RECT  367.884 189.888 367.908 190.08 ;
    END
  END s1__ts[467]
  PIN s1__ts[468]
    DIRECTION OUTPUT ;
    USE SIGNAL ;
    PORT
      LAYER M5 ;
        RECT  368.076 189.888 368.1 190.08 ;
    END
  END s1__ts[468]
  PIN s1__ts[469]
    DIRECTION OUTPUT ;
    USE SIGNAL ;
    PORT
      LAYER M5 ;
        RECT  368.316 189.888 368.34 190.08 ;
    END
  END s1__ts[469]
  PIN s1__ts[46]
    DIRECTION OUTPUT ;
    USE SIGNAL ;
    PORT
      LAYER M5 ;
        RECT  272.076 189.888 272.1 190.08 ;
    END
  END s1__ts[46]
  PIN s1__ts[470]
    DIRECTION OUTPUT ;
    USE SIGNAL ;
    PORT
      LAYER M5 ;
        RECT  368.556 189.888 368.58 190.08 ;
    END
  END s1__ts[470]
  PIN s1__ts[471]
    DIRECTION OUTPUT ;
    USE SIGNAL ;
    PORT
      LAYER M5 ;
        RECT  368.796 189.888 368.82 190.08 ;
    END
  END s1__ts[471]
  PIN s1__ts[472]
    DIRECTION OUTPUT ;
    USE SIGNAL ;
    PORT
      LAYER M5 ;
        RECT  368.988 189.888 369.012 190.08 ;
    END
  END s1__ts[472]
  PIN s1__ts[473]
    DIRECTION OUTPUT ;
    USE SIGNAL ;
    PORT
      LAYER M5 ;
        RECT  369.228 189.888 369.252 190.08 ;
    END
  END s1__ts[473]
  PIN s1__ts[474]
    DIRECTION OUTPUT ;
    USE SIGNAL ;
    PORT
      LAYER M5 ;
        RECT  369.468 189.888 369.492 190.08 ;
    END
  END s1__ts[474]
  PIN s1__ts[475]
    DIRECTION OUTPUT ;
    USE SIGNAL ;
    PORT
      LAYER M5 ;
        RECT  369.708 189.888 369.732 190.08 ;
    END
  END s1__ts[475]
  PIN s1__ts[476]
    DIRECTION OUTPUT ;
    USE SIGNAL ;
    PORT
      LAYER M5 ;
        RECT  369.9 189.888 369.924 190.08 ;
    END
  END s1__ts[476]
  PIN s1__ts[477]
    DIRECTION OUTPUT ;
    USE SIGNAL ;
    PORT
      LAYER M5 ;
        RECT  370.14 189.888 370.164 190.08 ;
    END
  END s1__ts[477]
  PIN s1__ts[478]
    DIRECTION OUTPUT ;
    USE SIGNAL ;
    PORT
      LAYER M5 ;
        RECT  370.38 189.888 370.404 190.08 ;
    END
  END s1__ts[478]
  PIN s1__ts[479]
    DIRECTION OUTPUT ;
    USE SIGNAL ;
    PORT
      LAYER M5 ;
        RECT  370.572 189.888 370.596 190.08 ;
    END
  END s1__ts[479]
  PIN s1__ts[47]
    DIRECTION OUTPUT ;
    USE SIGNAL ;
    PORT
      LAYER M5 ;
        RECT  272.316 189.888 272.34 190.08 ;
    END
  END s1__ts[47]
  PIN s1__ts[480]
    DIRECTION OUTPUT ;
    USE SIGNAL ;
    PORT
      LAYER M5 ;
        RECT  370.812 189.888 370.836 190.08 ;
    END
  END s1__ts[480]
  PIN s1__ts[481]
    DIRECTION OUTPUT ;
    USE SIGNAL ;
    PORT
      LAYER M5 ;
        RECT  371.052 189.888 371.076 190.08 ;
    END
  END s1__ts[481]
  PIN s1__ts[482]
    DIRECTION OUTPUT ;
    USE SIGNAL ;
    PORT
      LAYER M5 ;
        RECT  371.292 189.888 371.316 190.08 ;
    END
  END s1__ts[482]
  PIN s1__ts[483]
    DIRECTION OUTPUT ;
    USE SIGNAL ;
    PORT
      LAYER M5 ;
        RECT  371.484 189.888 371.508 190.08 ;
    END
  END s1__ts[483]
  PIN s1__ts[484]
    DIRECTION OUTPUT ;
    USE SIGNAL ;
    PORT
      LAYER M5 ;
        RECT  371.724 189.888 371.748 190.08 ;
    END
  END s1__ts[484]
  PIN s1__ts[485]
    DIRECTION OUTPUT ;
    USE SIGNAL ;
    PORT
      LAYER M5 ;
        RECT  371.964 189.888 371.988 190.08 ;
    END
  END s1__ts[485]
  PIN s1__ts[486]
    DIRECTION OUTPUT ;
    USE SIGNAL ;
    PORT
      LAYER M5 ;
        RECT  372.204 189.888 372.228 190.08 ;
    END
  END s1__ts[486]
  PIN s1__ts[487]
    DIRECTION OUTPUT ;
    USE SIGNAL ;
    PORT
      LAYER M5 ;
        RECT  372.396 189.888 372.42 190.08 ;
    END
  END s1__ts[487]
  PIN s1__ts[488]
    DIRECTION OUTPUT ;
    USE SIGNAL ;
    PORT
      LAYER M5 ;
        RECT  372.636 189.888 372.66 190.08 ;
    END
  END s1__ts[488]
  PIN s1__ts[489]
    DIRECTION OUTPUT ;
    USE SIGNAL ;
    PORT
      LAYER M5 ;
        RECT  372.876 189.888 372.9 190.08 ;
    END
  END s1__ts[489]
  PIN s1__ts[48]
    DIRECTION OUTPUT ;
    USE SIGNAL ;
    PORT
      LAYER M5 ;
        RECT  272.556 189.888 272.58 190.08 ;
    END
  END s1__ts[48]
  PIN s1__ts[490]
    DIRECTION OUTPUT ;
    USE SIGNAL ;
    PORT
      LAYER M5 ;
        RECT  373.116 189.888 373.14 190.08 ;
    END
  END s1__ts[490]
  PIN s1__ts[491]
    DIRECTION OUTPUT ;
    USE SIGNAL ;
    PORT
      LAYER M5 ;
        RECT  373.308 189.888 373.332 190.08 ;
    END
  END s1__ts[491]
  PIN s1__ts[492]
    DIRECTION OUTPUT ;
    USE SIGNAL ;
    PORT
      LAYER M5 ;
        RECT  373.548 189.888 373.572 190.08 ;
    END
  END s1__ts[492]
  PIN s1__ts[493]
    DIRECTION OUTPUT ;
    USE SIGNAL ;
    PORT
      LAYER M5 ;
        RECT  373.788 189.888 373.812 190.08 ;
    END
  END s1__ts[493]
  PIN s1__ts[494]
    DIRECTION OUTPUT ;
    USE SIGNAL ;
    PORT
      LAYER M5 ;
        RECT  374.028 189.888 374.052 190.08 ;
    END
  END s1__ts[494]
  PIN s1__ts[495]
    DIRECTION OUTPUT ;
    USE SIGNAL ;
    PORT
      LAYER M5 ;
        RECT  374.22 189.888 374.244 190.08 ;
    END
  END s1__ts[495]
  PIN s1__ts[496]
    DIRECTION OUTPUT ;
    USE SIGNAL ;
    PORT
      LAYER M5 ;
        RECT  374.46 189.888 374.484 190.08 ;
    END
  END s1__ts[496]
  PIN s1__ts[497]
    DIRECTION OUTPUT ;
    USE SIGNAL ;
    PORT
      LAYER M5 ;
        RECT  374.7 189.888 374.724 190.08 ;
    END
  END s1__ts[497]
  PIN s1__ts[498]
    DIRECTION OUTPUT ;
    USE SIGNAL ;
    PORT
      LAYER M5 ;
        RECT  374.94 189.888 374.964 190.08 ;
    END
  END s1__ts[498]
  PIN s1__ts[499]
    DIRECTION OUTPUT ;
    USE SIGNAL ;
    PORT
      LAYER M5 ;
        RECT  375.132 189.888 375.156 190.08 ;
    END
  END s1__ts[499]
  PIN s1__ts[49]
    DIRECTION OUTPUT ;
    USE SIGNAL ;
    PORT
      LAYER M5 ;
        RECT  272.748 189.888 272.772 190.08 ;
    END
  END s1__ts[49]
  PIN s1__ts[4]
    DIRECTION OUTPUT ;
    USE SIGNAL ;
    PORT
      LAYER M5 ;
        RECT  262.524 189.888 262.548 190.08 ;
    END
  END s1__ts[4]
  PIN s1__ts[500]
    DIRECTION OUTPUT ;
    USE SIGNAL ;
    PORT
      LAYER M5 ;
        RECT  375.372 189.888 375.396 190.08 ;
    END
  END s1__ts[500]
  PIN s1__ts[501]
    DIRECTION OUTPUT ;
    USE SIGNAL ;
    PORT
      LAYER M5 ;
        RECT  375.612 189.888 375.636 190.08 ;
    END
  END s1__ts[501]
  PIN s1__ts[502]
    DIRECTION OUTPUT ;
    USE SIGNAL ;
    PORT
      LAYER M5 ;
        RECT  375.804 189.888 375.828 190.08 ;
    END
  END s1__ts[502]
  PIN s1__ts[503]
    DIRECTION OUTPUT ;
    USE SIGNAL ;
    PORT
      LAYER M5 ;
        RECT  376.044 189.888 376.068 190.08 ;
    END
  END s1__ts[503]
  PIN s1__ts[504]
    DIRECTION OUTPUT ;
    USE SIGNAL ;
    PORT
      LAYER M5 ;
        RECT  376.284 189.888 376.308 190.08 ;
    END
  END s1__ts[504]
  PIN s1__ts[505]
    DIRECTION OUTPUT ;
    USE SIGNAL ;
    PORT
      LAYER M5 ;
        RECT  376.524 189.888 376.548 190.08 ;
    END
  END s1__ts[505]
  PIN s1__ts[506]
    DIRECTION OUTPUT ;
    USE SIGNAL ;
    PORT
      LAYER M5 ;
        RECT  376.716 189.888 376.74 190.08 ;
    END
  END s1__ts[506]
  PIN s1__ts[507]
    DIRECTION OUTPUT ;
    USE SIGNAL ;
    PORT
      LAYER M5 ;
        RECT  376.956 189.888 376.98 190.08 ;
    END
  END s1__ts[507]
  PIN s1__ts[508]
    DIRECTION OUTPUT ;
    USE SIGNAL ;
    PORT
      LAYER M5 ;
        RECT  377.196 189.888 377.22 190.08 ;
    END
  END s1__ts[508]
  PIN s1__ts[509]
    DIRECTION OUTPUT ;
    USE SIGNAL ;
    PORT
      LAYER M5 ;
        RECT  377.436 189.888 377.46 190.08 ;
    END
  END s1__ts[509]
  PIN s1__ts[50]
    DIRECTION OUTPUT ;
    USE SIGNAL ;
    PORT
      LAYER M5 ;
        RECT  272.988 189.888 273.012 190.08 ;
    END
  END s1__ts[50]
  PIN s1__ts[510]
    DIRECTION OUTPUT ;
    USE SIGNAL ;
    PORT
      LAYER M5 ;
        RECT  377.628 189.888 377.652 190.08 ;
    END
  END s1__ts[510]
  PIN s1__ts[511]
    DIRECTION OUTPUT ;
    USE SIGNAL ;
    PORT
      LAYER M5 ;
        RECT  377.868 189.888 377.892 190.08 ;
    END
  END s1__ts[511]
  PIN s1__ts[51]
    DIRECTION OUTPUT ;
    USE SIGNAL ;
    PORT
      LAYER M5 ;
        RECT  273.228 189.888 273.252 190.08 ;
    END
  END s1__ts[51]
  PIN s1__ts[52]
    DIRECTION OUTPUT ;
    USE SIGNAL ;
    PORT
      LAYER M5 ;
        RECT  273.468 189.888 273.492 190.08 ;
    END
  END s1__ts[52]
  PIN s1__ts[53]
    DIRECTION OUTPUT ;
    USE SIGNAL ;
    PORT
      LAYER M5 ;
        RECT  273.66 189.888 273.684 190.08 ;
    END
  END s1__ts[53]
  PIN s1__ts[54]
    DIRECTION OUTPUT ;
    USE SIGNAL ;
    PORT
      LAYER M5 ;
        RECT  273.9 189.888 273.924 190.08 ;
    END
  END s1__ts[54]
  PIN s1__ts[55]
    DIRECTION OUTPUT ;
    USE SIGNAL ;
    PORT
      LAYER M5 ;
        RECT  274.14 189.888 274.164 190.08 ;
    END
  END s1__ts[55]
  PIN s1__ts[56]
    DIRECTION OUTPUT ;
    USE SIGNAL ;
    PORT
      LAYER M5 ;
        RECT  274.38 189.888 274.404 190.08 ;
    END
  END s1__ts[56]
  PIN s1__ts[57]
    DIRECTION OUTPUT ;
    USE SIGNAL ;
    PORT
      LAYER M5 ;
        RECT  274.572 189.888 274.596 190.08 ;
    END
  END s1__ts[57]
  PIN s1__ts[58]
    DIRECTION OUTPUT ;
    USE SIGNAL ;
    PORT
      LAYER M5 ;
        RECT  274.812 189.888 274.836 190.08 ;
    END
  END s1__ts[58]
  PIN s1__ts[59]
    DIRECTION OUTPUT ;
    USE SIGNAL ;
    PORT
      LAYER M5 ;
        RECT  275.052 189.888 275.076 190.08 ;
    END
  END s1__ts[59]
  PIN s1__ts[5]
    DIRECTION OUTPUT ;
    USE SIGNAL ;
    PORT
      LAYER M5 ;
        RECT  262.764 189.888 262.788 190.08 ;
    END
  END s1__ts[5]
  PIN s1__ts[60]
    DIRECTION OUTPUT ;
    USE SIGNAL ;
    PORT
      LAYER M5 ;
        RECT  275.292 189.888 275.316 190.08 ;
    END
  END s1__ts[60]
  PIN s1__ts[61]
    DIRECTION OUTPUT ;
    USE SIGNAL ;
    PORT
      LAYER M5 ;
        RECT  275.484 189.888 275.508 190.08 ;
    END
  END s1__ts[61]
  PIN s1__ts[62]
    DIRECTION OUTPUT ;
    USE SIGNAL ;
    PORT
      LAYER M5 ;
        RECT  275.724 189.888 275.748 190.08 ;
    END
  END s1__ts[62]
  PIN s1__ts[63]
    DIRECTION OUTPUT ;
    USE SIGNAL ;
    PORT
      LAYER M5 ;
        RECT  275.964 189.888 275.988 190.08 ;
    END
  END s1__ts[63]
  PIN s1__ts[64]
    DIRECTION OUTPUT ;
    USE SIGNAL ;
    PORT
      LAYER M5 ;
        RECT  276.156 189.888 276.18 190.08 ;
    END
  END s1__ts[64]
  PIN s1__ts[65]
    DIRECTION OUTPUT ;
    USE SIGNAL ;
    PORT
      LAYER M5 ;
        RECT  276.396 189.888 276.42 190.08 ;
    END
  END s1__ts[65]
  PIN s1__ts[66]
    DIRECTION OUTPUT ;
    USE SIGNAL ;
    PORT
      LAYER M5 ;
        RECT  276.636 189.888 276.66 190.08 ;
    END
  END s1__ts[66]
  PIN s1__ts[67]
    DIRECTION OUTPUT ;
    USE SIGNAL ;
    PORT
      LAYER M5 ;
        RECT  276.876 189.888 276.9 190.08 ;
    END
  END s1__ts[67]
  PIN s1__ts[68]
    DIRECTION OUTPUT ;
    USE SIGNAL ;
    PORT
      LAYER M5 ;
        RECT  277.068 189.888 277.092 190.08 ;
    END
  END s1__ts[68]
  PIN s1__ts[69]
    DIRECTION OUTPUT ;
    USE SIGNAL ;
    PORT
      LAYER M5 ;
        RECT  277.308 189.888 277.332 190.08 ;
    END
  END s1__ts[69]
  PIN s1__ts[6]
    DIRECTION OUTPUT ;
    USE SIGNAL ;
    PORT
      LAYER M5 ;
        RECT  263.004 189.888 263.028 190.08 ;
    END
  END s1__ts[6]
  PIN s1__ts[70]
    DIRECTION OUTPUT ;
    USE SIGNAL ;
    PORT
      LAYER M5 ;
        RECT  277.548 189.888 277.572 190.08 ;
    END
  END s1__ts[70]
  PIN s1__ts[71]
    DIRECTION OUTPUT ;
    USE SIGNAL ;
    PORT
      LAYER M5 ;
        RECT  277.788 189.888 277.812 190.08 ;
    END
  END s1__ts[71]
  PIN s1__ts[72]
    DIRECTION OUTPUT ;
    USE SIGNAL ;
    PORT
      LAYER M5 ;
        RECT  277.98 189.888 278.004 190.08 ;
    END
  END s1__ts[72]
  PIN s1__ts[73]
    DIRECTION OUTPUT ;
    USE SIGNAL ;
    PORT
      LAYER M5 ;
        RECT  278.22 189.888 278.244 190.08 ;
    END
  END s1__ts[73]
  PIN s1__ts[74]
    DIRECTION OUTPUT ;
    USE SIGNAL ;
    PORT
      LAYER M5 ;
        RECT  278.46 189.888 278.484 190.08 ;
    END
  END s1__ts[74]
  PIN s1__ts[75]
    DIRECTION OUTPUT ;
    USE SIGNAL ;
    PORT
      LAYER M5 ;
        RECT  278.7 189.888 278.724 190.08 ;
    END
  END s1__ts[75]
  PIN s1__ts[76]
    DIRECTION OUTPUT ;
    USE SIGNAL ;
    PORT
      LAYER M5 ;
        RECT  278.892 189.888 278.916 190.08 ;
    END
  END s1__ts[76]
  PIN s1__ts[77]
    DIRECTION OUTPUT ;
    USE SIGNAL ;
    PORT
      LAYER M5 ;
        RECT  279.132 189.888 279.156 190.08 ;
    END
  END s1__ts[77]
  PIN s1__ts[78]
    DIRECTION OUTPUT ;
    USE SIGNAL ;
    PORT
      LAYER M5 ;
        RECT  279.372 189.888 279.396 190.08 ;
    END
  END s1__ts[78]
  PIN s1__ts[79]
    DIRECTION OUTPUT ;
    USE SIGNAL ;
    PORT
      LAYER M5 ;
        RECT  279.612 189.888 279.636 190.08 ;
    END
  END s1__ts[79]
  PIN s1__ts[7]
    DIRECTION OUTPUT ;
    USE SIGNAL ;
    PORT
      LAYER M5 ;
        RECT  263.196 189.888 263.22 190.08 ;
    END
  END s1__ts[7]
  PIN s1__ts[80]
    DIRECTION OUTPUT ;
    USE SIGNAL ;
    PORT
      LAYER M5 ;
        RECT  279.804 189.888 279.828 190.08 ;
    END
  END s1__ts[80]
  PIN s1__ts[81]
    DIRECTION OUTPUT ;
    USE SIGNAL ;
    PORT
      LAYER M5 ;
        RECT  280.044 189.888 280.068 190.08 ;
    END
  END s1__ts[81]
  PIN s1__ts[82]
    DIRECTION OUTPUT ;
    USE SIGNAL ;
    PORT
      LAYER M5 ;
        RECT  280.284 189.888 280.308 190.08 ;
    END
  END s1__ts[82]
  PIN s1__ts[83]
    DIRECTION OUTPUT ;
    USE SIGNAL ;
    PORT
      LAYER M5 ;
        RECT  280.524 189.888 280.548 190.08 ;
    END
  END s1__ts[83]
  PIN s1__ts[84]
    DIRECTION OUTPUT ;
    USE SIGNAL ;
    PORT
      LAYER M5 ;
        RECT  280.716 189.888 280.74 190.08 ;
    END
  END s1__ts[84]
  PIN s1__ts[85]
    DIRECTION OUTPUT ;
    USE SIGNAL ;
    PORT
      LAYER M5 ;
        RECT  280.956 189.888 280.98 190.08 ;
    END
  END s1__ts[85]
  PIN s1__ts[86]
    DIRECTION OUTPUT ;
    USE SIGNAL ;
    PORT
      LAYER M5 ;
        RECT  281.196 189.888 281.22 190.08 ;
    END
  END s1__ts[86]
  PIN s1__ts[87]
    DIRECTION OUTPUT ;
    USE SIGNAL ;
    PORT
      LAYER M5 ;
        RECT  281.388 189.888 281.412 190.08 ;
    END
  END s1__ts[87]
  PIN s1__ts[88]
    DIRECTION OUTPUT ;
    USE SIGNAL ;
    PORT
      LAYER M5 ;
        RECT  281.628 189.888 281.652 190.08 ;
    END
  END s1__ts[88]
  PIN s1__ts[89]
    DIRECTION OUTPUT ;
    USE SIGNAL ;
    PORT
      LAYER M5 ;
        RECT  281.868 189.888 281.892 190.08 ;
    END
  END s1__ts[89]
  PIN s1__ts[8]
    DIRECTION OUTPUT ;
    USE SIGNAL ;
    PORT
      LAYER M5 ;
        RECT  263.436 189.888 263.46 190.08 ;
    END
  END s1__ts[8]
  PIN s1__ts[90]
    DIRECTION OUTPUT ;
    USE SIGNAL ;
    PORT
      LAYER M5 ;
        RECT  282.108 189.888 282.132 190.08 ;
    END
  END s1__ts[90]
  PIN s1__ts[91]
    DIRECTION OUTPUT ;
    USE SIGNAL ;
    PORT
      LAYER M5 ;
        RECT  282.3 189.888 282.324 190.08 ;
    END
  END s1__ts[91]
  PIN s1__ts[92]
    DIRECTION OUTPUT ;
    USE SIGNAL ;
    PORT
      LAYER M5 ;
        RECT  282.54 189.888 282.564 190.08 ;
    END
  END s1__ts[92]
  PIN s1__ts[93]
    DIRECTION OUTPUT ;
    USE SIGNAL ;
    PORT
      LAYER M5 ;
        RECT  282.78 189.888 282.804 190.08 ;
    END
  END s1__ts[93]
  PIN s1__ts[94]
    DIRECTION OUTPUT ;
    USE SIGNAL ;
    PORT
      LAYER M5 ;
        RECT  283.02 189.888 283.044 190.08 ;
    END
  END s1__ts[94]
  PIN s1__ts[95]
    DIRECTION OUTPUT ;
    USE SIGNAL ;
    PORT
      LAYER M5 ;
        RECT  283.212 189.888 283.236 190.08 ;
    END
  END s1__ts[95]
  PIN s1__ts[96]
    DIRECTION OUTPUT ;
    USE SIGNAL ;
    PORT
      LAYER M5 ;
        RECT  283.452 189.888 283.476 190.08 ;
    END
  END s1__ts[96]
  PIN s1__ts[97]
    DIRECTION OUTPUT ;
    USE SIGNAL ;
    PORT
      LAYER M5 ;
        RECT  283.692 189.888 283.716 190.08 ;
    END
  END s1__ts[97]
  PIN s1__ts[98]
    DIRECTION OUTPUT ;
    USE SIGNAL ;
    PORT
      LAYER M5 ;
        RECT  283.932 189.888 283.956 190.08 ;
    END
  END s1__ts[98]
  PIN s1__ts[99]
    DIRECTION OUTPUT ;
    USE SIGNAL ;
    PORT
      LAYER M5 ;
        RECT  284.124 189.888 284.148 190.08 ;
    END
  END s1__ts[99]
  PIN s1__ts[9]
    DIRECTION OUTPUT ;
    USE SIGNAL ;
    PORT
      LAYER M5 ;
        RECT  263.676 189.888 263.7 190.08 ;
    END
  END s1__ts[9]
  PIN VDD
    DIRECTION INOUT ;
    USE POWER ;
    PORT
      LAYER M5 ;
        RECT  5.244 5.107 5.364 24.593 ;
        RECT  373.716 4.311 373.836 185.769 ;
        RECT  369.396 4.311 369.516 185.769 ;
        RECT  365.076 4.311 365.196 185.769 ;
        RECT  360.756 4.311 360.876 185.769 ;
        RECT  356.436 4.311 356.556 185.769 ;
        RECT  352.116 4.311 352.236 185.769 ;
        RECT  347.796 4.311 347.916 185.769 ;
        RECT  343.476 4.311 343.596 185.769 ;
        RECT  339.156 4.311 339.276 185.769 ;
        RECT  334.836 4.311 334.956 185.769 ;
        RECT  330.516 4.311 330.636 185.769 ;
        RECT  326.196 4.311 326.316 185.769 ;
        RECT  321.876 4.311 321.996 185.769 ;
        RECT  317.556 4.311 317.676 185.769 ;
        RECT  313.236 4.311 313.356 185.769 ;
        RECT  308.916 4.311 309.036 185.769 ;
        RECT  304.596 4.311 304.716 185.769 ;
        RECT  300.276 4.311 300.396 185.769 ;
        RECT  295.956 4.311 296.076 185.769 ;
        RECT  291.636 4.311 291.756 185.769 ;
        RECT  287.316 4.311 287.436 185.769 ;
        RECT  282.996 4.311 283.116 185.769 ;
        RECT  278.676 4.311 278.796 185.769 ;
        RECT  274.356 4.311 274.476 185.769 ;
        RECT  270.036 4.311 270.156 185.769 ;
        RECT  265.716 4.311 265.836 185.769 ;
        RECT  261.396 4.311 261.516 185.769 ;
        RECT  257.076 4.311 257.196 185.769 ;
        RECT  252.756 4.311 252.876 185.769 ;
        RECT  248.436 4.311 248.556 185.769 ;
        RECT  244.116 4.311 244.236 185.769 ;
        RECT  239.796 4.311 239.916 185.769 ;
        RECT  235.476 4.311 235.596 185.769 ;
        RECT  231.156 4.311 231.276 185.769 ;
        RECT  226.836 4.311 226.956 185.769 ;
        RECT  222.516 4.311 222.636 185.769 ;
        RECT  218.196 4.311 218.316 185.769 ;
        RECT  213.876 4.311 213.996 185.769 ;
        RECT  209.556 4.311 209.676 185.769 ;
        RECT  205.236 4.311 205.356 185.769 ;
        RECT  200.916 4.311 201.036 185.769 ;
        RECT  196.596 4.311 196.716 185.769 ;
        RECT  192.276 4.311 192.396 185.769 ;
        RECT  187.956 4.311 188.076 185.769 ;
        RECT  183.636 4.311 183.756 185.769 ;
        RECT  179.316 4.311 179.436 185.769 ;
        RECT  174.996 4.311 175.116 185.769 ;
        RECT  170.676 4.311 170.796 185.769 ;
        RECT  166.356 4.311 166.476 185.769 ;
        RECT  162.036 4.311 162.156 185.769 ;
        RECT  157.716 4.311 157.836 185.769 ;
        RECT  153.396 4.311 153.516 185.769 ;
        RECT  149.076 4.311 149.196 185.769 ;
        RECT  144.756 4.311 144.876 185.769 ;
        RECT  140.436 4.311 140.556 185.769 ;
        RECT  136.116 4.311 136.236 185.769 ;
        RECT  131.796 4.311 131.916 185.769 ;
        RECT  127.476 4.311 127.596 185.769 ;
        RECT  123.156 4.311 123.276 185.769 ;
        RECT  118.836 4.311 118.956 185.769 ;
        RECT  114.516 4.311 114.636 185.769 ;
        RECT  110.196 4.311 110.316 185.769 ;
        RECT  105.876 4.311 105.996 185.769 ;
        RECT  101.556 4.311 101.676 185.769 ;
        RECT  97.236 4.311 97.356 185.769 ;
        RECT  92.916 4.311 93.036 185.769 ;
        RECT  88.596 4.311 88.716 185.769 ;
        RECT  84.276 4.311 84.396 185.769 ;
        RECT  79.956 4.311 80.076 185.769 ;
        RECT  75.636 4.311 75.756 185.769 ;
        RECT  71.316 4.311 71.436 185.769 ;
        RECT  66.996 4.311 67.116 185.769 ;
        RECT  62.676 4.311 62.796 185.769 ;
        RECT  58.356 4.311 58.476 185.769 ;
        RECT  54.036 4.311 54.156 185.769 ;
        RECT  49.716 4.311 49.836 185.769 ;
        RECT  45.396 4.311 45.516 185.769 ;
        RECT  41.076 4.311 41.196 185.769 ;
        RECT  36.756 4.311 36.876 185.769 ;
        RECT  32.436 4.311 32.556 185.769 ;
        RECT  28.116 4.311 28.236 185.769 ;
        RECT  23.796 4.311 23.916 185.769 ;
        RECT  19.476 4.311 19.596 185.769 ;
        RECT  15.156 4.311 15.276 185.769 ;
        RECT  10.836 4.311 10.956 185.769 ;
        RECT  6.516 4.311 6.636 185.769 ;
    END
  END VDD
  PIN VSS
    DIRECTION INOUT ;
    USE GROUND ;
    PORT
      LAYER M5 ;
        RECT  374.796 5.377 374.916 24.863 ;
        RECT  374.796 25.897 374.916 45.383 ;
        RECT  373.524 4.297 373.644 185.783 ;
        RECT  369.204 4.311 369.324 185.783 ;
        RECT  364.884 4.311 365.004 185.783 ;
        RECT  360.564 4.311 360.684 185.783 ;
        RECT  356.244 4.311 356.364 185.783 ;
        RECT  351.924 4.311 352.044 185.783 ;
        RECT  347.604 4.311 347.724 185.783 ;
        RECT  343.284 4.311 343.404 185.783 ;
        RECT  338.964 4.311 339.084 185.783 ;
        RECT  334.644 4.311 334.764 185.783 ;
        RECT  330.324 4.311 330.444 185.783 ;
        RECT  326.004 4.311 326.124 185.783 ;
        RECT  321.684 4.311 321.804 185.783 ;
        RECT  317.364 4.297 317.484 185.783 ;
        RECT  313.044 4.311 313.164 185.783 ;
        RECT  308.724 4.311 308.844 185.783 ;
        RECT  304.404 4.311 304.524 185.783 ;
        RECT  300.084 4.311 300.204 185.783 ;
        RECT  295.764 4.311 295.884 185.783 ;
        RECT  291.444 4.311 291.564 185.783 ;
        RECT  287.124 4.311 287.244 185.783 ;
        RECT  282.804 4.311 282.924 185.783 ;
        RECT  278.484 4.311 278.604 185.783 ;
        RECT  274.164 4.311 274.284 185.783 ;
        RECT  269.844 4.311 269.964 185.783 ;
        RECT  265.524 4.311 265.644 185.783 ;
        RECT  261.204 4.311 261.324 185.783 ;
        RECT  256.884 4.297 257.004 185.783 ;
        RECT  252.564 4.297 252.684 185.783 ;
        RECT  248.244 4.297 248.364 185.783 ;
        RECT  243.924 4.297 244.044 185.783 ;
        RECT  239.604 4.311 239.724 185.783 ;
        RECT  235.284 4.311 235.404 185.783 ;
        RECT  230.964 4.311 231.084 185.783 ;
        RECT  226.644 4.311 226.764 185.783 ;
        RECT  222.324 4.311 222.444 185.783 ;
        RECT  218.004 4.311 218.124 185.783 ;
        RECT  213.684 4.311 213.804 185.783 ;
        RECT  209.364 4.311 209.484 185.783 ;
        RECT  205.044 4.311 205.164 185.783 ;
        RECT  200.724 4.311 200.844 185.783 ;
        RECT  196.404 4.311 196.524 185.783 ;
        RECT  192.084 4.311 192.204 185.783 ;
        RECT  187.764 4.311 187.884 185.783 ;
        RECT  183.444 4.297 183.564 185.783 ;
        RECT  179.124 4.311 179.244 185.783 ;
        RECT  174.804 4.311 174.924 185.783 ;
        RECT  170.484 4.311 170.604 185.783 ;
        RECT  166.164 4.311 166.284 185.783 ;
        RECT  161.844 4.311 161.964 185.783 ;
        RECT  157.524 4.311 157.644 185.783 ;
        RECT  153.204 4.311 153.324 185.783 ;
        RECT  148.884 4.311 149.004 185.783 ;
        RECT  144.564 4.311 144.684 185.783 ;
        RECT  140.244 4.311 140.364 185.783 ;
        RECT  135.924 4.311 136.044 185.783 ;
        RECT  131.604 4.311 131.724 185.783 ;
        RECT  127.284 4.311 127.404 185.783 ;
        RECT  122.964 4.297 123.084 185.783 ;
        RECT  118.644 4.311 118.764 185.783 ;
        RECT  114.324 4.311 114.444 185.783 ;
        RECT  110.004 4.311 110.124 185.783 ;
        RECT  105.684 4.311 105.804 185.783 ;
        RECT  101.364 4.311 101.484 185.783 ;
        RECT  97.044 4.311 97.164 185.783 ;
        RECT  92.724 4.311 92.844 185.783 ;
        RECT  88.404 4.311 88.524 185.783 ;
        RECT  84.084 4.311 84.204 185.783 ;
        RECT  79.764 4.311 79.884 185.783 ;
        RECT  75.444 4.311 75.564 185.783 ;
        RECT  71.124 4.311 71.244 185.783 ;
        RECT  66.804 4.311 66.924 185.783 ;
        RECT  62.484 4.297 62.604 185.783 ;
        RECT  58.164 4.311 58.284 185.783 ;
        RECT  53.844 4.311 53.964 185.783 ;
        RECT  49.524 4.311 49.644 185.783 ;
        RECT  45.204 4.311 45.324 185.783 ;
        RECT  40.884 4.311 41.004 185.783 ;
        RECT  36.564 4.311 36.684 185.783 ;
        RECT  32.244 4.311 32.364 185.783 ;
        RECT  27.924 4.311 28.044 185.783 ;
        RECT  23.604 4.311 23.724 185.783 ;
        RECT  19.284 4.311 19.404 185.783 ;
        RECT  14.964 4.311 15.084 185.783 ;
        RECT  10.644 4.311 10.764 185.783 ;
        RECT  6.324 4.297 6.444 185.783 ;
    END
  END VSS
  OBS
    LAYER RVTN ;
     RECT  2.257 4.297 377.957 190.08 ;
    LAYER RVTP ;
     RECT  2.257 4.297 377.957 190.08 ;
    LAYER M1 ;
     RECT  2.257 4.297 377.957 190.08 ;
    LAYER M2 ;
     RECT  2.257 4.297 377.957 190.08 ;
    LAYER M3 ;
     RECT  2.257 4.297 377.957 190.08 ;
    LAYER M4 ;
     RECT  2.257 4.297 377.957 190.08 ;
    LAYER M5 ;
     RECT  2.257 4.297 377.957 190.08 ;
    LAYER M6 ;
     RECT  2.257 4.297 377.957 190.08 ;
    LAYER M7 ;
     RECT  2.257 4.297 377.957 190.08 ;
  END
END kv3_pv_pair
END LIBRARY
